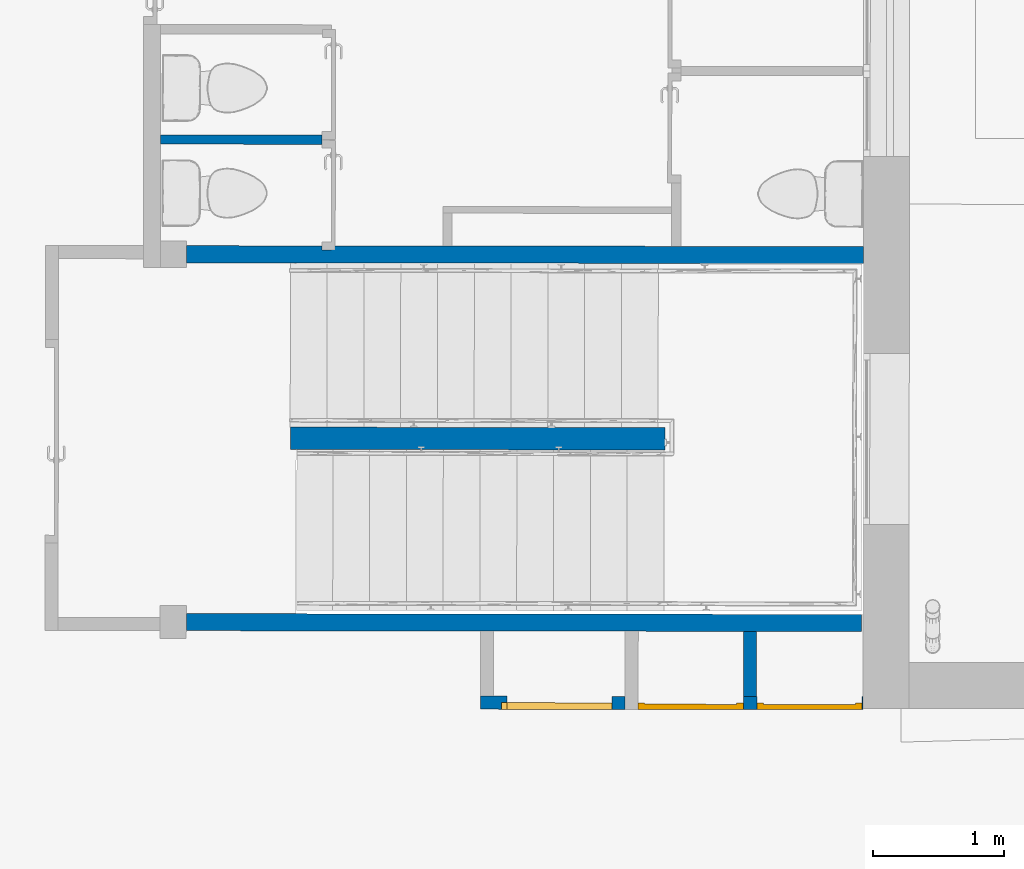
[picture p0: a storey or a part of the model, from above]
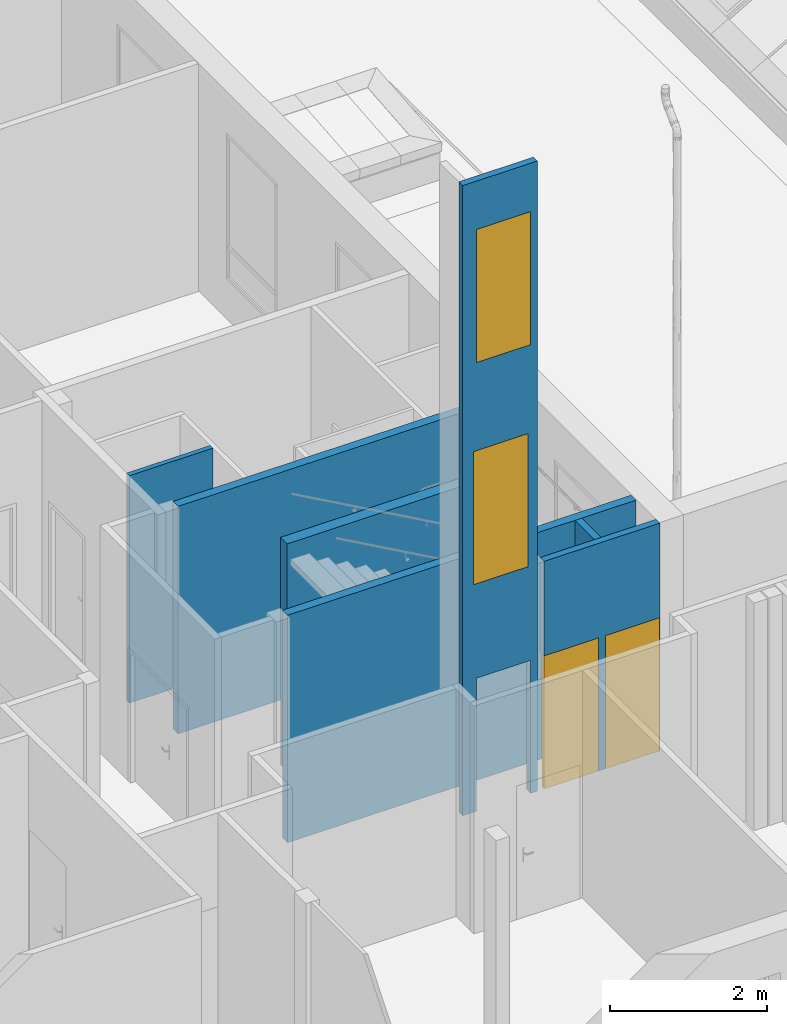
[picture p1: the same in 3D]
Properties of the parts of a building model (IFC2X3), part 1 of 4

# File
Description: ViewDefinition [CoordinationView_V2.0], RevitIdentifiers [ContentGUID: f4caa33b-e047-426b-b9fa-e7164e717685, VersionGUID: ece20d67-56b8-495e-9a75-15ed486fb8ca, NumberOfSaves: 694], CoordinateReference [CoordinateBase: Coordonnées partagées, ProjectSite: Interne]
File name: 260204_RECTORAT.ifc
Time: 2026-02-04T08:34:32+01:00
Written by: ODA SDAI 24.12
Made in: Autodesk Revit 25.4.0.32 (FRA) - IFC 25.4.0.32

# IfcProject, 792
LongName: RECTORAT DE REIMS; Phase: Etat du projet

# IfcSite, Surface:3634237
RefLatitude: 49, 14, 39, 881286; RefLongitude: 4, 2, 24, 676208; RefElevation: 0 m

# IfcBuilding
Pset_BuildingCommon - NumberOfStoreys: 7

# IfcBuildingStorey: Niveau:Ligne du Niveau (7)
Name | LongName | Elevation (m)
R-1 | R-1 | -7.05
rez de rue -1.10m | rez de rue -1.10m | -4.63
Rez de Rue Simon | Rez de Rue Simon | -3.55
0- Rdc | 0- Rdc | -5.76469e-13
1-R+1 | 1-R+1 | 3.55
2-R+2 | 2-R+2 | 7
3-Combles | 3-Combles | 10.03

# IfcBeam: ART-Béton - Poutre rectangulaire:Po 20x105 ht, ART-Béton - Poutre rectangulaire:Po 20x105 ht:3793338
In: Rez de Rue Simon
Type - PredefinedType: BEAM
Type - Pset_BeamCommon - LoadBearing: yes
Material: OMD_BLEU T1 23 25-SIKKKENS
Pset_BeamCommon - IsExternal: no; Slope: 0 deg; Reference: Po 20x105 ht; Span: 4 m
Pset_QuantityTakeOff - Reference: Po 20x105 ht; sets with these values: 2

# IfcBeam: ART-Béton - Poutre rectangulaire:Po 20x105 ht, ART-Béton - Poutre rectangulaire:Po 20x105 ht:3793427
In: Rez de Rue Simon
Type - Pset_BeamCommon - LoadBearing: yes
Material: OMD_BLEU T1 23 25-SIKKKENS
Pset_BeamCommon - IsExternal: no; Slope: 0 deg; Reference: Po 20x105 ht; Span: 7.52 m
Pset_QuantityTakeOff - Reference: Po 20x105 ht; sets with these values: 2

# IfcBeam: ART-Béton - Poutre rectangulaire:Po 20x40 ht (2)
Type - PredefinedType: BEAM
Type - Pset_BeamCommon - LoadBearing: yes
Material: Béton - Béton coulé sur place
Pset_BeamCommon - IsExternal: no; Slope: 0 deg; Reference: Po 20x40 ht; Span: 1.65911 m
Pset_QuantityTakeOff - Reference: Po 20x40 ht; sets with these values: 2
Name (ART-Béton - Poutre rectangulaire:Po 20x40 ht:...) | In
3980615 | Rez de Rue Simon
3980827 | rez de rue -1.10m

# IfcBeam: ART-Béton - Poutre rectangulaire:Po 20x60 ht, ART-Béton - Poutre rectangulaire:Po 20x60 ht:3804751
In: Rez de Rue Simon
Type - Pset_BeamCommon - LoadBearing: yes
Material: Béton - Béton coulé sur place
Pset_BeamCommon - IsExternal: no; Slope: 0 deg; Reference: Po 20x60 ht; Span: 4.89997 m
Pset_QuantityTakeOff - Reference: Po 20x60 ht; sets with these values: 2

# IfcBeam: ART-Béton - Poutre rectangulaire:Po 50x105 (4)
In: 0- Rdc
Type - PredefinedType: BEAM
Type - Pset_BeamCommon - LoadBearing: yes
Material: OMD_beton brut
Pset_BeamCommon - IsExternal: no; Reference: Po 50x105
Pset_QuantityTakeOff - Reference: Po 50x105; sets with these values: 2
Name (ART-Béton - Poutre rectangulaire:Po 50x105:...) | Span (m) | Slope (deg)
3305003 | 23.0697 | 0.510385
3305045 | 23.0697 | 0.510385
3305083 | 23.0915 | 0.509904
3305131 | 23.0959 | 0.510385

# IfcBeam: ART-Béton - Poutre rectangulaire:Po 5x5 ht acier (12)
Type - PredefinedType: BEAM
Type - Pset_BeamCommon - LoadBearing: yes
Material: RAL 7016 - Anthracite Grey
Pset_BeamCommon - IsExternal: no; Reference: Po 5x5 ht acier
Pset_QuantityTakeOff - Reference: Po 5x5 ht acier; sets with these values: 2
Name (ART-Béton - Poutre rectangulaire:Po 5x5 ht acier:...) | In | Span (m) | Slope (deg)
3578441 | Rez de Rue Simon | 8.45535 | 0.576966
3578546 | Rez de Rue Simon | 8.45174 | 0.639205
5396951 | 0- Rdc | 2.92444 | 1.0679
5397064 | 0- Rdc | 2.27062 | 0.000471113
5397077 | 0- Rdc | 4.4843 | 0.000399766
5397089 | 0- Rdc | 2.3227 | 0.00046729
5397097 | 0- Rdc | 2.93 | 0
5397385 | 0- Rdc | 4.5 | 0
5459528 | Rez de Rue Simon | 10.413 | 0.541948
5485070 | Rez de Rue Simon | 10.4623 | 0.544122
5485907 | Rez de Rue Simon | 4.62568 | 0.576966
5485982 | Rez de Rue Simon | 4.62568 | 0.576966

# IfcBeam: Basting:50*200 (10)
In: Rez de Rue Simon
Type - PredefinedType: BEAM
Type - Pset_BeamCommon - LoadBearing: yes
Material: Bois - Bois de construction de dimensions courantes
Pset_BeamCommon - IsExternal: no; Slope: 0 deg; Reference: 50*200
Pset_QuantityTakeOff - Reference: 50*200; sets with these values: 2
Name (Basting:50*200:...) | Span (m)
3705377 | 5.344
3705426 | 5.48
3705459 | 5.379
3705491 | 5.379
3705527 | 5.379
3705563 | 5.379
3754956 | 5.379
3755321 | 5.343
4002185 | 5.379
4002186 | 5.379

# IfcBeam: Basting:poutre BLC GL24h 100x240 (19)
Type - PredefinedType: BEAM
Type - Pset_BeamCommon - LoadBearing: yes
Material: Bois - Bois de construction de dimensions courantes
Pset_BeamCommon - IsExternal: no; Reference: poutre BLC GL24h 100x240
Pset_QuantityTakeOff - Reference: poutre BLC GL24h 100x240; sets with these values: 2
Name (Basting:poutre BLC GL24h 100x240:...) | In | Slope (deg) | Span (m)
4304110 | R-1 | 0 | 2.96
5301227 | Rez de Rue Simon | 0.00000120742 | 2.66
5301454 | Rez de Rue Simon | 0 | 1.851
5301537 | Rez de Rue Simon | 0 | 1.85
5301573 | Rez de Rue Simon | 0 | 1.85
5301637 | Rez de Rue Simon | 0 | 1.85
5301671 | Rez de Rue Simon | 0 | 2.47
5301752 | Rez de Rue Simon | 0 | 2.469
5301788 | Rez de Rue Simon | 0 | 1.851
5301858 | Rez de Rue Simon | 0 | 1.851
5301893 | Rez de Rue Simon | 0 | 1.85
5302000 | Rez de Rue Simon | 0 | 1.85
5302042 | Rez de Rue Simon | 0 | 2.651
5302099 | Rez de Rue Simon | 0.00000120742 | 2.64
5302156 | Rez de Rue Simon | 0 | 1.85
5302232 | Rez de Rue Simon | 0 | 1.851
5302264 | Rez de Rue Simon | 0 | 1.85
5302329 | Rez de Rue Simon | 0 | 1.85
5302355 | Rez de Rue Simon | 0 | 2.46

# IfcBeam: Basting:poutre BLC GL24h 100x280 (6)
In: Rez de Rue Simon
Type - PredefinedType: BEAM
Type - Pset_BeamCommon - LoadBearing: yes
Material: Bois - Bois de construction de dimensions courantes
Pset_BeamCommon - IsExternal: no; Slope: 0 deg; Reference: poutre BLC GL24h 100x280
Pset_QuantityTakeOff - Reference: poutre BLC GL24h 100x280; sets with these values: 2
Name (Basting:poutre BLC GL24h 100x280:...) | Span (m)
5301495 | 2.351
5301600 | 2.35
5301829 | 2.35
5301972 | 2.349
5302182 | 2.349
5302294 | 2.35

# IfcBeam: Basting:poutre BLC GL24h 100x320 (4)
In: Rez de Rue Simon
Type - PredefinedType: BEAM
Type - Pset_BeamCommon - LoadBearing: yes
Material: Bois - Bois de construction de dimensions courantes
Pset_BeamCommon - IsExternal: no; Slope: 0 deg; Reference: poutre BLC GL24h 100x320
Pset_QuantityTakeOff - Reference: poutre BLC GL24h 100x320; sets with these values: 2
Name (Basting:poutre BLC GL24h 100x320:...) | Span (m)
5300478 | 0.464
5300546 | 0.499
5301009 | 1.851
5301033 | 1.86

# IfcBeam: Basting:poutre BLC GL24h 100x360 (5)
In: Rez de Rue Simon
Type - PredefinedType: BEAM
Type - Pset_BeamCommon - LoadBearing: yes
Material: Bois - Bois de construction de dimensions courantes
Pset_BeamCommon - IsExternal: no; Slope: 0 deg; Reference: poutre BLC GL24h 100x360
Pset_QuantityTakeOff - Reference: poutre BLC GL24h 100x360; sets with these values: 2
Name (Basting:poutre BLC GL24h 100x360:...) | Span (m)
5300805 | 2.351
5301063 | 2.35
5301519 | 2.851
5301933 | 2.85
5302206 | 2.85

# IfcBeam: Basting:poutre BLC GL24h 120x400, Basting:poutre BLC GL24h 120x400:5300973
In: Rez de Rue Simon
Type - PredefinedType: BEAM
Type - Pset_BeamCommon - LoadBearing: yes
Material: Bois - Bois de construction de dimensions courantes
Pset_BeamCommon - IsExternal: no; Slope: 0 deg; Reference: poutre BLC GL24h 120x400; Span: 2.851 m
Pset_QuantityTakeOff - Reference: poutre BLC GL24h 120x400; sets with these values: 2

# IfcBeam: Basting:solive BM C24 100X160 EA 600 (40)
In: Rez de Rue Simon
Type - PredefinedType: BEAM
Type - Pset_BeamCommon - LoadBearing: yes
Material: Bois - Bois de construction de dimensions courantes
Pset_BeamCommon - IsExternal: no; Slope: 0 deg; Reference: solive BM C24 100X160 EA 600
Pset_QuantityTakeOff - Reference: solive BM C24 100X160 EA 600; sets with these values: 2
Name (Basting:solive BM C24 100X160 EA 600:...) | Span (m)
5303792 | 2.287
5303817 | 2.287
5303842 | 2.3
5303867 | 2.28
5303905 | 2.306
5303939 | 2.306
5303977 | 2.32
5304009 | 2.292
5304036 | 2.28
5304059 | 2.28
5304084 | 2.28
5304104 | 2.28
5304132 | 2.3
5304161 | 2.3
5304193 | 2.3
5304222 | 2.311
5304252 | 2.311
5304281 | 2.311
5304308 | 2.311
5304345 | 2.308
5304378 | 2.306
5304405 | 2.31
5304436 | 2.308
5304458 | 2.308
5304492 | 2.307
5304518 | 2.306
5304544 | 2.305
5304571 | 2.305
5304590 | 2.303
5304616 | 2.302
5304643 | 2.301
5304665 | 2.301
5304700 | 2.299
5304722 | 2.321
5304749 | 2.298
5304777 | 2.297
5304809 | 2.331
5304832 | 2.322
5304862 | 2.331
5304896 | 2.32

# IfcBeam: Basting:solive BM C24 10X220 EA 600 (120)
In: Rez de Rue Simon
Type - PredefinedType: BEAM
Type - Pset_BeamCommon - LoadBearing: yes
Material: Bois - Bois de construction de dimensions courantes
Pset_BeamCommon - IsExternal: no; Slope: 0 deg; Reference: solive BM C24 10X220 EA 600
Pset_QuantityTakeOff - Reference: solive BM C24 10X220 EA 600; sets with these values: 2
Name (Basting:solive BM C24 10X220 EA 600:...) | Span (m)
5304961 | 3.229
5304980 | 3.23
5305010 | 3.23
5305025 | 3.23
5305057 | 3.18
5305077 | 3.23
5305090 | 3.23
5305116 | 3.22
5305132 | 3.18
5305149 | 3.23
5305166 | 3.24
5305189 | 3.229
5305211 | 3.229
5305237 | 3.18
5305274 | 3.23
5305297 | 3.22
5305325 | 3.24
5305348 | 3.23
5305365 | 3.18
5305388 | 3.23
5305422 | 3.24
5305442 | 3.23
5305455 | 3.2
5305479 | 3.229
5305494 | 3.229
5305529 | 3.229
5305544 | 3.18
5305563 | 3.23
5305585 | 3.22
5305612 | 3.229
5305635 | 3.23
5305657 | 3.18
5305676 | 3.229
5305700 | 3.24
5305715 | 3.229
5305743 | 3.2
5305776 | 3.23
5305797 | 3.23
5305820 | 3.24
5305843 | 3.23
5306093 | 3.23
5306094 | 3.23
5306095 | 3.23
5306096 | 3.23
5306097 | 3.18
5306098 | 3.23
5306099 | 3.23
5306100 | 3.269
5306101 | 3.18
5306102 | 3.23
5306103 | 3.24
5306104 | 3.23
5306105 | 3.23
5306106 | 3.18
5306107 | 3.23
5306108 | 3.22
5306109 | 3.24
5306110 | 3.23
5306111 | 3.18
5306112 | 3.23
5306113 | 3.24
5306114 | 3.23
5306115 | 3.2
5306116 | 3.229
5306117 | 3.23
5306118 | 3.229
5306119 | 3.18
5306120 | 3.23
5306121 | 3.22
5306122 | 3.229
5306123 | 3.23
5306124 | 3.18
5306125 | 3.229
5306126 | 3.24
5306127 | 3.229
5306128 | 3.2
5306129 | 3.23
5306130 | 3.23
5306131 | 3.24
5306132 | 3.23
5306140 | 3.169
5306141 | 3.169
5306142 | 3.168
5306143 | 3.167
5306144 | 3.142
5306145 | 3.166
5306146 | 3.166
5306147 | 3.165
5306148 | 3.14
5306149 | 3.164
5306150 | 3.174
5306151 | 1.582
5306152 | 1.581
5306153 | 1.556
5306154 | 1.58
5306155 | 1.579
5306156 | 1.59
5306157 | 1.578
5306158 | 1.553
5306159 | 1.577
5306160 | 1.587
5306161 | 1.576
5306162 | 1.571
5306163 | 1.575
5306164 | 1.574
5306165 | 1.573
5306166 | 1.549
5306167 | 1.572
5306168 | 1.563
5306169 | 1.571
5306170 | 3.149
5306171 | 3.123
5306172 | 3.147
5306173 | 3.147
5306174 | 3.146
5306175 | 3.12
5306176 | 3.144
5306177 | 3.144
5306178 | 3.154
5306179 | 3.142

# IfcBeam: Basting:solive BM C24 120X320 EA 600 (42)
In: Rez de Rue Simon
Type - PredefinedType: BEAM
Type - Pset_BeamCommon - LoadBearing: yes
Material: Bois - Bois de construction de dimensions courantes
Pset_BeamCommon - IsExternal: no; Slope: 0 deg; Reference: solive BM C24 120X320 EA 600
Pset_QuantityTakeOff - Reference: solive BM C24 120X320 EA 600; sets with these values: 2
Name (Basting:solive BM C24 120X320 EA 600:...) | Span (m)
5306624 | 4.454
5306698 | 4.455
5306706 | 4.456
5306716 | 4.457
5306728 | 4.448
5306738 | 4.342
5306746 | 4.45
5306754 | 4.451
5306762 | 4.423
5306772 | 4.462
5306780 | 4.463
5306788 | 4.463
5306796 | 4.425
5306804 | 4.465
5306812 | 4.465
5306822 | 4.466
5306832 | 4.428
5306840 | 4.467
5306850 | 4.468
5306860 | 4.469
5306874 | 4.47
5306884 | 4.451
5306892 | 3.327
5306902 | 4.445
5306912 | 4.445
5306922 | 4.444
5306930 | 4.435
5306944 | 4.435
5306954 | 4.435
5306966 | 4.435
5306980 | 3.324
5306988 | 4.435
5306996 | 4.435
5307004 | 4.435
5307014 | 4.435
5307022 | 4.435
5307032 | 4.435
5307042 | 4.435
5307161 | 4.415
5307171 | 4.418
5307296 | 0.802
5307322 | 1.199

# IfcBeam: Poutre - Barre ronde:450MM (2)
In: Rez de Rue Simon
Type - PredefinedType: BEAM
Type - Pset_BeamCommon - LoadBearing: yes
Material: OMD-Gaine
Pset_BeamCommon - IsExternal: no; Reference: 450MM; Slope: 0.605548 deg
Pset_QuantityTakeOff - Reference: 450MM; sets with these values: 2
Name (Poutre - Barre ronde:450MM:...) | Span (m)
4188247 | 14.613
4188297 | 14.486

# IfcBuildingElementProxy: A6305 - Drapes, Pair 36 x 3:A6305 - Drapes, Pair 36"x 3", A6305 - Drapes, Pair 36 x 3:A6305 - Drapes, Pair 36"x 3":4141119
In: rez de rue -1.10m
Type - Material: OMD-rideaux
Pset_BuildingElementProxyCommon - Reference: A6305 - Drapes, Pair 36"x 3"; sets with these values: 2

# IfcBuildingElementProxy: A6305 - Drapes:A6305 - Drapes, Pair 36"x 3" (5)
In: rez de rue -1.10m
Type - Material: OMD-rideaux
Pset_BuildingElementProxyCommon - Reference: A6305 - Drapes, Pair 36"x 3"; sets with these values: 2
Name (A6305 - Drapes:A6305 - Drapes, Pair 36"x 3":...)
3613168
3613169
4280353
4280397
4723777

# IfcBuildingElementProxy: Canva 1200x2400x60 mm:Canva 1200x2400x60 mm Plaster (3)
In: Rez de Rue Simon
Type - Material: Plaster, White RAL 9003, Absorber
Pset_BuildingElementProxyCommon - Reference: Canva 1200x2400x60 mm Plaster; sets with these values: 2
Name (Canva 1200x2400x60 mm:Canva 1200x2400x60 mm Plaster:...)
4249678
5474097
5485304

# IfcBuildingElementProxy: Canva 1200x900x60 mm:Canva 1200x900x60 mm Plaster (4)
In: Rez de Rue Simon
Type - Material: Plaster, White RAL 9003, Absorber
Pset_BuildingElementProxyCommon - Reference: Canva 1200x900x60 mm Plaster; sets with these values: 2
Name (Canva 1200x900x60 mm:Canva 1200x900x60 mm Plaster:...)
4249681
5485296
5485298
5485299

# IfcBuildingElementProxy: Constructions-Lifts_Liftup_easylift-900-800:Liftup - Material - Non-skid Linoleum, Constructions-Lifts_Liftup_easylift-900-800:Liftup - Material - Non-skid Linoleum:5440786
In: rez de rue -1.10m
Type - Material: Liftup - Metal - Stainless Steel, Liftup - Plastic - Dark Grey, Liftup - Plastic - Non-skid Linoleum, Painted White, Warning Red
Type - Pset_ManufacturerTypeInformation - Manufacturer: Liftup
Material: Liftup - Metal - Stainless Steel, Liftup - Polycarbonate - Clear, Liftup - Plastic - Non-skid Linoleum
Pset_BuildingElementProxyCommon - Reference: Liftup - Material - Non-skid Linoleum; sets with these values: 2

# IfcBuildingElementProxy: Cordivari_ROSY_VT:H._2200 mm__Altezza Standard (7)
In: Rez de Rue Simon
Type - Material: <Unnamed>, BIANCO RAL 9010
Type - Pset_ManufacturerTypeInformation - Manufacturer: CORDIVARI
Pset_BuildingElementProxyCommon - Reference: H._2200 mm__Altezza Standard; sets with these values: 2
Name (Cordivari_ROSY_VT:H._2200 mm__Altezza Standard:...)
4178981
4179306
4179318
5448377
5448378
5448379
5448380

# IfcBuildingElementProxy: Electronics_Communication_Cisco_LG-86-Display-Single:LG 86" Display Single (3)
In: Rez de Rue Simon
Type - Material: LCD - Cisco - Black, Plastic - Cisco - Dark Gray
Type - Pset_ManufacturerTypeInformation - Manufacturer: Cisco
Material: Plastic - Cisco - Dark Gray, LCD - Cisco - Black
Pset_BuildingElementProxyCommon - Reference: LG 86" Display Single; sets with these values: 2
Name (Electronics_Communication_Cisco_LG-86-Display-Single:LG 86" Display Single:...)
3973912
4651875
4651930

# IfcBuildingElementProxy: FONDATIONS1:FONDATIONS, FONDATIONS1:FONDATIONS:5438699
In: R-1
Type - Material: <Unnamed>
Pset_BuildingElementProxyCommon - Reference: FONDATIONS; sets with these values: 2

# IfcBuildingElementProxy: FONDATIONS2:FONDATIONS, FONDATIONS2:FONDATIONS:5446419
In: R-1
Type - Material: <Unnamed>
Pset_BuildingElementProxyCommon - Reference: FONDATIONS; sets with these values: 2

# IfcBuildingElementProxy: FONDATIONS3:FONDATIONS, FONDATIONS3:FONDATIONS:5446494
In: R-1
Type - Material: <Unnamed>
Pset_BuildingElementProxyCommon - Reference: FONDATIONS; sets with these values: 2

# IfcBuildingElementProxy: FONDATIONS:FONDATIONS, FONDATIONS:FONDATIONS:5437896
In: R-1
Type - Material: <Unnamed>
Pset_BuildingElementProxyCommon - Reference: FONDATIONS; sets with these values: 2

# IfcBuildingElementProxy: ISOLANT COMBLEMENT ESC:ISOLANT COMBLEMENT ESC, ISOLANT COMBLEMENT ESC:ISOLANT COMBLEMENT ESC:3799403
In: Rez de Rue Simon
Type - Material: Maçonnerie - Isolant
Pset_BuildingElementProxyCommon - Reference: ISOLANT COMBLEMENT ESC; sets with these values: 2

# IfcBuildingElementProxy: Profil en relief:tube facade profil 1% (4)
Material: OMD_couleur facade-blanc perlé
Pset_BuildingElementProxyCommon - Reference: tube facade profil 1%; sets with these values: 2
Name (Profil en relief:tube facade profil 1%:...) | In
5286197 | 0- Rdc
5286381 | Rez de Rue Simon
5286421 | rez de rue -1.10m
5287493 | 0- Rdc

# IfcBuildingElementProxy: Rockfon Canva Floor Screen 1200 x 1800 x 61 mm_flat_base:Rockfon Canva Floor Screen 1200 x 1800 x 61 mm_flat_base_Frame_White_Canvas_Plaster (9)
In: rez de rue -1.10m
Type - Material: Plaster, White
Pset_BuildingElementProxyCommon - Reference: Rockfon Canva Floor Screen 1200 x 1800 x 61 mm_flat_base_Frame_White_Canvas_Plaster; sets with these values: 2
Name (Rockfon Canva Floor Screen 1200 x 1800 x 61 mm_flat_base:Rockfon Canva Floor Screen 1200 x 1800 x 61 mm_flat_base_Frame_White_Canvas_Plaster:...)
5418240
5418241
5418242
5418243
5418244
5418245
5418246
5418247
5418248

# IfcBuildingElementProxy: Sanitary_Toilet-Accessories_DELABIE_35082W-Basic-angled-grab-bar-135deg:Sanitary_Toilet-Accessories_DELABIE_35082W-Basic-angled-grab-bar-135deg, Sanitary_Toilet-Accessories_DELABIE_35082W-Basic-angled-grab-bar-135deg:Sanitary_Toilet-Accessories_DELABIE_35082W-Basic-angled-grab-bar-135deg:4074320
In: Rez de Rue Simon
Type - Material: 35082W Basic angled grab bar 135deg - 35082W - blanc
Pset_BuildingElementProxyCommon - Reference: Sanitary_Toilet-Accessories_DELABIE_35082W-Basic-angled-grab-bar-135deg; sets with these values: 2

# IfcBuildingElementProxy: Sanitary_Urinals_DELABIE_134718-DELTACERAM-wall-hung-urinal:Sanitary_Urinals_DELABIE_134718-DELTACERAM-wall-hung-urinal, Sanitary_Urinals_DELABIE_134718-DELTACERAM-wall-hung-urinal:Sanitary_Urinals_DELABIE_134718-DELTACERAM-wall-hung-urinal:4210427
In: Rez de Rue Simon
Type - Material: 134718 DELTACÉRAM wall hung urinal - 134718 - blanc
Material: 134718 DELTACÉRAM wall hung urinal - 134718 - blanc, <Unnamed>
Pset_BuildingElementProxyCommon - Reference: Sanitary_Urinals_DELABIE_134718-DELTACERAM-wall-hung-urinal; sets with these values: 2

# IfcBuildingElementProxy: Texte 3D:Texte 3D 1, Texte 3D:Texte 3D 1:3503385
In: Rez de Rue Simon
Pset_BuildingElementProxyCommon - Reference: Texte 3D 1; sets with these values: 2

# IfcBuildingElementProxy: appui fenetre:appui fenetre, appui fenetre:appui fenetre:3309578
In: Rez de Rue Simon
Type - Material: OMD_Béton blanc
Pset_BuildingElementProxyCommon - Reference: appui fenetre; sets with these values: 2

# IfcBuildingElementProxy: gradins:gradins, gradins:gradins:3290303
In: R-1
Type - Material: OMD_Béton blanc
Pset_BuildingElementProxyCommon - Reference: gradins; sets with these values: 2

# IfcBuildingElementProxy: grille 2:grille 2, grille 2:grille 2:4673213
In: 0- Rdc
Type - Material: White RAL 9003
Pset_BuildingElementProxyCommon - Reference: grille 2; sets with these values: 2

# IfcBuildingElementProxy: grille WC:grille WC, grille WC:grille WC:4669382
In: 0- Rdc
Type - Material: White RAL 9003
Pset_BuildingElementProxyCommon - Reference: grille WC; sets with these values: 2

# IfcColumn: ART-Béton-Poteau rectangulaire:15x15 (35)
In: R-1
Type - PredefinedType: COLUMN; Material: Cerisier
Type - Pset_ColumnCommon - LoadBearing: yes
Pset_ColumnCommon - IsExternal: no; Reference: 15x15
Pset_QuantityTakeOff - Reference: 15x15; sets with these values: 2
Name (ART-Béton-Poteau rectangulaire:15x15:...)
3817159
3817262
3817280
3817290
3817300
3817322
3817733
3817768
3817853
3817854
3817856
3817857
3817858
3817859
3817860
3817861
3817871
3817872
3817874
3817875
3817876
3817877
3817878
3817879
3817977
3817978
3817979
3817980
3817981
4301156
4301157
4301158
4301327
4301328
4301329

# IfcColumn: ART-Béton-Poteau rectangulaire:15x2 ventelles (20)
In: Rez de Rue Simon
Type - PredefinedType: COLUMN; Material: Bois - Bois de construction de dimensions courantes
Type - Pset_ColumnCommon - LoadBearing: yes
Pset_ColumnCommon - IsExternal: no; Reference: 15x2 ventelles
Pset_QuantityTakeOff - Reference: 15x2 ventelles; sets with these values: 2
Name (ART-Béton-Poteau rectangulaire:15x2 ventelles:...)
3704977
3704987
3704997
3705007
3705017
3706369 | Pset_ColumnCommon - Slope: 0 deg
3706370 | Pset_ColumnCommon - Slope: 0 deg
3754954 | Pset_ColumnCommon - Slope: 0 deg
3754955 | Pset_ColumnCommon - Slope: 0 deg
4002103
4002115
4820052
4916291
4916292
4916293
4916294
4916295
4916296
4916297
4916298

# IfcColumn: ART-Béton-Poteau rectangulaire:20X20 (32)
Type - PredefinedType: COLUMN; Material: <Unnamed>
Type - Pset_ColumnCommon - LoadBearing: yes
Pset_ColumnCommon - IsExternal: no; Reference: 20X20
Pset_QuantityTakeOff - Reference: 20X20; sets with these values: 2
Name (ART-Béton-Poteau rectangulaire:20X20:...) | In
3229581 | 0- Rdc
3229723 | 0- Rdc
3230643 | 0- Rdc
3230644 | 0- Rdc
3230715 | 0- Rdc
3230716 | 0- Rdc
3230753 | 0- Rdc
3230754 | 0- Rdc
3233405 | 0- Rdc
3233417 | 0- Rdc
3233427 | 0- Rdc
3234115 | 0- Rdc
3238927 | 0- Rdc
3238939 | 0- Rdc
3251588 | Rez de Rue Simon | Pset_ColumnCommon - Slope: 0 deg
3252008 | 0- Rdc
3252346 | Rez de Rue Simon | Pset_ColumnCommon - Slope: 0 deg
3252352 | Rez de Rue Simon | Pset_ColumnCommon - Slope: 0 deg
3252353 | Rez de Rue Simon | Pset_ColumnCommon - Slope: 0 deg
3252354 | Rez de Rue Simon | Pset_ColumnCommon - Slope: 0 deg
3252355 | Rez de Rue Simon
3252365 | Rez de Rue Simon
3252368 | Rez de Rue Simon
3252375 | Rez de Rue Simon | Pset_ColumnCommon - Slope: 0 deg
3252376 | Rez de Rue Simon | Pset_ColumnCommon - Slope: 0 deg
3252377 | Rez de Rue Simon | Pset_ColumnCommon - Slope: 0 deg
3252402 | Rez de Rue Simon
3272346 | R-1
3273177 | R-1
3273178 | R-1
3277271 | R-1
3277653 | R-1

# IfcColumn: ART-Béton-Poteau rectangulaire:20X25 (8)
Type - PredefinedType: COLUMN; Material: <Unnamed>
Type - Pset_ColumnCommon - LoadBearing: yes
Pset_ColumnCommon - IsExternal: no; Reference: 20X25
Pset_QuantityTakeOff - Reference: 20X25; sets with these values: 2
Name (ART-Béton-Poteau rectangulaire:20X25:...) | In
3230350 | 0- Rdc
3230351 | 0- Rdc
3234003 | 0- Rdc
3234004 | 0- Rdc
3250959 | Rez de Rue Simon | Pset_ColumnCommon - Slope: 0 deg
3252351 | Rez de Rue Simon | Pset_ColumnCommon - Slope: 0 deg
3252366 | Rez de Rue Simon
3252367 | Rez de Rue Simon

# IfcColumn: ART-Béton-Poteau rectangulaire:20X30 (25)
Type - PredefinedType: COLUMN; Material: <Unnamed>
Type - Pset_ColumnCommon - LoadBearing: yes
Pset_ColumnCommon - IsExternal: no; Reference: 20X30
Pset_QuantityTakeOff - Reference: 20X30; sets with these values: 2
Name (ART-Béton-Poteau rectangulaire:20X30:...) | In
3230095 | 0- Rdc
3230096 | 0- Rdc
3230283 | 0- Rdc
3230284 | 0- Rdc
3233508 | 0- Rdc
3233518 | 0- Rdc
3234163 | 0- Rdc
3234164 | 0- Rdc
3238803 | 0- Rdc
3238804 | 0- Rdc
3238840 | 0- Rdc
3238841 | 0- Rdc
3252347 | Rez de Rue Simon | Pset_ColumnCommon - Slope: 0 deg
3252348 | Rez de Rue Simon | Pset_ColumnCommon - Slope: 0 deg
3252349 | Rez de Rue Simon | Pset_ColumnCommon - Slope: 0 deg
3252350 | Rez de Rue Simon | Pset_ColumnCommon - Slope: 0 deg
3252369 | Rez de Rue Simon
3252371 | Rez de Rue Simon
3252372 | Rez de Rue Simon
3252373 | Rez de Rue Simon
3252374 | Rez de Rue Simon
3274005 | R-1
3274006 | R-1
3277561 | R-1
3277562 | R-1

# IfcColumn: ART-Béton-Poteau rectangulaire:30X70 (2)
In: Rez de Rue Simon
Type - PredefinedType: COLUMN; Material: <Unnamed>
Type - Pset_ColumnCommon - LoadBearing: yes
Pset_ColumnCommon - IsExternal: no; Reference: 30X70
Pset_QuantityTakeOff - Reference: 30X70; sets with these values: 2
Name (ART-Béton-Poteau rectangulaire:30X70:...)
3252459
3252475

# IfcColumn: ART-Béton-Poteau rectangulaire:30x30, ART-Béton-Poteau rectangulaire:30x30:3230843
In: 0- Rdc
Type - PredefinedType: COLUMN; Material: <Unnamed>
Type - Pset_ColumnCommon - LoadBearing: yes
Pset_ColumnCommon - IsExternal: no; Reference: 30x30
Pset_QuantityTakeOff - Reference: 30x30; sets with these values: 2

# IfcColumn: ART-Béton-Poteau rectangulaire:30x55, ART-Béton-Poteau rectangulaire:30x55:3259848
In: Rez de Rue Simon
Type - PredefinedType: COLUMN; Material: <Unnamed>
Type - Pset_ColumnCommon - LoadBearing: yes
Pset_ColumnCommon - IsExternal: no; Slope: 0 deg; Reference: 30x55
Pset_QuantityTakeOff - Reference: 30x55; sets with these values: 2

# IfcColumn: ART-Béton-Poteau rectangulaire:30x55, ART-Béton-Poteau rectangulaire:30x55:3265502
In: Rez de Rue Simon
Type - PredefinedType: COLUMN; Material: OMD_BLEU T1 23 25-SIKKKENS
Type - Pset_ColumnCommon - LoadBearing: yes
Pset_ColumnCommon - IsExternal: no; Slope: 0 deg; Reference: 30x55
Pset_QuantityTakeOff - Reference: 30x55; sets with these values: 2

# IfcColumn: ART-Béton-Poteau rectangulaire:40x40 (2)
Type - PredefinedType: COLUMN; Material: <Unnamed>
Type - Pset_ColumnCommon - LoadBearing: yes
Pset_ColumnCommon - IsExternal: no; Reference: 40x40
Pset_QuantityTakeOff - Reference: 40x40; sets with these values: 2
Name (ART-Béton-Poteau rectangulaire:40x40:...) | In
3276257 | Rez de Rue Simon | Pset_ColumnCommon - Slope: 0 deg
3276296 | R-1

# IfcColumn: ART-Béton-Poteau rectangulaire:40x50, ART-Béton-Poteau rectangulaire:40x50:3276399
In: Rez de Rue Simon
Type - PredefinedType: COLUMN; Material: <Unnamed>
Type - Pset_ColumnCommon - LoadBearing: yes
Pset_ColumnCommon - IsExternal: no; Slope: 0 deg; Reference: 40x50
Pset_QuantityTakeOff - Reference: 40x50; sets with these values: 2

# IfcColumn: ART-Béton-Poteau rectangulaire:50X27 (2)
In: 0- Rdc
Type - PredefinedType: COLUMN; Material: <Unnamed>
Type - Pset_ColumnCommon - LoadBearing: yes
Pset_ColumnCommon - IsExternal: no; Reference: 50X27
Pset_QuantityTakeOff - Reference: 50X27; sets with these values: 2
Name (ART-Béton-Poteau rectangulaire:50X27:...)
3232734
3232983

# IfcColumn: ART-Béton-Poteau rectangulaire:50X40 (2)
In: 3-Combles
Type - PredefinedType: COLUMN; Material: Béton
Type - Pset_ColumnCommon - LoadBearing: yes
Pset_ColumnCommon - IsExternal: no; Reference: 50X40
Pset_QuantityTakeOff - Reference: 50X40; sets with these values: 2
Name (ART-Béton-Poteau rectangulaire:50X40:...)
4783936
4783994

# IfcColumn: ART-Béton-Poteau rectangulaire:60X40 béton, ART-Béton-Poteau rectangulaire:60X40 béton:4783846
In: 3-Combles
Type - PredefinedType: COLUMN; Material: Béton
Type - Pset_ColumnCommon - LoadBearing: yes
Pset_ColumnCommon - IsExternal: no; Reference: 60X40 béton
Pset_QuantityTakeOff - Reference: 60X40 béton; sets with these values: 2

# IfcColumn: ART-Béton-Poteau rectangulaire:70X40 béton, ART-Béton-Poteau rectangulaire:70X40 béton:4783792
In: 3-Combles
Type - PredefinedType: COLUMN; Material: Béton
Type - Pset_ColumnCommon - LoadBearing: yes
Pset_ColumnCommon - IsExternal: no; Reference: 70X40 béton
Pset_QuantityTakeOff - Reference: 70X40 béton; sets with these values: 2

# IfcColumn: Poteau rectangulaire:200x200mm (2)
In: Rez de Rue Simon
Type - PredefinedType: COLUMN; Material: Métal - Acier
Pset_ColumnCommon - IsExternal: no; Slope: 0 deg; Reference: 200x200mm
Pset_QuantityTakeOff - Reference: 200x200mm; sets with these values: 2
Name (Poteau rectangulaire:200x200mm:...)
3805787
4001351

# IfcColumn: Profil creux rectangulaire RHS:270x50RHS (78)
In: 0- Rdc
Type - PredefinedType: COLUMN; Material: OMD_couleur facade-blanc perlé
Type - Pset_ColumnCommon - LoadBearing: yes
Pset_ColumnCommon - IsExternal: no; Reference: 270x50RHS
Pset_QuantityTakeOff - Reference: 270x50RHS; sets with these values: 2
Name (Profil creux rectangulaire RHS:270x50RHS:...) | Group
3640885
3640905
3640913
3640979
3641446
3641458
3641468
3641480
3641494
3641522
3641534
3641544
3641556
3641576
3641586
3641596
3641610
3641646
3641658
3641670
3641686
3641698
3641708
3641718
3641728
3641762
3641770
3641780
3641794
3641808
3644279
3644388 | Groupe de modèles:Groupe 1 (membre exclu):4317548
3644389 | Groupe de modèles:Groupe 1 (membre exclu):4317548
3644390 | Groupe de modèles:Groupe 1 (membre exclu):4317548
3644391 | Groupe de modèles:Groupe 1 (membre exclu):4317548
3644392 | Groupe de modèles:Groupe 1 (membre exclu):4317548
3644393 | Groupe de modèles:Groupe 1 (membre exclu):4317548
3644395 | Groupe de modèles:Groupe 1 (membre exclu):4317548
3644396 | Groupe de modèles:Groupe 1 (membre exclu):4317548
3644397 | Groupe de modèles:Groupe 1 (membre exclu):4317548
3644398 | Groupe de modèles:Groupe 1 (membre exclu):4317548
3644399 | Groupe de modèles:Groupe 1 (membre exclu):4317548
3644400 | Groupe de modèles:Groupe 1 (membre exclu):4317548
3644401 | Groupe de modèles:Groupe 1 (membre exclu):4317548
3644402 | Groupe de modèles:Groupe 1 (membre exclu):4317548
3644403 | Groupe de modèles:Groupe 1 (membre exclu):4317548
3644404 | Groupe de modèles:Groupe 1 (membre exclu):4317548
3644405 | Groupe de modèles:Groupe 1 (membre exclu):4317548
3644406 | Groupe de modèles:Groupe 1 (membre exclu):4317548
3644407 | Groupe de modèles:Groupe 1 (membre exclu):4317548
3644408 | Groupe de modèles:Groupe 1 (membre exclu):4317548
3644409 | Groupe de modèles:Groupe 1 (membre exclu):4317548
3644410 | Groupe de modèles:Groupe 1 (membre exclu):4317548
3644411 | Groupe de modèles:Groupe 1 (membre exclu):4317548
3644412 | Groupe de modèles:Groupe 1 (membre exclu):4317548
3644413 | Groupe de modèles:Groupe 1 (membre exclu):4317548
3644414 | Groupe de modèles:Groupe 1 (membre exclu):4317548
3644415 | Groupe de modèles:Groupe 1 (membre exclu):4317548
3644416 | Groupe de modèles:Groupe 1 (membre exclu):4317548
3644417 | Groupe de modèles:Groupe 1 (membre exclu):4317548
3644418 | Groupe de modèles:Groupe 1 (membre exclu):4317548
3644419 | Groupe de modèles:Groupe 1 (membre exclu):4317548
3644420 | Groupe de modèles:Groupe 1 (membre exclu):4317548
3644421 | Groupe de modèles:Groupe 1 (membre exclu):4317548
3644422 | Groupe de modèles:Groupe 1 (membre exclu):4317548
3644423 | Groupe de modèles:Groupe 1 (membre exclu):4317548
3661567 | Groupe de modèles:Groupe 1 (membre exclu):4317548
4150109 | Groupe de modèles:Groupe 1 (membre exclu):4317548
4150111 | Groupe de modèles:Groupe 1 (membre exclu):4317548
4150113 | Groupe de modèles:Groupe 1 (membre exclu):4317548
4150115 | Groupe de modèles:Groupe 1 (membre exclu):4317548
4150117 | Groupe de modèles:Groupe 1 (membre exclu):4317548
4150119 | Groupe de modèles:Groupe 1 (membre exclu):4317548
4150121 | Groupe de modèles:Groupe 1 (membre exclu):4317548
4150123 | Groupe de modèles:Groupe 1 (membre exclu):4317548
4150125 | Groupe de modèles:Groupe 1 (membre exclu):4317548
4317487
5184692 | Groupe de modèles:Groupe 1 (membre exclu):4317548

# IfcColumn: Profil creux rectangulaire RHS:270x75RHS (25)
In: Rez de Rue Simon
Type - PredefinedType: COLUMN; Material: OMD_couleur facade-blanc perlé
Type - Pset_ColumnCommon - LoadBearing: yes
Pset_ColumnCommon - IsExternal: no; Reference: 270x75RHS
Pset_QuantityTakeOff - Reference: 270x75RHS; sets with these values: 2
Name (Profil creux rectangulaire RHS:270x75RHS:...)
3644188
3660602
3660603
3660605
3660606
3660608
3660610
3660611
3660613
3660615
3660616
3660618
3660620
3660622
3660623
3660625
3660627
3660628
3660630
3660633
3660635
3660637
3660642
4202234
4728317

# IfcCovering: Plafond composé:BA 13 (3)
Type - PredefinedType: CEILING
Type - Pset_CoveringCommon - TotalThickness: 0.06 m
Material: Faux-plafond - Trame 600 x 600 0.04 m, OMD_Peinture Blanche 0.02 m
Pset_CoveringCommon - Reference: BA 13; sets with these values: 2
Name (Plafond composé:BA 13:...) | In
3496792 | Rez de Rue Simon
4250821 | Rez de Rue Simon
4905058 | rez de rue -1.10m

# IfcCovering: Plafond composé:Dalles 60x120 (8)
In: rez de rue -1.10m
Type - PredefinedType: CEILING
Type - Pset_CoveringCommon - TotalThickness: 0.09 m
Material: Faux-plafond - Trame 600 x 600 0.04 m, Faux-plafond - Trame 600 x 1200 0.05 m
Pset_CoveringCommon - Reference: Dalles 60x120; sets with these values: 2
Name (Plafond composé:Dalles 60x120:...)
4283262
5461563
5464442
5465021
5465598
5465722
5467039
5468135

# IfcCovering: Plafond composé:Dalles 60x60 (14)
Type - PredefinedType: CEILING
Type - Pset_CoveringCommon - TotalThickness: 0.06 m
Material: Faux-plafond - Trame 600 x 600 0.04 m, Faux-plafond - Trame 600 x 600 0.02 m
Pset_CoveringCommon - Reference: Dalles 60x60; sets with these values: 2
Name (Plafond composé:Dalles 60x60:...) | In
3458178 | rez de rue -1.10m
3458186 | rez de rue -1.10m
3458194 | rez de rue -1.10m
3458202 | rez de rue -1.10m
4057207 | Rez de Rue Simon
4801863 | rez de rue -1.10m
4801895 | rez de rue -1.10m
4801965 | Rez de Rue Simon
4801999 | Rez de Rue Simon
5185527 | rez de rue -1.10m
5185545 | rez de rue -1.10m
5185554 | rez de rue -1.10m
5185564 | rez de rue -1.10m
5366421 | Rez de Rue Simon

# IfcCovering: Plafond composé:Dalles 60x60 NOIR (6)
Type - PredefinedType: CEILING
Type - Pset_CoveringCommon - TotalThickness: 0.06 m
Material: Faux-plafond - Trame 600 x 600 0.04 m, OMD_Faux-plafond - Trame 600 x 600NOIR 0.02 m
Pset_CoveringCommon - Reference: Dalles 60x60 NOIR; sets with these values: 2
Name (Plafond composé:Dalles 60x60 NOIR:...) | In
3458210 | rez de rue -1.10m
3458220 | rez de rue -1.10m
4180325 | Rez de Rue Simon
5443062 | Rez de Rue Simon
5447649 | Rez de Rue Simon
5470302 | Rez de Rue Simon

# IfcCovering: Plafond composé:FP- BA 13 (4)
In: rez de rue -1.10m
Type - PredefinedType: CEILING
Type - Pset_CoveringCommon - TotalThickness: 0.06 m
Material: Faux-plafond - Trame 600 x 600 0.04 m, OMD_Cloison 70mm 0.02 m
Pset_CoveringCommon - Reference: FP- BA 13; sets with these values: 2
Name (Plafond composé:FP- BA 13:...)
3543659
4802523
4802573
4802658

# IfcCovering: Plafond composé:FP- BA 13 coloré (4)
Type - PredefinedType: CEILING
Type - Pset_CoveringCommon - TotalThickness: 0.06 m
Material: Faux-plafond - Trame 600 x 600 0.04 m, OMD-plafond coloré 0.02 m
Pset_CoveringCommon - Reference: FP- BA 13 coloré; sets with these values: 2
Name (Plafond composé:FP- BA 13 coloré:...) | In
3575903 | rez de rue -1.10m
4905214 | rez de rue -1.10m
5443026 | Rez de Rue Simon
5447626 | Rez de Rue Simon

# IfcCovering: Plafond composé:isolation, Plafond composé:isolation:5310172
In: R-1
Type - PredefinedType: CEILING
Type - Pset_CoveringCommon - TotalThickness: 0.2 m
Material: Maçonnerie - Isolant 0.2 m
Pset_CoveringCommon - Reference: isolation; sets with these values: 2

# IfcCovering: Plafond composé:plafond cf 1h (8)
Type - PredefinedType: CEILING
Type - Pset_CoveringCommon - TotalThickness: 0.058 m
Material: Faux-plafond - Trame 600 x 600 0.04 m, OMD_Cloison 100mm CF1h 0.018 m
Pset_CoveringCommon - Reference: plafond cf 1h; sets with these values: 2
Name (Plafond composé:plafond cf 1h:...) | In
3458228 | rez de rue -1.10m
3822101 | R-1
4130755 | Rez de Rue Simon
4131322 | Rez de Rue Simon
4296097 | Rez de Rue Simon
4802701 | rez de rue -1.10m
5308122 | R-1
5382469 | R-1

# IfcCurtainWall: Mur-rideau:Menuiserie Ext (7)
Pset_CurtainWallCommon - IsExternal: yes; Reference: Menuiserie Ext
Pset_QuantityTakeOff - Reference: Menuiserie Ext
Name (Mur-rideau:Menuiserie Ext:...) | In
4317773 | Rez de Rue Simon
4317904 | Rez de Rue Simon
4318021 | Rez de Rue Simon
4323526 | Rez de Rue Simon
4323620 | Rez de Rue Simon
5327253 | 0- Rdc
5378885 | 0- Rdc

# IfcCurtainWall: Mur-rideau:Menuiserie Ext 1F+1OB VERTIC (265)
Pset_CurtainWallCommon - IsExternal: yes; Reference: Menuiserie Ext 1F+1OB VERTIC
Pset_QuantityTakeOff - Reference: Menuiserie Ext 1F+1OB VERTIC
Name (Mur-rideau:Menuiserie Ext 1F+1OB VERTIC:...) | In
3241975 | 0- Rdc
3242175 | 0- Rdc
3242195 | 0- Rdc
3242213 | 0- Rdc
3242231 | 0- Rdc
3242251 | 0- Rdc
3242273 | 0- Rdc
3242291 | 0- Rdc
3242362 | 0- Rdc
3242407 | 0- Rdc
3242425 | 0- Rdc
3242443 | 0- Rdc
3242463 | 0- Rdc
3242481 | 0- Rdc
3242501 | 0- Rdc
3242519 | 0- Rdc
3242624 | 0- Rdc
3242689 | 0- Rdc
3242709 | 0- Rdc
3242733 | 0- Rdc
3242753 | 0- Rdc
3242787 | 0- Rdc
3242807 | 0- Rdc
3242829 | 0- Rdc
3242851 | 0- Rdc
3242873 | 0- Rdc
3243067 | 0- Rdc
3243119 | 0- Rdc
3243141 | 0- Rdc
3243161 | 0- Rdc
3243179 | 0- Rdc
3243197 | 0- Rdc
3243217 | 0- Rdc
3243299 | 0- Rdc
3243334 | 0- Rdc
3243486 | 0- Rdc
3243620 | 0- Rdc
3243661 | 0- Rdc
3243679 | 0- Rdc
3243697 | 0- Rdc
3243715 | 0- Rdc
3243735 | 0- Rdc
3243753 | 0- Rdc
3243771 | 0- Rdc
3249596 | 0- Rdc
3258381 | Rez de Rue Simon
3258392 | Rez de Rue Simon
3258403 | Rez de Rue Simon
3258414 | Rez de Rue Simon
3258425 | Rez de Rue Simon
3258436 | Rez de Rue Simon
3258447 | Rez de Rue Simon
3258458 | Rez de Rue Simon
3258469 | Rez de Rue Simon
3258480 | Rez de Rue Simon
3258491 | Rez de Rue Simon
3258502 | Rez de Rue Simon
3258513 | Rez de Rue Simon
3258524 | Rez de Rue Simon
3258535 | Rez de Rue Simon
3258546 | Rez de Rue Simon
3258557 | Rez de Rue Simon
3258568 | Rez de Rue Simon
3258579 | Rez de Rue Simon
3258590 | Rez de Rue Simon
3259396 | Rez de Rue Simon
3259407 | Rez de Rue Simon
3259418 | Rez de Rue Simon
3259429 | Rez de Rue Simon
3259440 | Rez de Rue Simon
3259451 | Rez de Rue Simon
3259462 | Rez de Rue Simon
3259473 | Rez de Rue Simon
3260688 | 0- Rdc
3260741 | 0- Rdc
3261217 | Rez de Rue Simon
3261261 | Rez de Rue Simon
3261305 | Rez de Rue Simon
3263581 | Rez de Rue Simon
3264175 | 0- Rdc
3269864 | Rez de Rue Simon
3293092 | 0- Rdc
3294427 | 1-R+1
3294438 | 1-R+1
3294449 | 1-R+1
3294460 | 1-R+1
3294471 | 1-R+1
3294482 | 1-R+1
3294493 | 1-R+1
3294504 | 1-R+1
3294515 | 1-R+1
3294526 | 1-R+1
3294537 | 1-R+1
3294548 | 1-R+1
3294559 | 1-R+1
3294570 | 1-R+1
3294581 | 1-R+1
3294592 | 1-R+1
3294603 | 1-R+1
3294614 | 1-R+1
3294625 | 1-R+1
3294636 | 1-R+1
3294647 | 1-R+1
3294658 | 1-R+1
3294669 | 1-R+1
3294680 | 1-R+1
3294691 | 1-R+1
3294702 | 1-R+1
3294713 | 1-R+1
3294724 | 1-R+1
3294735 | 1-R+1
3294746 | 1-R+1
3294757 | 1-R+1
3294768 | 1-R+1
3294779 | 1-R+1
3294790 | 1-R+1
3294801 | 1-R+1
3294812 | 1-R+1
3294823 | 1-R+1
3294834 | 1-R+1
3294845 | 1-R+1
3294856 | 1-R+1
3294867 | 1-R+1
3294878 | 1-R+1
3294900 | 1-R+1
3295098 | 1-R+1
3295343 | 1-R+1
3295367 | 1-R+1
3295393 | 1-R+1
3295413 | 1-R+1
3295439 | 1-R+1
3295461 | 1-R+1
3295485 | 1-R+1
3296152 | 1-R+1
3296195 | 1-R+1
3296215 | 1-R+1
3296235 | 1-R+1
3296255 | 1-R+1
3296291 | 1-R+1
3296311 | 1-R+1
3296560 | 1-R+1
3296580 | 1-R+1
3297500 | 2-R+2
3297600 | 2-R+2
3297915 | 2-R+2
3298369 | 2-R+2
3298384 | 2-R+2
3298397 | 2-R+2
3298412 | 2-R+2
3298427 | 2-R+2
3298442 | 2-R+2
3298455 | 2-R+2
3298472 | 2-R+2
3298485 | 2-R+2
3298498 | 2-R+2
3298511 | 2-R+2
3298524 | 2-R+2
3298537 | 2-R+2
3298550 | 2-R+2
3298563 | 2-R+2
3298576 | 2-R+2
3298593 | 2-R+2
3298606 | 2-R+2
3298621 | 2-R+2
3298634 | 2-R+2
3298647 | 2-R+2
3299353 | 2-R+2
3299370 | 2-R+2
3299462 | 2-R+2
3299822 | 2-R+2
3299837 | 2-R+2
3299850 | 2-R+2
3299863 | 2-R+2
3299876 | 2-R+2
3299891 | 2-R+2
3299906 | 2-R+2
3299921 | 2-R+2
3299934 | 2-R+2
3299949 | 2-R+2
3299962 | 2-R+2
3299975 | 2-R+2
3299988 | 2-R+2
3300030 | 2-R+2
3300043 | 2-R+2
3300302 | 2-R+2
3300681 | 2-R+2
3300696 | 2-R+2
3300709 | 2-R+2
3300726 | 2-R+2
3300741 | 2-R+2
3300754 | 2-R+2
3300840 | 2-R+2
3300855 | 2-R+2
3300868 | 2-R+2
3300881 | 2-R+2
3300894 | 2-R+2
3300909 | 2-R+2
3300924 | 2-R+2
3300937 | 2-R+2
3300952 | 2-R+2
3301091 | 2-R+2
3301305 | 2-R+2
3301320 | 2-R+2
3301339 | 2-R+2
3301356 | 2-R+2
3301375 | 2-R+2
3301388 | 2-R+2
3301403 | 2-R+2
3301418 | 2-R+2
3301433 | 2-R+2
3301448 | 2-R+2
3301461 | 2-R+2
3301478 | 2-R+2
3301495 | 2-R+2
3301658 | 2-R+2
3301737 | 2-R+2
3301750 | 2-R+2
3301763 | 2-R+2
3301776 | 2-R+2
3301789 | 2-R+2
3301802 | 2-R+2
3301815 | 2-R+2
3301830 | 2-R+2
3301845 | 2-R+2
3301858 | 2-R+2
3301871 | 2-R+2
3302228 | 2-R+2
3302241 | 2-R+2
3302254 | 2-R+2
3302267 | 2-R+2
3302535 | 2-R+2
3302804 | 2-R+2
3302819 | 2-R+2
3302832 | 2-R+2
3302853 | 2-R+2
3302868 | 2-R+2
3302881 | 2-R+2
3302898 | 2-R+2
3302911 | 2-R+2
3302928 | 2-R+2
3302941 | 2-R+2
3303133 | 2-R+2
3303148 | 2-R+2
3303163 | 2-R+2
3303178 | 2-R+2
3303199 | 2-R+2
3303212 | 2-R+2
3303225 | 2-R+2
3303240 | 2-R+2
3303253 | 2-R+2
3303490 | 2-R+2
3303505 | 2-R+2
3303518 | 2-R+2
3303539 | 2-R+2
3303558 | 2-R+2
3303571 | 2-R+2
3303584 | 2-R+2
3303599 | 2-R+2
3303616 | 2-R+2
3303629 | 2-R+2
3303859 | 2-R+2
3303878 | 2-R+2
4667425 | 0- Rdc
4667592 | 1-R+1
4667603 | 1-R+1

# IfcCurtainWall: Mur-rideau:Menuiserie Ext 2OF+1F VERTIC (7)
In: 0- Rdc
Pset_CurtainWallCommon - IsExternal: yes; Reference: Menuiserie Ext 2OF+1F VERTIC
Pset_QuantityTakeOff - Reference: Menuiserie Ext 2OF+1F VERTIC
Name (Mur-rideau:Menuiserie Ext 2OF+1F VERTIC:...)
3243949
3249100
3249368
3249401
3249438
3249469
3249506

# IfcCurtainWall: Mur-rideau:Menuiserie Int (8)
Pset_CurtainWallCommon - IsExternal: yes; Reference: Menuiserie Int
Pset_QuantityTakeOff - Reference: Menuiserie Int
Name (Mur-rideau:Menuiserie Int:...) | In
3665528 | rez de rue -1.10m
4051815 | Rez de Rue Simon
4056886 | Rez de Rue Simon
4056984 | Rez de Rue Simon
4140116 | rez de rue -1.10m
4279754 | rez de rue -1.10m
4723576 | rez de rue -1.10m
4723995 | rez de rue -1.10m

# IfcCurtainWall: Mur-rideau:Trappe (2)
In: R-1
Pset_CurtainWallCommon - IsExternal: no; Reference: Trappe
Pset_QuantityTakeOff - Reference: Trappe
Name (Mur-rideau:Trappe:...)
5333557
5334329

# IfcDistributionPort (40)
Description: Flow
Name | FlowDirection
OutPort_4061635_1 | SOURCE
InPort_4061635_2 | SINK
InPort_4061635_3 | SINK
OutPort_4061897_1 | SOURCE
InPort_4061897_2 | SINK
InPort_4061897_3 | SINK
InPort_4070678_2 | SINK
OutPort_4070678_3 | SOURCE
InPort_4070740_2 | SINK
OutPort_4070740_3 | SOURCE
InPort_4070748_2 | SINK
OutPort_4070748_3 | SOURCE
InPort_4070756_2 | SINK
OutPort_4070756_3 | SOURCE
Port_4178981_1 | SOURCEANDSINK
Port_4178981_2 | SOURCEANDSINK
Port_4179306_1 | SOURCEANDSINK
Port_4179306_2 | SOURCEANDSINK
Port_4179318_1 | SOURCEANDSINK
Port_4179318_2 | SOURCEANDSINK
OutPort_4230428_1 | SOURCE
InPort_4230428_2 | SINK
InPort_4230428_3 | SINK
OutPort_4230434_1 | SOURCE
InPort_4230434_2 | SINK
InPort_4230434_3 | SINK
OutPort_4234542_1 | SOURCE
InPort_4234542_2 | SINK
InPort_4234542_3 | SINK
OutPort_4234543_1 | SOURCE
InPort_4234543_2 | SINK
InPort_4234543_3 | SINK
Port_5448377_1 | SOURCEANDSINK
Port_5448377_2 | SOURCEANDSINK
Port_5448378_1 | SOURCEANDSINK
Port_5448378_2 | SOURCEANDSINK
Port_5448379_1 | SOURCEANDSINK
Port_5448379_2 | SOURCEANDSINK
Port_5448380_1 | SOURCEANDSINK
Port_5448380_2 | SOURCEANDSINK

# IfcDoor: Double (T):1.63m x 2.04m (2)
In: rez de rue -1.10m
Type - OperationType: DOUBLE_DOOR_SINGLE_SWING; ParameterTakesPrecedence: no; Sizeable: no; Material: Porte - Poignée, OMD_BLEU T1 23 25-SIKKKENS
Type - Double (T):1.63m x 2.04m:3547414:1 - PanelOperation: SWINGING
Type - Pset_DoorCommon - ThermalTransmittance: 3.6886 kg/K/s3
OverallHeight: 2.075 m; OverallWidth: 1.7 m
Pset_DoorCommon - IsExternal: no; Reference: 1.63m x 2.04m
Pset_QuantityTakeOff - Reference: 1.63m x 2.04m
Name (Double (T):1.63m x 2.04m:...)
3547414
4138939

# IfcDoor: Double (T):1.83m x 2.04m (2)
In: rez de rue -1.10m
Type - OperationType: DOUBLE_DOOR_SINGLE_SWING; ParameterTakesPrecedence: no; Sizeable: no; Material: Porte - Poignée, Porte - Cadre, Porte - Panneau
Type - Double (T):1.83m x 2.04m:3694244:1 - PanelOperation: SWINGING
Type - Pset_DoorCommon - ThermalTransmittance: 3.6886 kg/K/s3
OverallHeight: 2.075 m; OverallWidth: 1.9 m
Pset_DoorCommon - IsExternal: no; Reference: 1.83m x 2.04m
Pset_QuantityTakeOff - Reference: 1.83m x 2.04m
Name (Double (T):1.83m x 2.04m:...)
3694244
3694307

# IfcDoor: Grz_Garage sectionnelle:porte sectionnelle 3.6X3, Grz_Garage sectionnelle:porte sectionnelle 3.6X3:4898337
In: Rez de Rue Simon
Type - OperationType: ROLLINGUP; ParameterTakesPrecedence: no; Sizeable: no; Material: Peinture - Grise
Type - Grz_Garage sectionnelle:porte sectionnelle 3.6X3:4898337:1 - PanelOperation: ROLLINGUP
Type - Pset_DoorCommon - ThermalTransmittance: 3.7021 kg/K/s3
OverallHeight: 2.29 m; OverallWidth: 3.62 m
Pset_DoorCommon - IsExternal: yes; Reference: porte sectionnelle 3.6X3
Pset_QuantityTakeOff - Reference: porte sectionnelle 3.6X3

# IfcDoor: Grz_Placard 1V:53x204, Grz_Placard 1V:53x204:3265552
In: Rez de Rue Simon
Type - OperationType: DOUBLE_DOOR_SINGLE_SWING; ParameterTakesPrecedence: no; Sizeable: no; Material: OMD_BLEU T1 23 25-SIKKKENS
Type - Grz_Placard 1V:53x204:3265552:1 - PanelOperation: SWINGING
Type - Pset_DoorCommon - ThermalTransmittance: 3.6886 kg/K/s3
OverallHeight: 2.075 m; OverallWidth: 0.53 m
Pset_DoorCommon - IsExternal: no; Reference: 53x204
Pset_QuantityTakeOff - Reference: 53x204

# IfcDoor: Grz_Placard 1V:80X204 (4)
Type - OperationType: DOUBLE_DOOR_SINGLE_SWING; ParameterTakesPrecedence: no; Sizeable: no; Material: Porte - Panneau, Porte - Cadre
Type - Grz_Placard 1V:80X204:3237916:1 - PanelOperation: SWINGING
Type - Pset_DoorCommon - ThermalTransmittance: 3.6886 kg/K/s3
OverallHeight: 2.075 m; OverallWidth: 0.8 m
Pset_DoorCommon - IsExternal: no; Reference: 80X204
Pset_QuantityTakeOff - Reference: 80X204
Name (Grz_Placard 1V:80X204:...) | In
3237916 | 0- Rdc
3237959 | 0- Rdc
3257746 | Rez de Rue Simon
3257783 | Rez de Rue Simon

# IfcDoor: Grz_Placard 1V:80X204 (2)
In: 0- Rdc
Type - OperationType: DOUBLE_DOOR_SINGLE_SWING; ParameterTakesPrecedence: no; Sizeable: no; Material: Porte - Panneau, Porte - Cadre
Type - Grz_Placard 1V:80X204:3238035:1 - PanelOperation: SWINGING
Type - Pset_DoorCommon - ThermalTransmittance: 3.6886 kg/K/s3
OverallHeight: 2.075 m; OverallWidth: 0.8 m
Pset_DoorCommon - IsExternal: no; Reference: 80X204
Pset_QuantityTakeOff - Reference: 80X204
Name (Grz_Placard 1V:80X204:...)
3238035
3238078

# IfcDoor: Grz_Placard 1V:80X204, Grz_Placard 1V:80X204:5340598
In: 0- Rdc
Type - OperationType: DOUBLE_DOOR_SINGLE_SWING; ParameterTakesPrecedence: no; Sizeable: no; Material: Porte - Panneau, Porte - Cadre
Type - Grz_Placard 1V:80X204:5340598:1 - PanelOperation: SWINGING
Type - Pset_DoorCommon - ThermalTransmittance: 3.6886 kg/K/s3
OverallHeight: 2.075 m; OverallWidth: 0.8 m
Pset_DoorCommon - IsExternal: no; Reference: 80X204
Pset_QuantityTakeOff - Reference: 80X204

# IfcDoor: Grz_Placard 1V:80X204 (2)
Type - OperationType: DOUBLE_DOOR_SINGLE_SWING; ParameterTakesPrecedence: no; Sizeable: no; Material: Porte - Panneau, Porte - Cadre
Type - Grz_Placard 1V:80X204:5373717:1 - PanelOperation: SWINGING
Type - Pset_DoorCommon - ThermalTransmittance: 3.6886 kg/K/s3
OverallHeight: 2.075 m; OverallWidth: 0.8 m
Pset_DoorCommon - IsExternal: no; Reference: 80X204
Pset_QuantityTakeOff - Reference: 80X204
Name (Grz_Placard 1V:80X204:...) | In
5373717 | 1-R+1
5373759 | 2-R+2

# IfcDoor: Grz_Placard 2V:140x204, Grz_Placard 2V:140x204:3265580
In: Rez de Rue Simon
Type - OperationType: DOUBLE_DOOR_SINGLE_SWING; ParameterTakesPrecedence: no; Sizeable: no; Material: OMD_Peinture mur
Type - Grz_Placard 2V:140x204:3265580:1 - PanelOperation: SWINGING
Type - Pset_DoorCommon - ThermalTransmittance: 3.6886 kg/K/s3
OverallHeight: 2.075 m; OverallWidth: 1.4 m
Pset_DoorCommon - IsExternal: no; Reference: 140x204
Pset_QuantityTakeOff - Reference: 140x204

# IfcDoor: Grz_Placard 2V:140x204, Grz_Placard 2V:140x204:5366304
In: Rez de Rue Simon
Type - OperationType: DOUBLE_DOOR_SINGLE_SWING; ParameterTakesPrecedence: no; Sizeable: no; Material: OMD_Peinture mur
Type - Grz_Placard 2V:140x204:5366304:1 - PanelOperation: SWINGING
Type - Pset_DoorCommon - ThermalTransmittance: 3.6886 kg/K/s3
OverallHeight: 2.075 m; OverallWidth: 1.4 m
Pset_DoorCommon - IsExternal: no; Reference: 140x204
Pset_QuantityTakeOff - Reference: 140x204

# IfcDoor: Grz_porte 1V recouvrement 30°:80x204 (2)
In: Rez de Rue Simon
Type - OperationType: SINGLE_SWING_LEFT; ParameterTakesPrecedence: no; Sizeable: no; Material: Porte - Poignée, Porte - Cadre, Porte - Panneau
Type - Grz_porte 1V recouvrement 30°:80x204:3375352:1 - PanelOperation: SWINGING
Type - Pset_DoorCommon - ThermalTransmittance: 3.7021 kg/K/s3
OverallHeight: 2.075 m; OverallWidth: 0.87 m
Pset_DoorCommon - IsExternal: no; Reference: 80x204
Pset_QuantityTakeOff - Reference: 80x204
Name (Grz_porte 1V recouvrement 30°:80x204:...)
3375352
3375361

# IfcDoor: Grz_porte 1V recouvrement 30°:80x204, Grz_porte 1V recouvrement 30°:80x204:4236965
In: rez de rue -1.10m
Type - OperationType: SINGLE_SWING_LEFT; ParameterTakesPrecedence: no; Sizeable: no; Material: Porte - Poignée, Porte - Cadre, Porte - Panneau
Type - Grz_porte 1V recouvrement 30°:80x204:4236965:1 - PanelOperation: SWINGING
Type - Pset_DoorCommon - ThermalTransmittance: 3.7021 kg/K/s3
OverallHeight: 2.075 m; OverallWidth: 0.87 m
Pset_DoorCommon - IsExternal: no; Reference: 80x204
Pset_QuantityTakeOff - Reference: 80x204

# IfcDoor: Grz_porte 1V recouvrement 30°:80x204 (2)
In: Rez de Rue Simon
Type - OperationType: SINGLE_SWING_RIGHT; ParameterTakesPrecedence: no; Sizeable: no; Material: Porte - Poignée, OMD_RAL1032
Type - Grz_porte 1V recouvrement 30°:80x204:3326648:1 - PanelOperation: SWINGING
Type - Pset_DoorCommon - ThermalTransmittance: 3.7021 kg/K/s3
OverallHeight: 2.075 m; OverallWidth: 0.87 m
Pset_DoorCommon - IsExternal: no; Reference: 80x204
Pset_QuantityTakeOff - Reference: 80x204
Name (Grz_porte 1V recouvrement 30°:80x204:...)
3326648
3375339

# IfcDoor: Grz_porte 1V recouvrement 30°:80x204, Grz_porte 1V recouvrement 30°:80x204:4099117
In: rez de rue -1.10m
Type - OperationType: SINGLE_SWING_RIGHT; ParameterTakesPrecedence: no; Sizeable: no; Material: Porte - Poignée, OMD_RAL1032
Type - Grz_porte 1V recouvrement 30°:80x204:4099117:1 - PanelOperation: SWINGING
Type - Pset_DoorCommon - ThermalTransmittance: 3.7021 kg/K/s3
OverallHeight: 2.075 m; OverallWidth: 0.87 m
Pset_DoorCommon - IsExternal: no; Reference: 80x204
Pset_QuantityTakeOff - Reference: 80x204

# IfcDoor: Grz_porte 1V recouvrement 30°:80x204, Grz_porte 1V recouvrement 30°:80x204:3375360
In: Rez de Rue Simon
Type - OperationType: SINGLE_SWING_RIGHT; ParameterTakesPrecedence: no; Sizeable: no; Material: Porte - Poignée, Porte - Cadre, Porte - Panneau
Type - Grz_porte 1V recouvrement 30°:80x204:3375360:1 - PanelOperation: SWINGING
Type - Pset_DoorCommon - ThermalTransmittance: 3.7021 kg/K/s3
OverallHeight: 2.075 m; OverallWidth: 0.87 m
Pset_DoorCommon - IsExternal: no; Reference: 80x204
Pset_QuantityTakeOff - Reference: 80x204

# IfcDoor: Grz_porte 1V recouvrement 30°:93x204 (2)
In: rez de rue -1.10m
Type - OperationType: SINGLE_SWING_LEFT; ParameterTakesPrecedence: no; Sizeable: no; Material: Porte - Poignée, OMD_RAL1032
Type - Grz_porte 1V recouvrement 30°:93x204:3336251:1 - PanelOperation: SWINGING
Type - Pset_DoorCommon - ThermalTransmittance: 3.7021 kg/K/s3
OverallHeight: 2.075 m; OverallWidth: 1 m
Pset_DoorCommon - IsExternal: no; Reference: 93x204
Pset_QuantityTakeOff - Reference: 93x204
Name (Grz_porte 1V recouvrement 30°:93x204:...)
3336251
3428447

# IfcDoor: Grz_porte 1V recouvrement 30°:93x204, Grz_porte 1V recouvrement 30°:93x204:4233025
In: rez de rue -1.10m
Type - OperationType: SINGLE_SWING_LEFT; ParameterTakesPrecedence: no; Sizeable: no; Material: Porte - Poignée, Porte - Cadre, Porte - Panneau
Type - Grz_porte 1V recouvrement 30°:93x204:4233025:1 - PanelOperation: SWINGING
Type - Pset_DoorCommon - ThermalTransmittance: 3.7021 kg/K/s3
OverallHeight: 2.075 m; OverallWidth: 1 m
Pset_DoorCommon - IsExternal: no; Reference: 93x204
Pset_QuantityTakeOff - Reference: 93x204

# IfcDoor: Grz_porte 1V recouvrement 30°:93x204 (2)
In: rez de rue -1.10m
Type - OperationType: SINGLE_SWING_RIGHT; ParameterTakesPrecedence: no; Sizeable: no; Material: Porte - Poignée, OMD_RAL1032
Type - Grz_porte 1V recouvrement 30°:93x204:3336307:1 - PanelOperation: SWINGING
Type - Pset_DoorCommon - ThermalTransmittance: 3.7021 kg/K/s3
OverallHeight: 2.075 m; OverallWidth: 1 m
Pset_DoorCommon - IsExternal: no; Reference: 93x204
Pset_QuantityTakeOff - Reference: 93x204
Name (Grz_porte 1V recouvrement 30°:93x204:...)
3336307
3375894

# IfcDoor: Grz_porte 1V recouvrement 30°:93x204, Grz_porte 1V recouvrement 30°:93x204:3375354
In: Rez de Rue Simon
Type - OperationType: SINGLE_SWING_RIGHT; ParameterTakesPrecedence: no; Sizeable: no; Material: Porte - Poignée, OMD_RAL1032
Type - Grz_porte 1V recouvrement 30°:93x204:3375354:1 - PanelOperation: SWINGING
Type - Pset_DoorCommon - ThermalTransmittance: 3.7021 kg/K/s3
OverallHeight: 2.075 m; OverallWidth: 1 m
Pset_DoorCommon - IsExternal: no; Reference: 93x204
Pset_QuantityTakeOff - Reference: 93x204

# IfcDoor: Grz_porte 1V recouvrement 30°:93x204, Grz_porte 1V recouvrement 30°:93x204:4156472
In: rez de rue -1.10m
Type - OperationType: SINGLE_SWING_RIGHT; ParameterTakesPrecedence: no; Sizeable: no; Material: Porte - Poignée, Porte - Cadre, Porte - Panneau
Type - Grz_porte 1V recouvrement 30°:93x204:4156472:1 - PanelOperation: SWINGING
Type - Pset_DoorCommon - ThermalTransmittance: 3.7021 kg/K/s3
OverallHeight: 2.075 m; OverallWidth: 1 m
Pset_DoorCommon - IsExternal: no; Reference: 93x204
Pset_QuantityTakeOff - Reference: 93x204

# IfcDoor: OMD_1PP:GRZ_simple 2, OMD_1PP:GRZ_simple 2:4140117
In: rez de rue -1.10m
Type - OperationType: SINGLE_SWING_RIGHT; ParameterTakesPrecedence: no; Sizeable: no; Material: Porte MR - Poignée, Porte MR - Panneau
Type - OMD_1PP:GRZ_simple 2:4140117:1 - PanelOperation: SWINGING
OverallHeight: 2.035 m; OverallWidth: 1.08135 m
Pset_DoorCommon - IsExternal: yes; Reference: GRZ_simple 2
Pset_QuantityTakeOff - Reference: GRZ_simple 2

# IfcDoor: OMD_1PP:GRZ_simple 2, OMD_1PP:GRZ_simple 2:4722900
In: rez de rue -1.10m
Type - OperationType: SINGLE_SWING_RIGHT; ParameterTakesPrecedence: no; Sizeable: no; Material: Porte MR - Poignée, Porte MR - Panneau
Type - OMD_1PP:GRZ_simple 2:4722900:1 - PanelOperation: SWINGING
OverallHeight: 2.035 m; OverallWidth: 1.08135 m
Pset_DoorCommon - IsExternal: yes; Reference: GRZ_simple 2
Pset_QuantityTakeOff - Reference: GRZ_simple 2

# IfcDoor: OMD_1PP:GRZ_simple 2, OMD_1PP:GRZ_simple 2:4723619
In: rez de rue -1.10m
Type - OperationType: SINGLE_SWING_RIGHT; ParameterTakesPrecedence: no; Sizeable: no; Material: Porte MR - Poignée, Porte MR - Panneau
Type - OMD_1PP:GRZ_simple 2:4723619:1 - PanelOperation: SWINGING
OverallHeight: 2.035 m; OverallWidth: 1.08135 m
Pset_DoorCommon - IsExternal: yes; Reference: GRZ_simple 2
Pset_QuantityTakeOff - Reference: GRZ_simple 2

# IfcDoor: OMD_1PP:GRZ_simple 2, OMD_1PP:GRZ_simple 2:4724040
In: rez de rue -1.10m
Type - OperationType: SINGLE_SWING_RIGHT; ParameterTakesPrecedence: no; Sizeable: no; Material: Porte MR - Poignée, Porte MR - Panneau
Type - OMD_1PP:GRZ_simple 2:4724040:1 - PanelOperation: SWINGING
OverallHeight: 2.035 m; OverallWidth: 1.08135 m
Pset_DoorCommon - IsExternal: yes; Reference: GRZ_simple 2
Pset_QuantityTakeOff - Reference: GRZ_simple 2

# IfcDoor: OMD_1PV 2V:PV 2V 90+90 (3)
In: Rez de Rue Simon
Type - ParameterTakesPrecedence: no; Sizeable: no; Material: Porte - Poignée, Verre, OMD_Aluminium Men Ext
OverallHeight: 2.275 m
Pset_DoorCommon - IsExternal: no; Reference: PV 2V 90+90
Pset_QuantityTakeOff - Reference: PV 2V 90+90
Name (OMD_1PV 2V:PV 2V 90+90:...) | OverallWidth (m)
3261242 | 1.88365
3261286 | 1.88365
3261693 | 1.90615

# IfcDoor: OMD_1PV 2V:PV 2V 90+90 ANTHRACITE, OMD_1PV 2V:PV 2V 90+90 ANTHRACITE:5331601
In: rez de rue -1.10m
Type - ParameterTakesPrecedence: no; Sizeable: no; Material: Porte - Poignée, Verre, OMD_Aluminium Men Ext
OverallHeight: 2.035 m; OverallWidth: 1.85625 m
Pset_DoorCommon - IsExternal: no; Reference: PV 2V 90+90 ANTHRACITE
Pset_QuantityTakeOff - Reference: PV 2V 90+90 ANTHRACITE

# IfcDoor: OMD_Porte 1V tunnel:60X204 (2)
In: Rez de Rue Simon
Type - ParameterTakesPrecedence: no; Sizeable: no; Material: Porte - Poignée, OMD_Peinture mur, OMD_Bois
OverallHeight: 2.085 m; OverallWidth: 0.735 m
Pset_DoorCommon - IsExternal: no; Reference: 60X204
Pset_QuantityTakeOff - Reference: 60X204
Name (OMD_Porte 1V tunnel:60X204:...)
3256344
3256375

# IfcDoor: OMD_Porte 1V tunnel:70X204 (4)
Type - ParameterTakesPrecedence: no; Sizeable: no; Material: Porte - Poignée, OMD_Peinture mur, OMD_BLEU T1 23 25-SIKKKENS
OverallHeight: 2.085 m; OverallWidth: 0.835 m
Pset_DoorCommon - IsExternal: no; Reference: 70X204
Pset_QuantityTakeOff - Reference: 70X204
Name (OMD_Porte 1V tunnel:70X204:...) | In
3236455 | 0- Rdc
3236512 | 0- Rdc
3236555 | 0- Rdc
5335770 | Rez de Rue Simon

# IfcDoor: OMD_Porte 1V tunnel:80x204 (73)
Type - ParameterTakesPrecedence: no; Sizeable: no; Material: Porte - Poignée, OMD_Peinture mur, OMD_Bois
OverallHeight: 2.085 m; OverallWidth: 0.935 m
Pset_DoorCommon - IsExternal: no; Reference: 80x204
Pset_QuantityTakeOff - Reference: 80x204
Name (OMD_Porte 1V tunnel:80x204:...) | In
3231482 | 0- Rdc
3231591 | 0- Rdc
3231644 | 0- Rdc
3231686 | 0- Rdc
3231764 | 0- Rdc
3231793 | 0- Rdc
3231849 | 0- Rdc
3231909 | 0- Rdc
3231947 | 0- Rdc
3231995 | 0- Rdc
3232034 | 0- Rdc
3232161 | 0- Rdc
3232368 | 0- Rdc
3232412 | 0- Rdc
3232451 | 0- Rdc
3232497 | 0- Rdc
3232786 | 0- Rdc
3232856 | 0- Rdc
3233002 | 0- Rdc
3233087 | 0- Rdc
3233126 | 0- Rdc
3233646 | 0- Rdc
3233674 | 0- Rdc
3233712 | 0- Rdc
3233755 | 0- Rdc
3233830 | 0- Rdc
3233864 | 0- Rdc
3234995 | 0- Rdc
3236409 | 0- Rdc
3238131 | 0- Rdc
3238283 | 0- Rdc
3238304 | 0- Rdc
3238455 | 0- Rdc
3238961 | 0- Rdc
3239001 | 0- Rdc
3239041 | 0- Rdc
3239080 | 0- Rdc
3239109 | 0- Rdc
3239213 | 0- Rdc
3239439 | 0- Rdc
3255115 | Rez de Rue Simon
3256236 | Rez de Rue Simon
3256272 | Rez de Rue Simon
3256708 | Rez de Rue Simon
3257045 | Rez de Rue Simon
3257151 | Rez de Rue Simon
3257261 | Rez de Rue Simon
3257412 | Rez de Rue Simon
3257467 | Rez de Rue Simon
3257583 | Rez de Rue Simon
3259892 | Rez de Rue Simon
3267236 | Rez de Rue Simon
3268249 | Rez de Rue Simon
3268376 | Rez de Rue Simon
3268453 | Rez de Rue Simon
3268461 | Rez de Rue Simon
3268469 | Rez de Rue Simon
3268528 | Rez de Rue Simon
3268536 | Rez de Rue Simon
3268544 | Rez de Rue Simon
3268777 | Rez de Rue Simon
3269565 | Rez de Rue Simon
3269628 | Rez de Rue Simon
3269706 | Rez de Rue Simon
3273387 | R-1
3277082 | R-1
3277709 | R-1
3277743 | R-1
3277777 | R-1
3277820 | R-1
3277851 | R-1
3277902 | R-1
3293674 | 0- Rdc

# IfcDoor: OMD_Porte 1V tunnel:90x204, OMD_Porte 1V tunnel:90x204:3319910
In: Rez de Rue Simon
Type - ParameterTakesPrecedence: no; Sizeable: no; Material: Porte - Poignée, OMD_Peinture mur, OMD_Bois
OverallHeight: 2.085 m; OverallWidth: 1.035 m
Pset_DoorCommon - IsExternal: no; Reference: 90x204
Pset_QuantityTakeOff - Reference: 90x204

# IfcDoor: OMD_Porte 2V tunnel:136x204 (2)
Type - ParameterTakesPrecedence: no; Sizeable: no; Material: <Unnamed>, Porte - Poignée, OMD_Bois
OverallHeight: 2.085 m; OverallWidth: 1.505 m
Pset_DoorCommon - IsExternal: yes; Reference: 136x204
Pset_QuantityTakeOff - Reference: 136x204
Name (OMD_Porte 2V tunnel:136x204:...) | In
3230876 | 0- Rdc
3296981 | 1-R+1

# IfcDoor: OMD_Porte 2V tunnel:140x204 (21)
Type - ParameterTakesPrecedence: no; Sizeable: no; Material: <Unnamed>, Porte - Poignée, OMD_Bois
OverallHeight: 2.085 m; OverallWidth: 1.55 m
Pset_DoorCommon - IsExternal: yes; Reference: 140x204
Pset_QuantityTakeOff - Reference: 140x204
Name (OMD_Porte 2V tunnel:140x204:...) | In
3232291 | 0- Rdc
3232753 | 0- Rdc
3234919 | 0- Rdc
3238388 | 0- Rdc
3238504 | 0- Rdc
3238674 | 0- Rdc
3239482 | 0- Rdc
3251587 | Rez de Rue Simon
3254864 | Rez de Rue Simon
3255027 | Rez de Rue Simon
3256571 | Rez de Rue Simon
3256848 | Rez de Rue Simon
3259964 | Rez de Rue Simon
3260093 | Rez de Rue Simon
3268039 | Rez de Rue Simon
3268616 | Rez de Rue Simon
3274242 | R-1
3277154 | R-1
3292890 | Rez de Rue Simon
3295109 | 1-R+1
3296987 | 1-R+1

# IfcDoor: OMD_Porte 2V tunnel:140x204 +occulus (4)
In: rez de rue -1.10m
Type - ParameterTakesPrecedence: no; Sizeable: no; Material: <Unnamed>, Porte - Poignée, Verre, OMD_RAL5023
OverallHeight: 2.085 m; OverallWidth: 1.55 m
Pset_DoorCommon - IsExternal: yes; Reference: 140x204 +occulus
Pset_QuantityTakeOff - Reference: 140x204 +occulus
Name (OMD_Porte 2V tunnel:140x204 +occulus:...)
3329272
3377111
3455930
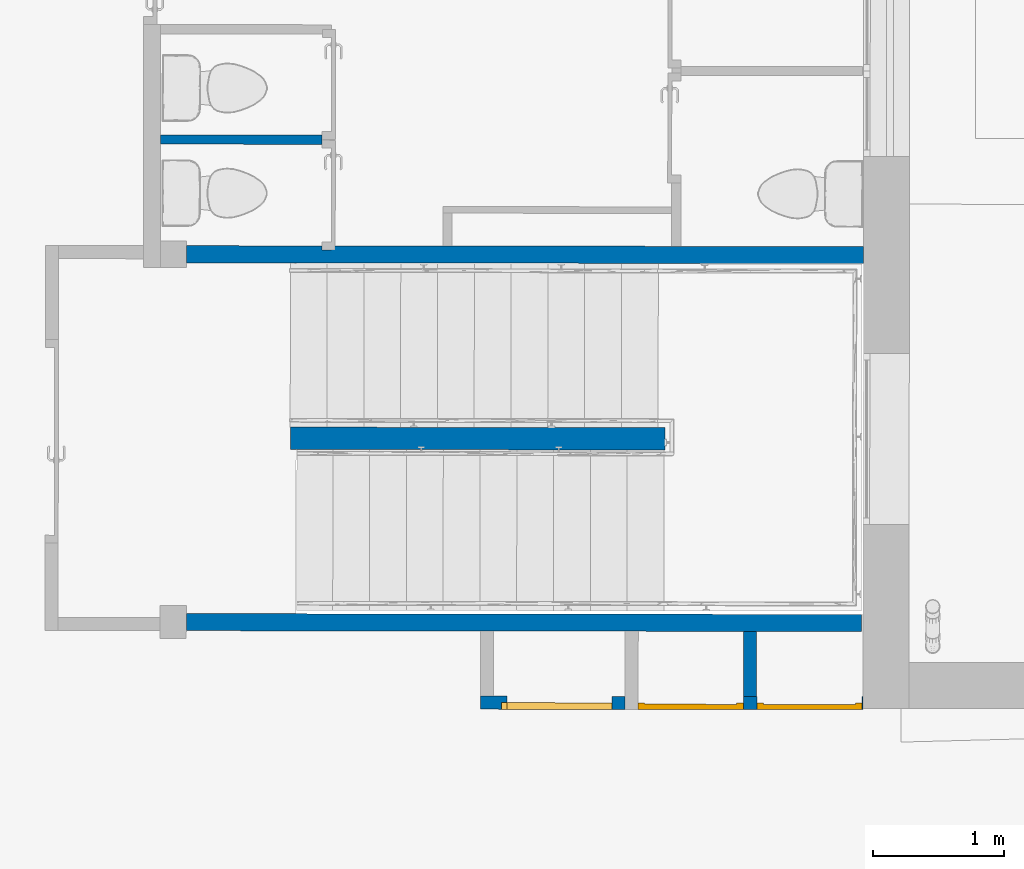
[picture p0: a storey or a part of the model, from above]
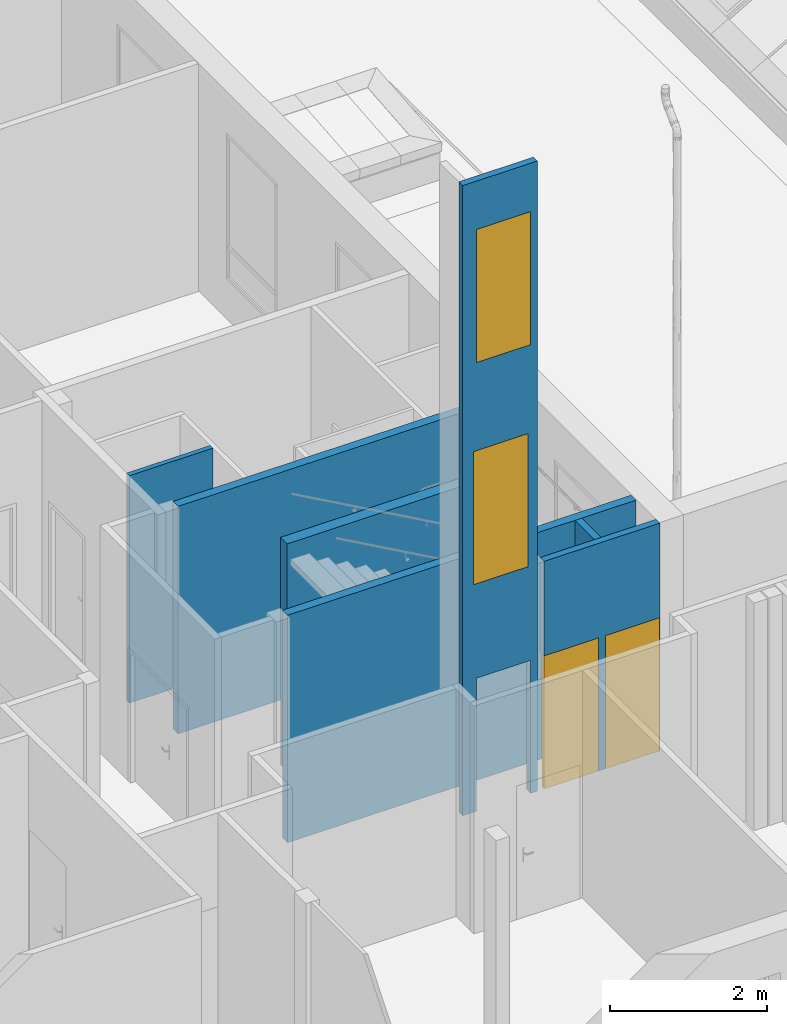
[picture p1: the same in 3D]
Properties of the parts of a building model (IFC2X3), part 2 of 4

# IfcDoor: OMD_Porte 2V tunnel:140x204 +occulus (4)
Name (OMD_Porte 2V tunnel:140x204 +occulus:...)
4138959

# IfcDoor: OMD_Porte 2V tunnel:double 140x204 (2)
Type - ParameterTakesPrecedence: no; Sizeable: no; Material: <Unnamed>, Porte - Poignée, OMD_Bois
OverallHeight: 2.085 m; OverallWidth: 1.55 m
Pset_DoorCommon - IsExternal: yes; Reference: double 140x204
Pset_QuantityTakeOff - Reference: double 140x204
Name (OMD_Porte 2V tunnel:double 140x204:...) | In
3229246 | 0- Rdc
3296977 | 1-R+1

# IfcDoor: OMD_Porte 2V tunnel:double 160x204, OMD_Porte 2V tunnel:double 160x204:3274028
In: R-1
Type - ParameterTakesPrecedence: no; Sizeable: no; Material: <Unnamed>, Porte - Poignée, OMD_Bois
OverallHeight: 2.085 m; OverallWidth: 1.75 m
Pset_DoorCommon - IsExternal: yes; Reference: double 160x204
Pset_QuantityTakeOff - Reference: double 160x204

# IfcDoor: OMD_Porte 2V tunnel:double 180x204 (2)
Type - ParameterTakesPrecedence: no; Sizeable: no; Material: <Unnamed>, Porte - Poignée, OMD_Bois
OverallHeight: 2.085 m; OverallWidth: 1.95 m
Pset_DoorCommon - IsExternal: yes; Reference: double 180x204
Pset_QuantityTakeOff - Reference: double 180x204
Name (OMD_Porte 2V tunnel:double 180x204:...) | In
3268940 | Rez de Rue Simon
3293616 | 0- Rdc

# IfcDoor: Tierce (R):1.20m x 2.04m (2)
In: R-1
Type - ParameterTakesPrecedence: no; Sizeable: no; Material: Porte - Poignée, OMD_RAL1032
Type - Pset_DoorCommon - ThermalTransmittance: 3.7021 kg/K/s3
OverallHeight: 2.075 m; OverallWidth: 1.27 m
Pset_DoorCommon - IsExternal: no; Reference: 1.20m x 2.04m
Pset_QuantityTakeOff - Reference: 1.20m x 2.04m
Name (Tierce (R):1.20m x 2.04m:...)
4204126
4204151

# IfcDoor: Tierce (R):1.43m x 2.04m (2)
In: Rez de Rue Simon
Type - ParameterTakesPrecedence: no; Sizeable: no; Material: Porte - Poignée, OMD_RAL1032
Type - Pset_DoorCommon - ThermalTransmittance: 3.7021 kg/K/s3
OverallHeight: 2.075 m; OverallWidth: 1.5 m
Pset_DoorCommon - IsExternal: no; Reference: 1.43m x 2.04m
Pset_QuantityTakeOff - Reference: 1.43m x 2.04m
Name (Tierce (R):1.43m x 2.04m:...)
3469239
5334413

# IfcFlowTerminal: 400_74_Geberit_duofix_H112_sigma_12cm_adjustable_8cm:400_74_Geberit_Duofix_H112_Sigma_12_cm_adjustable_8_cm (4)
In: Rez de Rue Simon
Type - Material: <Unnamed>, Laminate, Ivory, Matte, Laminate, Navy, Plastic, Opaque Black, Steel, Paint Finish, Blue
Type - Pset_ManufacturerTypeInformation - Manufacturer: Geberit
Pset_DistributionFlowElementCommon - Reference: 400_74_Geberit_Duofix_H112_Sigma_12_cm_adjustable_8_cm; sets with these values: 2
Name (400_74_Geberit_duofix_H112_sigma_12cm_adjustable_8cm:400_74_Geberit_Duofix_H112_Sigma_12_cm_adjustable_8_cm:...)
4070678
4070740
4070748
4070756

# IfcFlowTerminal: BM-00364_LT171G:LT171G (6)
Type - Material: Vitreous China - TOTO - 01 Cotton
Type - Pset_ManufacturerTypeInformation - Manufacturer: TOTO USA, Inc.
Classification: D2010310 (Uniformat)
Pset_DistributionFlowElementCommon - Reference: LT171G; sets with these values: 2
Name (BM-00364_LT171G:LT171G:...) | In
4061635 | Rez de Rue Simon
4061897 | Rez de Rue Simon
4230428 | rez de rue -1.10m
4230434 | rez de rue -1.10m
4234542 | rez de rue -1.10m
4234543 | rez de rue -1.10m

# IfcFlowTerminal: Cuvette réservoir:Cuvette réservoir (6)
Type - Material: Porcelaine - Lin, Stratifié - Lin, Mat
Pset_DistributionFlowElementCommon - Reference: Cuvette réservoir; sets with these values: 2
Name (Cuvette réservoir:Cuvette réservoir:...) | In
3236051 | 0- Rdc
3236114 | 0- Rdc
3236177 | 0- Rdc
3236264 | 0- Rdc
3255431 | Rez de Rue Simon
3255502 | Rez de Rue Simon

# IfcFlowTerminal: Gouttière avec dauphin:Gouttière avec dauphin 10 (2)
In: 0- Rdc
Type - Material: PVC - Beige, Fonte - Dauphin
Pset_DistributionFlowElementCommon - Reference: Gouttière avec dauphin 10; sets with these values: 2
Name (Gouttière avec dauphin:Gouttière avec dauphin 10:...)
4852216
4852301

# IfcFlowTerminal: Gouttière avec dauphin:Gouttière avec dauphin 13.2 (4)
In: Rez de Rue Simon
Type - Material: PVC - Beige, Fonte - Dauphin
Pset_DistributionFlowElementCommon - Reference: Gouttière avec dauphin 13.2; sets with these values: 2
Name (Gouttière avec dauphin:Gouttière avec dauphin 13.2:...)
4851900
4852005
4852602
4852848

# IfcFlowTerminal: Gouttière avec dauphin:Gouttière avec dauphin 13.5 (2)
In: Rez de Rue Simon
Type - Material: PVC - Beige, Fonte - Dauphin
Pset_DistributionFlowElementCommon - Reference: Gouttière avec dauphin 13.5; sets with these values: 2
Name (Gouttière avec dauphin:Gouttière avec dauphin 13.5:...)
4852663
4852726

# IfcFlowTerminal: Gouttière avec dauphin:Gouttière avec dauphin 13.8, Gouttière avec dauphin:Gouttière avec dauphin 13.8:4852534
In: Rez de Rue Simon
Type - Material: PVC - Beige, Fonte - Dauphin
Pset_DistributionFlowElementCommon - Reference: Gouttière avec dauphin 13.8; sets with these values: 2

# IfcFlowTerminal: Sanitary_Toilets_DURAVIT_257609-Wall-mounted-toilet:Default (4)
In: Rez de Rue Simon
Type - Material: <Unnamed>, 257609 Wall-mounted-toilet - white-tulip-wall-mounted-toilet-257609 - White Alpin
Material: 257609 Wall-mounted-toilet - white-tulip-wall-mounted-toilet-257609 - White Alpin
Pset_DistributionFlowElementCommon - Reference: Default; sets with these values: 2
Name (Sanitary_Toilets_DURAVIT_257609-Wall-mounted-toilet:Default:...)
4071909
4072285
4072333
4072590

# IfcFurnishingElement: #MC - 4 Pieds:4 Pieds (3)
In: Rez de Rue Simon
Type - Material: Plastique - Gris clair
Pset_QuantityTakeOff - Reference: 4 Pieds
Name (#MC - 4 Pieds:4 Pieds:...)
4818736
4818742
4819059

# IfcFurnishingElement: #MC - Façade:Panneau (6)
In: Rez de Rue Simon
Type - Material: Bois - Mélaminé blanc
Type - Pset_FurnitureTypeCommon - Description: #
Pset_QuantityTakeOff - Reference: Panneau
Name (#MC - Façade:Panneau:...)
4818737
4818738
4818743
4818744
4819060
4819061

# IfcFurnishingElement: #MC - Poignée:MC - Poignée (6)
In: Rez de Rue Simon
Type - Material: Bois - Mélaminé jaune pastel
Pset_QuantityTakeOff - Reference: MC - Poignée
Name (#MC - Poignée:MC - Poignée:...)
4818739
4818740
4818745
4818746
4819062
4819063

# IfcFurnishingElement: Artificial Monstera 1800mm:Ny märkning (2)
In: rez de rue -1.10m
Type - Material: <Unnamed>
Pset_QuantityTakeOff - Reference: Ny märkning
Name (Artificial Monstera 1800mm:Ny märkning:...)
4697138
4697195

# IfcFurnishingElement: Artificial banana plant 1500mm:Ny märkning (2)
In: rez de rue -1.10m
Type - Material: <Unnamed>
Pset_QuantityTakeOff - Reference: Ny märkning
Name (Artificial banana plant 1500mm:Ny märkning:...)
4696983
4697363

# IfcFurnishingElement: FU_Inspec_Grade_3-1:Grade 3.3 - Black - Blue (8)
In: rez de rue -1.10m
Type - Material: Fabric - Divina Blue, Plastic - Black, Colour - Coated - Black, Metal - Chrome - Polished
Type - Pset_FurnitureTypeCommon - Description: Barstool with fully upholstered recycled polypropylene seat and back on on powder coated or chromium plated steel tubular frame and footrest.
Type - Pset_ManufacturerTypeInformation - Manufacturer: Inspec
Classification: E2020 (Uniformat)
Pset_QuantityTakeOff - Reference: Grade 3.3 - Black - Blue
Name (FU_Inspec_Grade_3-1:Grade 3.3 - Black - Blue:...) | Group
4651105 | Groupe de modèles:table haute 4 p:4651109
4651106 | Groupe de modèles:table haute 4 p:4651109
4651107 | Groupe de modèles:table haute 4 p:4651109
4651108 | Groupe de modèles:table haute 4 p:4651109
4651112 | Groupe de modèles:table haute 4 p:4651116
4651113 | Groupe de modèles:table haute 4 p:4651116
4651114 | Groupe de modèles:table haute 4 p:4651116
4651115 | Groupe de modèles:table haute 4 p:4651116

# IfcFurnishingElement: MC-1P-R:640 x 600 x 2200 mm (3)
In: Rez de Rue Simon
Type - Material: Bois - Mélaminé blanc
Pset_QuantityTakeOff - Reference: 640 x 600 x 2200 mm
Name (MC-1P-R:640 x 600 x 2200 mm:...)
4818735
4818741
4819058

# IfcFurnishingElement: Placard - Elément de remplissage:220, Placard - Elément de remplissage:220:4819494
In: Rez de Rue Simon
Type - Material: Bois - Mélaminé blanc
Pset_QuantityTakeOff - Reference: 220

# IfcFurnishingElement: Placard - Elément de remplissage:75mm (2)
In: Rez de Rue Simon
Type - Material: Bois - Mélaminé blanc
Pset_QuantityTakeOff - Reference: 75mm
Name (Placard - Elément de remplissage:75mm:...)
3501651
4822322

# IfcFurnishingElement: Placard - Une porte:400MM (2)
In: Rez de Rue Simon
Type - Material: Bois - Mélaminé blanc, Plastique - Noir, <Unnamed>
Pset_QuantityTakeOff - Reference: 400MM
Name (Placard - Une porte:400MM:...)
4819104
4819135

# IfcFurnishingElement: Placard - Une porte:600mm (2)
In: Rez de Rue Simon
Type - Material: Bois - Mélaminé blanc, Plastique - Noir, <Unnamed>
Pset_QuantityTakeOff - Reference: 600mm
Name (Placard - Une porte:600mm:...)
4825197
4998476

# IfcFurnishingElement: Placard - Une porte:800mm (2)
In: Rez de Rue Simon
Type - Material: Bois - Mélaminé blanc, Plastique - Noir, <Unnamed>
Pset_QuantityTakeOff - Reference: 800mm
Name (Placard - Une porte:800mm:...)
3501236
4818856

# IfcFurnishingElement: bancpateres:bancpateres (6)
In: rez de rue -1.10m
Type - Material: Peinture - Grise, <Unnamed>, mat2
Pset_QuantityTakeOff - Reference: bancpateres
Name (bancpateres:bancpateres:...)
4153871
4230411
4230412
4234533
4234535
4234536

# IfcFurnishingElement: siege rabattable 3D:Type 1 (2)
In: rez de rue -1.10m
Type - Material: Aluminium + Plastique
Type - Pset_FurnitureTypeCommon - Description: DELABIE, fabricant français, est le leader européen de l'équipement sanitaire pour les établissements recevant du public. Robinetteries, solutions pour personnes à mobilité réduite, appareils sanitaires, destinés aux écoles, lieux de loisirs, bureaux, hôpitaux, aéroports, ...; NominalHeight: 0.48 m
Type - Pset_ManufacturerTypeInformation - Manufacturer: DELABIE
Pset_QuantityTakeOff - Reference: Type 1
Name (siege rabattable 3D:Type 1:...)
4229664
4236633

# IfcMember: Meneau rectangulaire:100x150, Meneau rectangulaire:100x150:5370152
In: 0- Rdc
Type - PredefinedType: MULLION; Material: OMD_Aluminium Men Ext
Pset_MemberCommon - IsExternal: yes; Reference: 100x150; Span: 2.45205 m
Pset_QuantityTakeOff - Reference: 100x150

# IfcMember: Meneau rectangulaire:150x150, Meneau rectangulaire:150x150:5289662
In: 0- Rdc
Type - PredefinedType: MULLION; Material: OMD_Aluminium Men Ext
Pset_MemberCommon - IsExternal: yes; Reference: 150x150; Span: 2.45205 m
Pset_QuantityTakeOff - Reference: 150x150

# IfcMember: Meneau rectangulaire:180 x100 (3)
In: Rez de Rue Simon
Type - PredefinedType: MULLION; Material: OMD_Aluminium Men Ext
Pset_MemberCommon - IsExternal: yes; Reference: 180 x100
Pset_QuantityTakeOff - Reference: 180 x100
Name (Meneau rectangulaire:180 x100:...) | Span (m)
3261347 | 1.53333
3262154 | 0.716667
3262200 | 0.55

# IfcMember: Meneau rectangulaire:20x20 métalique bleu (114)
In: Rez de Rue Simon
Type - PredefinedType: MULLION; Material: OMD_ anthracite
Pset_MemberCommon - IsExternal: yes; Reference: 20x20 métalique bleu
Pset_QuantityTakeOff - Reference: 20x20 métalique bleu
Name (Meneau rectangulaire:20x20 métalique bleu:...) | Span (m)
4053507 | 0.5
4053510 | 0.012
4053511 | 0.012
4053512 | 0.012
4053513 | 0.012
4053514 | 0.0117186
4053515 | 0.01
4053516 | 0.01
4053517 | 0.01
4053518 | 0.01
4053520 | 0.01
4053528 | 0.012
4053529 | 0.012
4053530 | 0.012
4053531 | 0.012
4053532 | 0.0117186
4053533 | 0.01
4053534 | 0.01
4053535 | 0.01
4053544 | 0.5
4054719 | 0.012
4055289 | 0.01
4055759 | 0.012
4055760 | 0.012
4055761 | 0.012
4055762 | 0.012
4055763 | 0.012
4055764 | 0.012
4055765 | 0.012
4055766 | 0.012
4055767 | 0.01
4055773 | 0.012
4055774 | 0.012
4055775 | 0.012
4055776 | 0.012
4055777 | 0.012
4055778 | 0.012
4055779 | 0.012
4056906 | 0.5
4056907 | 0.012
4056908 | 0.012
4056909 | 0.012
4056910 | 0.012
4056911 | 0.0117186
4056912 | 0.01
4056913 | 0.01
4056914 | 0.01
4056915 | 0.01
4056916 | 0.01
4056917 | 0.012
4056918 | 0.012
4056919 | 0.012
4056920 | 0.012
4056921 | 0.0117186
4056922 | 0.01
4056923 | 0.01
4056924 | 0.01
4056925 | 0.5
4056937 | 0.012
4056952 | 0.01
4056961 | 0.012
4056962 | 0.012
4056963 | 0.012
4056964 | 0.012
4056965 | 0.012
4056966 | 0.012
4056967 | 0.012
4056968 | 0.012
4056969 | 0.01
4056970 | 0.012
4056971 | 0.012
4056972 | 0.012
4056973 | 0.012
4056974 | 0.012
4056975 | 0.012
4056976 | 0.012
4057004 | 0.5
4057005 | 0.012
4057006 | 0.012
4057007 | 0.012
4057008 | 0.012
4057009 | 0.0117186
4057010 | 0.01
4057011 | 0.01
4057012 | 0.01
4057013 | 0.01
4057014 | 0.01
4057015 | 0.012
4057016 | 0.012
4057017 | 0.012
4057018 | 0.012
4057019 | 0.0117186
4057020 | 0.01
4057021 | 0.01
4057022 | 0.01
4057023 | 0.5
4057035 | 0.012
4057050 | 0.01
4057059 | 0.012
4057060 | 0.012
4057061 | 0.012
4057062 | 0.012
4057063 | 0.012
4057064 | 0.012
4057065 | 0.012
4057066 | 0.012
4057067 | 0.01
4057068 | 0.012
4057069 | 0.012
4057070 | 0.012
4057071 | 0.012
4057072 | 0.012
4057073 | 0.012
4057074 | 0.012

# IfcMember: Meneau rectangulaire:22x150 (24)
In: 0- Rdc
Type - PredefinedType: MULLION; Material: OMD_Aluminium blanc
Pset_MemberCommon - IsExternal: yes; Reference: 22x150
Pset_QuantityTakeOff - Reference: 22x150
Name (Meneau rectangulaire:22x150:...) | Span (m)
5369722 | 1.00725
5369782 | 1
5369853 | 1
5370082 | 1
5370151 | 1
5370275 | 1
5370351 | 1.34366
5379652 | 1
5379653 | 1
5379654 | 1
5380092 | 1
5380093 | 0.741551
5369055 | 1.34366
5369056 | 1
5369057 | 1
5369058 | 1
5369059 | 1
5369060 | 1
5369061 | 1
5369062 | 1
5369063 | 1
5369064 | 1.00725
5369065 | 1
5369066 | 0.741551

# IfcMember: Meneau rectangulaire:22x300 (52)
In: 0- Rdc
Type - PredefinedType: MULLION; Material: OMD_Aluminium blanc
Pset_MemberCommon - IsExternal: yes; Reference: 22x300
Pset_QuantityTakeOff - Reference: 22x300
Name (Meneau rectangulaire:22x300:...) | Span (m)
5445408 | 0.603327
5445409 | 0.603562
5445410 | 1.6854
5445411 | 1.68497
5445428 | 0.603562
5445429 | 0.603562
5445430 | 0.603562
5445431 | 0.603562
5445432 | 0.603562
5445433 | 0.603562
5445434 | 0.603562
5445435 | 0.603562
5445321 | 0.29728
5445322 | 0.596673
5445323 | 1.73462
5445324 | 1.73356
5445342 | 0.59728
5445343 | 0.59728
5445344 | 0.59728
5445345 | 0.59728
5445346 | 0.59728
5445347 | 0.59728
5445348 | 0.59728
5445349 | 0.59728
5369072 | 2.97205
5369640 | 1.04155
5369721 | 1
5369781 | 1
5369852 | 1
5370081 | 1
5370150 | 1
5370274 | 1
5370350 | 1
5379649 | 1.00725
5379650 | 1
5379651 | 1
5379941 | 2.67205
5380088 | 1.34483
5289645 | 0.741551
5289654 | 1.34249
5289655 | 1
5289656 | 1
5289665 | 1
5289671 | 1
5289676 | 1
5289686 | 1
5289691 | 1
5289696 | 1
5289701 | 1.00725
5333315 | 1
5369067 | 2.97205
5369068 | 2.97205

# IfcMember: Meneau rectangulaire:300x22 (6)
In: 0- Rdc
Type - PredefinedType: MULLION; Material: OMD_Aluminium blanc
Pset_MemberCommon - IsExternal: yes; Reference: 300x22
Pset_QuantityTakeOff - Reference: 300x22
Name (Meneau rectangulaire:300x22:...) | Span (m)
5327258 | 2.42834
5327908 | 2.44061
5327976 | 1.25201
5378887 | 2.4436
5378899 | 2.42535
5378900 | 1.25028

# IfcMember: Meneau rectangulaire:37.5x150 (20)
In: 0- Rdc
Type - PredefinedType: MULLION; Material: OMD_Aluminium blanc
Pset_MemberCommon - IsExternal: yes; Reference: 37.5x150; Span: 2.45205 m
Pset_QuantityTakeOff - Reference: 37.5x150
Name (Meneau rectangulaire:37.5x150:...)
5369642
5369723
5369783
5369854
5370083
5370276
5370352
5379670
5379671
5379672
5289660
5289661
5289667
5289673
5289678
5289688
5289693
5289698
5289703
5333317

# IfcMember: Meneau rectangulaire:50 x100 (2)
Type - PredefinedType: MULLION; Material: OMD_Aluminium Men Ext
Pset_MemberCommon - IsExternal: yes; Reference: 50 x100
Pset_QuantityTakeOff - Reference: 50 x100
Name (Meneau rectangulaire:50 x100:...) | In | Span (m)
3243781 | 0- Rdc | 1.1997
4730138 | Rez de Rue Simon | 0.9

# IfcMember: Meneau rectangulaire:50x180 (70)
In: Rez de Rue Simon
Type - PredefinedType: MULLION; Material: OMD_Aluminium Men Ext
Pset_MemberCommon - IsExternal: yes; Reference: 50x180
Pset_QuantityTakeOff - Reference: 50x180
Name (Meneau rectangulaire:50x180:...) | Span (m)
3261219 | 1.17978
3261220 | 1.16013
3261221 | 0.691667
3261222 | 0.525
3261225 | 0.525
3261226 | 1.50833
3261230 | 1.745
3261231 | 1.20478
3261232 | 0.716667
3261236 | 1.48333
3261237 | 0.716667
3261238 | 1.53333
3261239 | 1.15478
3261240 | 1.06013
3261246 | 1.695
3261247 | 1.13513
3261248 | 1.53333
3261249 | 0.716667
3261250 | 0.55
3261251 | 0.55
4023131 | 1.15478
4023132 | 1.11013
3261263 | 1.17978
3261264 | 1.2001
3261265 | 0.691667
3261266 | 0.525
3261269 | 0.525
3261270 | 1.50833
3261274 | 1.745
3261275 | 1.20478
3261276 | 0.716667
3261280 | 1.48333
3261281 | 0.716667
3261282 | 1.53333
3261283 | 1.15478
3261284 | 1.1001
3261290 | 1.695
3261291 | 1.1751
3261292 | 1.53333
3261293 | 0.716667
3261294 | 0.55
3261295 | 0.55
4023138 | 1.15478
4023141 | 1.1501
3261308 | 0.297719
3261310 | 0.55
3261314 | 1.53333
3261325 | 0.716667
3261328 | 0.197719
3261334 | 0.8
3261335 | 0.85
3261824 | 0.85
3261846 | 0.55
3262096 | 0.272719
3262116 | 1.53333
3262117 | 0.55
3262118 | 0.716667
3262178 | 0.8
4025986 | 1.65
4026005 | 1.53333
4026006 | 0.55
4026007 | 0.716667
4026015 | 0.252281
4026021 | 1.50833
4026022 | 0.55
4026023 | 0.691667
4026030 | 1.7
4026032 | 0.277281
4026050 | 0.302281
4046439 | 0.202281

# IfcMember: Meneau rectangulaire:50x50 (1724)
Type - PredefinedType: MULLION; Material: OMD_Aluminium Men Ext
Pset_MemberCommon - IsExternal: yes; Reference: 50x50
Pset_QuantityTakeOff - Reference: 50x50
Name (Meneau rectangulaire:50x50:...) | In | Span (m)
3241977 | 0- Rdc | 1.2997
3241978 | 0- Rdc | 1.2997
3241979 | 0- Rdc | 0.47
3241980 | 0- Rdc | 1.71
3242037 | 0- Rdc | 1.71
3242038 | 0- Rdc | 0.47
3242114 | 0- Rdc | 1.1997
3242177 | 0- Rdc | 1.2997
3242178 | 0- Rdc | 1.2997
3242179 | 0- Rdc | 0.47
3242180 | 0- Rdc | 1.71
3242183 | 0- Rdc | 1.71
3242184 | 0- Rdc | 0.47
3242185 | 0- Rdc | 1.1997
3242197 | 0- Rdc | 0.649848
3242198 | 0- Rdc | 0.649848
3242199 | 0- Rdc | 0.47
3242200 | 0- Rdc | 1.71
3242203 | 0- Rdc | 1.71
3242204 | 0- Rdc | 0.47
3242205 | 0- Rdc | 0.599848
4777292 | 0- Rdc | 0.649848
4777293 | 0- Rdc | 0.649848
4777297 | 0- Rdc | 0.599848
3242215 | 0- Rdc | 1.3297
3242216 | 0- Rdc | 1.3297
3242217 | 0- Rdc | 0.47
3242218 | 0- Rdc | 1.71
3242221 | 0- Rdc | 1.71
3242222 | 0- Rdc | 0.47
3242223 | 0- Rdc | 1.2297
3242233 | 0- Rdc | 1.3297
3242234 | 0- Rdc | 1.3297
3242235 | 0- Rdc | 0.47
3242236 | 0- Rdc | 1.71
3242239 | 0- Rdc | 1.71
3242240 | 0- Rdc | 0.47
3242241 | 0- Rdc | 1.2297
3242253 | 0- Rdc | 1.3297
3242254 | 0- Rdc | 1.3297
3242255 | 0- Rdc | 0.47
3242256 | 0- Rdc | 1.71
3242259 | 0- Rdc | 1.71
3242260 | 0- Rdc | 0.47
3242261 | 0- Rdc | 1.2297
3242275 | 0- Rdc | 1.2997
3242276 | 0- Rdc | 1.2997
3242277 | 0- Rdc | 0.47
3242278 | 0- Rdc | 1.71
3242281 | 0- Rdc | 1.71
3242282 | 0- Rdc | 0.47
3242283 | 0- Rdc | 1.1997
3242293 | 0- Rdc | 1.3297
3242294 | 0- Rdc | 1.3297
3242295 | 0- Rdc | 0.47
3242296 | 0- Rdc | 1.71
3242299 | 0- Rdc | 1.71
3242300 | 0- Rdc | 0.47
3242301 | 0- Rdc | 1.2297
3242364 | 0- Rdc | 1.2997
3242365 | 0- Rdc | 1.2997
3242366 | 0- Rdc | 0.47
3242367 | 0- Rdc | 1.71
3242370 | 0- Rdc | 1.71
3242371 | 0- Rdc | 0.47
3242372 | 0- Rdc | 1.1997
3242409 | 0- Rdc | 1.2997
3242410 | 0- Rdc | 1.2997
3242411 | 0- Rdc | 0.47
3242412 | 0- Rdc | 1.71
3242415 | 0- Rdc | 1.71
3242416 | 0- Rdc | 0.47
3242417 | 0- Rdc | 1.1997
3242427 | 0- Rdc | 1.2997
3242428 | 0- Rdc | 1.2997
3242429 | 0- Rdc | 0.47
3242430 | 0- Rdc | 1.71
3242433 | 0- Rdc | 1.71
3242434 | 0- Rdc | 0.47
3242435 | 0- Rdc | 1.1997
3242445 | 0- Rdc | 1.2997
3242446 | 0- Rdc | 1.2997
3242447 | 0- Rdc | 0.47
3242448 | 0- Rdc | 1.71
3242451 | 0- Rdc | 1.71
3242452 | 0- Rdc | 0.47
3242453 | 0- Rdc | 1.1997
3242465 | 0- Rdc | 1.2997
3242466 | 0- Rdc | 1.2997
3242467 | 0- Rdc | 0.47
3242468 | 0- Rdc | 1.71
3242471 | 0- Rdc | 1.71
3242472 | 0- Rdc | 0.47
3242473 | 0- Rdc | 1.1997
3242483 | 0- Rdc | 1.2997
3242484 | 0- Rdc | 1.2997
3242485 | 0- Rdc | 0.47
3242486 | 0- Rdc | 1.71
3242489 | 0- Rdc | 1.71
3242490 | 0- Rdc | 0.47
3242491 | 0- Rdc | 1.1997
3242503 | 0- Rdc | 1.2997
3242504 | 0- Rdc | 1.2997
3242505 | 0- Rdc | 0.47
3242506 | 0- Rdc | 1.71
3242509 | 0- Rdc | 1.71
3242510 | 0- Rdc | 0.47
3242511 | 0- Rdc | 1.1997
3242521 | 0- Rdc | 1.2997
3242522 | 0- Rdc | 1.2997
3242523 | 0- Rdc | 0.47
3242524 | 0- Rdc | 1.71
3242527 | 0- Rdc | 1.71
3242528 | 0- Rdc | 0.47
3242529 | 0- Rdc | 1.1997
3242626 | 0- Rdc | 1.2997
3242627 | 0- Rdc | 1.2997
3242628 | 0- Rdc | 0.47
3242629 | 0- Rdc | 1.71
3242632 | 0- Rdc | 1.71
3242633 | 0- Rdc | 0.47
3242634 | 0- Rdc | 1.1997
3242691 | 0- Rdc | 1.2997
3242692 | 0- Rdc | 1.2997
3242693 | 0- Rdc | 0.47
3242694 | 0- Rdc | 1.71
3242697 | 0- Rdc | 1.71
3242698 | 0- Rdc | 0.47
3242699 | 0- Rdc | 1.1997
3242711 | 0- Rdc | 1.2997
3242712 | 0- Rdc | 1.2997
3242713 | 0- Rdc | 0.47
3242714 | 0- Rdc | 1.71
3242717 | 0- Rdc | 1.71
3242718 | 0- Rdc | 0.47
3242719 | 0- Rdc | 1.1997
3242735 | 0- Rdc | 1.2997
3242736 | 0- Rdc | 1.2997
3242737 | 0- Rdc | 0.47
3242738 | 0- Rdc | 1.71
3242741 | 0- Rdc | 1.71
3242742 | 0- Rdc | 0.47
3242743 | 0- Rdc | 1.1997
3242755 | 0- Rdc | 1.2997
3242756 | 0- Rdc | 1.2997
3242757 | 0- Rdc | 0.47
3242758 | 0- Rdc | 1.71
3242761 | 0- Rdc | 1.71
3242762 | 0- Rdc | 0.47
3242763 | 0- Rdc | 1.1997
3242789 | 0- Rdc | 1.2997
3242790 | 0- Rdc | 1.2997
3242791 | 0- Rdc | 0.47
3242792 | 0- Rdc | 1.71
3242795 | 0- Rdc | 1.71
3242796 | 0- Rdc | 0.47
3242797 | 0- Rdc | 1.1997
3242809 | 0- Rdc | 1.2997
3242810 | 0- Rdc | 1.2997
3242811 | 0- Rdc | 0.47
3242812 | 0- Rdc | 1.71
3242815 | 0- Rdc | 1.71
3242816 | 0- Rdc | 0.47
3242817 | 0- Rdc | 1.1997
3242831 | 0- Rdc | 1.2997
3242832 | 0- Rdc | 1.2997
3242833 | 0- Rdc | 0.47
3242834 | 0- Rdc | 1.71
3242837 | 0- Rdc | 1.71
3242838 | 0- Rdc | 0.47
3242839 | 0- Rdc | 1.1997
3242853 | 0- Rdc | 1.2997
3242854 | 0- Rdc | 1.2997
3242855 | 0- Rdc | 0.47
3242856 | 0- Rdc | 1.71
3242859 | 0- Rdc | 1.71
3242860 | 0- Rdc | 0.47
3242861 | 0- Rdc | 1.1997
3242875 | 0- Rdc | 1.2997
3242876 | 0- Rdc | 1.2997
3242877 | 0- Rdc | 0.47
3242878 | 0- Rdc | 1.71
3242881 | 0- Rdc | 1.71
3242882 | 0- Rdc | 0.47
3242883 | 0- Rdc | 1.1997
3243069 | 0- Rdc | 0.649848
3243070 | 0- Rdc | 0.649848
3243071 | 0- Rdc | 0.47
3243072 | 0- Rdc | 1.71
3243075 | 0- Rdc | 1.71
3243076 | 0- Rdc | 0.47
3243077 | 0- Rdc | 0.574848
4749459 | 0- Rdc | 0.649848
4749460 | 0- Rdc | 0.649848
4749463 | 0- Rdc | 0.574848
3243121 | 0- Rdc | 1.2997
3243122 | 0- Rdc | 1.2997
3243123 | 0- Rdc | 0.47
3243124 | 0- Rdc | 1.71
3243127 | 0- Rdc | 1.71
3243128 | 0- Rdc | 0.47
3243129 | 0- Rdc | 1.1997
3243143 | 0- Rdc | 1.2997
3243144 | 0- Rdc | 1.2997
3243145 | 0- Rdc | 0.47
3243146 | 0- Rdc | 1.71
3243149 | 0- Rdc | 1.71
3243150 | 0- Rdc | 0.47
3243151 | 0- Rdc | 1.1997
3243163 | 0- Rdc | 1.2997
3243164 | 0- Rdc | 1.2997
3243165 | 0- Rdc | 0.47
3243166 | 0- Rdc | 1.71
3243169 | 0- Rdc | 1.71
3243170 | 0- Rdc | 0.47
3243171 | 0- Rdc | 1.1997
3243181 | 0- Rdc | 1.2997
3243182 | 0- Rdc | 1.2997
3243183 | 0- Rdc | 0.47
3243184 | 0- Rdc | 1.71
3243187 | 0- Rdc | 1.71
3243188 | 0- Rdc | 0.47
3243189 | 0- Rdc | 1.1997
3243199 | 0- Rdc | 1.2997
3243200 | 0- Rdc | 1.2997
3243201 | 0- Rdc | 0.47
3243202 | 0- Rdc | 1.71
3243205 | 0- Rdc | 1.71
3243206 | 0- Rdc | 0.47
3243207 | 0- Rdc | 1.1997
3243219 | 0- Rdc | 0.649848
3243220 | 0- Rdc | 0.649848
3243221 | 0- Rdc | 0.47
3243222 | 0- Rdc | 1.71
3243225 | 0- Rdc | 1.71
3243226 | 0- Rdc | 0.47
3243227 | 0- Rdc | 0.574848
4777338 | 0- Rdc | 0.649848
4777339 | 0- Rdc | 0.649848
4777342 | 0- Rdc | 0.574848
4777415 | 0- Rdc | 1.735
3243301 | 0- Rdc | 1.2997
3243302 | 0- Rdc | 1.2997
3243303 | 0- Rdc | 0.47
3243304 | 0- Rdc | 1.71
3243307 | 0- Rdc | 1.71
3243308 | 0- Rdc | 0.47
3243309 | 0- Rdc | 1.1997
3243336 | 0- Rdc | 1.2997
3243337 | 0- Rdc | 1.2997
3243338 | 0- Rdc | 0.47
3243339 | 0- Rdc | 1.71
3243342 | 0- Rdc | 1.71
3243343 | 0- Rdc | 0.47
3243344 | 0- Rdc | 1.1997
3243488 | 0- Rdc | 1.2997
3243489 | 0- Rdc | 1.2997
3243490 | 0- Rdc | 0.47
3243491 | 0- Rdc | 1.71
3243494 | 0- Rdc | 1.71
3243495 | 0- Rdc | 0.47
3243496 | 0- Rdc | 1.1997
3243622 | 0- Rdc | 1.2997
3243623 | 0- Rdc | 1.2997
3243624 | 0- Rdc | 0.47
3243625 | 0- Rdc | 1.71
3243628 | 0- Rdc | 1.71
3243629 | 0- Rdc | 0.47
3243630 | 0- Rdc | 1.1997
3243663 | 0- Rdc | 1.2997
3243664 | 0- Rdc | 1.2997
3243665 | 0- Rdc | 0.47
3243666 | 0- Rdc | 1.71
3243669 | 0- Rdc | 1.71
3243670 | 0- Rdc | 0.47
3243671 | 0- Rdc | 1.1997
3243681 | 0- Rdc | 0.649848
3243682 | 0- Rdc | 0.649848
3243683 | 0- Rdc | 0.47
3243684 | 0- Rdc | 1.71
3243687 | 0- Rdc | 1.71
3243688 | 0- Rdc | 0.47
3243689 | 0- Rdc | 0.574848
4777195 | 0- Rdc | 0.649848
4777196 | 0- Rdc | 0.649848
4777202 | 0- Rdc | 0.574848
3243699 | 0- Rdc | 1.2997
3243700 | 0- Rdc | 1.2997
3243701 | 0- Rdc | 0.47
3243702 | 0- Rdc | 1.71
3243705 | 0- Rdc | 1.71
3243706 | 0- Rdc | 0.47
3243707 | 0- Rdc | 1.1997
3243717 | 0- Rdc | 1.2997
3243718 | 0- Rdc | 1.2997
3243719 | 0- Rdc | 0.47
3243720 | 0- Rdc | 1.71
3243723 | 0- Rdc | 1.71
3243724 | 0- Rdc | 0.47
3243725 | 0- Rdc | 1.1997
3243737 | 0- Rdc | 1.2997
3243738 | 0- Rdc | 1.2997
3243739 | 0- Rdc | 0.47
3243740 | 0- Rdc | 1.71
3243743 | 0- Rdc | 1.71
3243744 | 0- Rdc | 0.47
3243745 | 0- Rdc | 1.1997
3243755 | 0- Rdc | 0.649696
3243756 | 0- Rdc | 0.649696
3243757 | 0- Rdc | 0.47
3243758 | 0- Rdc | 1.71
3243761 | 0- Rdc | 1.71
3243762 | 0- Rdc | 0.47
3243763 | 0- Rdc | 0.549696
3243773 | 0- Rdc | 1.2997
3243774 | 0- Rdc | 1.2997
3243775 | 0- Rdc | 0.99
3243776 | 0- Rdc | 1.19
3243779 | 0- Rdc | 1.19
3243780 | 0- Rdc | 0.99
3243951 | 0- Rdc | 0.649848
3243952 | 0- Rdc | 0.649848
3243953 | 0- Rdc | 0.691667
3243954 | 0- Rdc | 0.525
3243957 | 0- Rdc | 0.525
3243958 | 0- Rdc | 1.50833
3243959 | 0- Rdc | 0.649848
3249009 | 0- Rdc | 0.649848
3249010 | 0- Rdc | 0.649848
3249018 | 0- Rdc | 0.649848
3249047 | 0- Rdc | 0.716667
3249202 | 0- Rdc | 1.48333
3249203 | 0- Rdc | 0.716667
3249208 | 0- Rdc | 1.50833
3249232 | 0- Rdc | 0.574848
3249240 | 0- Rdc | 0.624848
3249102 | 0- Rdc | 0.649848
3249103 | 0- Rdc | 0.649848
3249104 | 0- Rdc | 0.691667
3249105 | 0- Rdc | 0.525
3249108 | 0- Rdc | 0.525
3249109 | 0- Rdc | 1.50833
3249110 | 0- Rdc | 0.649848
3249114 | 0- Rdc | 0.649848
3249115 | 0- Rdc | 0.649848
3249116 | 0- Rdc | 0.649848
3249117 | 0- Rdc | 0.716667
3249280 | 0- Rdc | 1.48333
3249281 | 0- Rdc | 0.716667
3249286 | 0- Rdc | 1.50833
3249308 | 0- Rdc | 0.624848
3249309 | 0- Rdc | 0.574848
3249370 | 0- Rdc | 0.649848
3249371 | 0- Rdc | 0.649848
3249372 | 0- Rdc | 0.691667
3249373 | 0- Rdc | 0.525
3249376 | 0- Rdc | 0.525
3249377 | 0- Rdc | 1.50833
3249378 | 0- Rdc | 0.649848
3249382 | 0- Rdc | 0.649848
3249383 | 0- Rdc | 0.649848
3249384 | 0- Rdc | 0.649848
3249385 | 0- Rdc | 0.716667
3249389 | 0- Rdc | 1.48333
3249390 | 0- Rdc | 0.716667
3249391 | 0- Rdc | 1.50833
3249392 | 0- Rdc | 0.624848
3249393 | 0- Rdc | 0.574848
3249403 | 0- Rdc | 0.649848
3249404 | 0- Rdc | 0.649848
3249405 | 0- Rdc | 0.691667
3249406 | 0- Rdc | 0.525
3249409 | 0- Rdc | 0.525
3249410 | 0- Rdc | 1.50833
3249411 | 0- Rdc | 0.649848
3249415 | 0- Rdc | 0.649848
3249416 | 0- Rdc | 0.649848
3249417 | 0- Rdc | 0.649848
3249418 | 0- Rdc | 0.716667
3249422 | 0- Rdc | 1.48333
3249423 | 0- Rdc | 0.716667
3249424 | 0- Rdc | 1.50833
3249425 | 0- Rdc | 0.624848
3249426 | 0- Rdc | 0.574848
3249440 | 0- Rdc | 0.649848
3249441 | 0- Rdc | 0.649848
3249442 | 0- Rdc | 0.691667
3249443 | 0- Rdc | 0.525
3249446 | 0- Rdc | 0.525
3249447 | 0- Rdc | 1.50833
3249448 | 0- Rdc | 0.649848
3249452 | 0- Rdc | 0.649848
3249453 | 0- Rdc | 0.649848
3249454 | 0- Rdc | 0.649848
3249455 | 0- Rdc | 0.716667
3249459 | 0- Rdc | 1.48333
3249460 | 0- Rdc | 0.716667
3249461 | 0- Rdc | 1.50833
3249462 | 0- Rdc | 0.624848
3249463 | 0- Rdc | 0.574848
3249471 | 0- Rdc | 0.649848
3249472 | 0- Rdc | 0.649848
3249473 | 0- Rdc | 0.691667
3249474 | 0- Rdc | 0.525
3249477 | 0- Rdc | 0.525
3249478 | 0- Rdc | 1.50833
3249479 | 0- Rdc | 0.649848
3249483 | 0- Rdc | 0.649848
3249484 | 0- Rdc | 0.649848
3249485 | 0- Rdc | 0.649848
3249486 | 0- Rdc | 0.716667
3249490 | 0- Rdc | 1.48333
3249491 | 0- Rdc | 0.716667
3249492 | 0- Rdc | 1.50833
3249493 | 0- Rdc | 0.624848
3249494 | 0- Rdc | 0.574848
3249508 | 0- Rdc | 0.649848
3249509 | 0- Rdc | 0.649848
3249510 | 0- Rdc | 0.691667
3249511 | 0- Rdc | 0.525
3249514 | 0- Rdc | 0.525
3249515 | 0- Rdc | 1.50833
3249516 | 0- Rdc | 0.649848
3249520 | 0- Rdc | 0.649848
3249521 | 0- Rdc | 0.649848
3249522 | 0- Rdc | 0.649848
3249523 | 0- Rdc | 0.716667
3249527 | 0- Rdc | 1.48333
3249528 | 0- Rdc | 0.716667
3249529 | 0- Rdc | 1.50833
3249530 | 0- Rdc | 0.624848
3249531 | 0- Rdc | 0.574848
3249598 | 0- Rdc | 1.18
3249599 | 0- Rdc | 1.175
3249600 | 0- Rdc | 0.925
3249601 | 0- Rdc | 1.45
3249610 | 0- Rdc | 1.745
3249611 | 0- Rdc | 1.18
3249613 | 0- Rdc | 0.95
3249617 | 0- Rdc | 1.425
3249618 | 0- Rdc | 0.95
3249619 | 0- Rdc | 1.45
3249620 | 0- Rdc | 1.155
3249621 | 0- Rdc | 1.1
3250043 | 0- Rdc | 1.745
3250045 | 0- Rdc | 1.175
3250068 | 0- Rdc | 1.45
3250069 | 0- Rdc | 0.95
3258383 | Rez de Rue Simon | 1.2997
3258384 | Rez de Rue Simon | 1.2997
3258385 | Rez de Rue Simon | 0.47
3258386 | Rez de Rue Simon | 1.71
3258389 | Rez de Rue Simon | 1.71
3258390 | Rez de Rue Simon | 0.47
3258391 | Rez de Rue Simon | 1.1997
3258394 | Rez de Rue Simon | 1.2997
3258395 | Rez de Rue Simon | 1.2997
3258396 | Rez de Rue Simon | 0.47
3258397 | Rez de Rue Simon | 1.71
3258400 | Rez de Rue Simon | 1.71
3258401 | Rez de Rue Simon | 0.47
3258402 | Rez de Rue Simon | 1.1997
3258405 | Rez de Rue Simon | 0.649848
3258406 | Rez de Rue Simon | 0.649848
3258407 | Rez de Rue Simon | 2.225
3258408 | Rez de Rue Simon | 0.525
3258411 | Rez de Rue Simon | 0.525
3258412 | Rez de Rue Simon | 2.225
3258413 | Rez de Rue Simon | 0.649848
3263112 | Rez de Rue Simon | 0.649848
3263113 | Rez de Rue Simon | 0.649848
3263121 | Rez de Rue Simon | 0.649848
3263146 | Rez de Rue Simon | 2.225
3258416 | Rez de Rue Simon | 1.2997
3258417 | Rez de Rue Simon | 1.2997
3258418 | Rez de Rue Simon | 0.47
3258419 | Rez de Rue Simon | 1.71
3258422 | Rez de Rue Simon | 1.71
3258423 | Rez de Rue Simon | 0.47
3258424 | Rez de Rue Simon | 1.1997
3258427 | Rez de Rue Simon | 1.2997
3258428 | Rez de Rue Simon | 1.2997
3258429 | Rez de Rue Simon | 0.47
3258430 | Rez de Rue Simon | 1.71
3258433 | Rez de Rue Simon | 1.71
3258434 | Rez de Rue Simon | 0.47
3258435 | Rez de Rue Simon | 1.1997
3258438 | Rez de Rue Simon | 1.2997
3258439 | Rez de Rue Simon | 1.2997
3258440 | Rez de Rue Simon | 0.47
3258441 | Rez de Rue Simon | 1.71
3258444 | Rez de Rue Simon | 1.71
3258445 | Rez de Rue Simon | 0.47
3258446 | Rez de Rue Simon | 1.1997
3258449 | Rez de Rue Simon | 1.2997
3258450 | Rez de Rue Simon | 1.2997
3258451 | Rez de Rue Simon | 0.47
3258452 | Rez de Rue Simon | 1.71
3258455 | Rez de Rue Simon | 1.71
3258456 | Rez de Rue Simon | 0.47
3258457 | Rez de Rue Simon | 1.1997
3258460 | Rez de Rue Simon | 1.2997
3258461 | Rez de Rue Simon | 1.2997
3258462 | Rez de Rue Simon | 0.47
3258463 | Rez de Rue Simon | 1.71
3258466 | Rez de Rue Simon | 1.71
3258467 | Rez de Rue Simon | 0.47
3258468 | Rez de Rue Simon | 1.1997
3258471 | Rez de Rue Simon | 1.2997
3258472 | Rez de Rue Simon | 1.2997
3258473 | Rez de Rue Simon | 0.47
3258474 | Rez de Rue Simon | 1.71
3258477 | Rez de Rue Simon | 1.71
3258478 | Rez de Rue Simon | 0.47
3258479 | Rez de Rue Simon | 1.1997
3258482 | Rez de Rue Simon | 1.2997
3258483 | Rez de Rue Simon | 1.2997
3258484 | Rez de Rue Simon | 0.47
3258485 | Rez de Rue Simon | 1.71
3258488 | Rez de Rue Simon | 1.71
3258489 | Rez de Rue Simon | 0.47
3258490 | Rez de Rue Simon | 1.1997
3258493 | Rez de Rue Simon | 1.2997
3258494 | Rez de Rue Simon | 1.2997
3258495 | Rez de Rue Simon | 0.47
3258496 | Rez de Rue Simon | 1.71
3258499 | Rez de Rue Simon | 1.71
3258500 | Rez de Rue Simon | 0.47
3258501 | Rez de Rue Simon | 1.1997
3258504 | Rez de Rue Simon | 1.2997
3258505 | Rez de Rue Simon | 1.2997
3258506 | Rez de Rue Simon | 0.47
3258507 | Rez de Rue Simon | 1.71
3258510 | Rez de Rue Simon | 1.71
3258511 | Rez de Rue Simon | 0.47
3258512 | Rez de Rue Simon | 1.1997
3258515 | Rez de Rue Simon | 1.2997
3258516 | Rez de Rue Simon | 1.2997
3258517 | Rez de Rue Simon | 0.47
3258518 | Rez de Rue Simon | 1.71
3258521 | Rez de Rue Simon | 1.71
3258522 | Rez de Rue Simon | 0.47
3258523 | Rez de Rue Simon | 1.1997
3258526 | Rez de Rue Simon | 1.2997
3258527 | Rez de Rue Simon | 1.2997
3258528 | Rez de Rue Simon | 0.47
3258529 | Rez de Rue Simon | 1.71
3258532 | Rez de Rue Simon | 1.71
3258533 | Rez de Rue Simon | 0.47
3258534 | Rez de Rue Simon | 1.1997
3258537 | Rez de Rue Simon | 1.2997
3258538 | Rez de Rue Simon | 1.2997
3258539 | Rez de Rue Simon | 0.47
3258540 | Rez de Rue Simon | 1.71
3258543 | Rez de Rue Simon | 1.71
3258544 | Rez de Rue Simon | 0.47
3258545 | Rez de Rue Simon | 1.1997
3258548 | Rez de Rue Simon | 1.2997
3258549 | Rez de Rue Simon | 1.2997
3258550 | Rez de Rue Simon | 0.47
3258551 | Rez de Rue Simon | 1.71
3258554 | Rez de Rue Simon | 1.71
3258555 | Rez de Rue Simon | 0.47
3258556 | Rez de Rue Simon | 1.1997
3258559 | Rez de Rue Simon | 1.2997
3258560 | Rez de Rue Simon | 1.2997
3258561 | Rez de Rue Simon | 0.47
3258562 | Rez de Rue Simon | 1.71
3258565 | Rez de Rue Simon | 1.71
3258566 | Rez de Rue Simon | 0.47
3258567 | Rez de Rue Simon | 1.1997
3258570 | Rez de Rue Simon | 1.2997
3258571 | Rez de Rue Simon | 1.2997
3258572 | Rez de Rue Simon | 0.47
3258573 | Rez de Rue Simon | 1.71
3258576 | Rez de Rue Simon | 1.71
3258577 | Rez de Rue Simon | 0.47
3258578 | Rez de Rue Simon | 1.1997
3258581 | Rez de Rue Simon | 1.2997
3258582 | Rez de Rue Simon | 1.2997
3258583 | Rez de Rue Simon | 0.47
3258584 | Rez de Rue Simon | 1.71
3258587 | Rez de Rue Simon | 1.71
3258588 | Rez de Rue Simon | 0.47
3258589 | Rez de Rue Simon | 1.1997
3258592 | Rez de Rue Simon | 1.2997
3258593 | Rez de Rue Simon | 1.2997
3258594 | Rez de Rue Simon | 2.11
3258595 | Rez de Rue Simon | 0.67
3981674 | Rez de Rue Simon | 0.67
3981675 | Rez de Rue Simon | 2.11
3981783 | Rez de Rue Simon | 1.1997
3259398 | Rez de Rue Simon | 1.2997
3259399 | Rez de Rue Simon | 1.2997
3259400 | Rez de Rue Simon | 0.47
3259401 | Rez de Rue Simon | 1.71
3259404 | Rez de Rue Simon | 1.71
3259405 | Rez de Rue Simon | 0.47
3259406 | Rez de Rue Simon | 1.1997
3259409 | Rez de Rue Simon | 1.2997
3259410 | Rez de Rue Simon | 1.2997
3259411 | Rez de Rue Simon | 0.47
3259412 | Rez de Rue Simon | 1.71
3259415 | Rez de Rue Simon | 1.71
3259416 | Rez de Rue Simon | 0.47
3259417 | Rez de Rue Simon | 1.1997
3259420 | Rez de Rue Simon | 1.2997
3259421 | Rez de Rue Simon | 1.2997
3259422 | Rez de Rue Simon | 0.47
3259423 | Rez de Rue Simon | 1.71
3259426 | Rez de Rue Simon | 1.71
3259427 | Rez de Rue Simon | 0.47
3259428 | Rez de Rue Simon | 1.1997
3259431 | Rez de Rue Simon | 1.2997
3259432 | Rez de Rue Simon | 1.2997
3259433 | Rez de Rue Simon | 0.47
3259434 | Rez de Rue Simon | 1.71
3259437 | Rez de Rue Simon | 1.71
3259438 | Rez de Rue Simon | 0.47
3259439 | Rez de Rue Simon | 1.1997
3259442 | Rez de Rue Simon | 1.2997
3259443 | Rez de Rue Simon | 1.2997
3259444 | Rez de Rue Simon | 0.47
3259445 | Rez de Rue Simon | 1.71
3259448 | Rez de Rue Simon | 1.71
3259449 | Rez de Rue Simon | 0.47
3259450 | Rez de Rue Simon | 1.1997
3259453 | Rez de Rue Simon | 1.2997
3259454 | Rez de Rue Simon | 1.2997
3259455 | Rez de Rue Simon | 0.47
3259456 | Rez de Rue Simon | 1.71
3259459 | Rez de Rue Simon | 1.71
3259460 | Rez de Rue Simon | 0.47
3259461 | Rez de Rue Simon | 1.1997
3259464 | Rez de Rue Simon | 1.2997
3259465 | Rez de Rue Simon | 1.2997
3259466 | Rez de Rue Simon | 0.47
3259467 | Rez de Rue Simon | 1.71
3259470 | Rez de Rue Simon | 1.71
3259471 | Rez de Rue Simon | 0.47
3259472 | Rez de Rue Simon | 1.1997
3259475 | Rez de Rue Simon | 1.2997
3259476 | Rez de Rue Simon | 1.2997
3259477 | Rez de Rue Simon | 0.47
3259478 | Rez de Rue Simon | 1.71
3259481 | Rez de Rue Simon | 1.71
3259482 | Rez de Rue Simon | 0.47
3259483 | Rez de Rue Simon | 1.1997
3260690 | 0- Rdc | 1.18
3260691 | 0- Rdc | 1.175
3260692 | 0- Rdc | 0.925
3260693 | 0- Rdc | 1.45
3260701 | 0- Rdc | 1.745
3260702 | 0- Rdc | 1.18
3260703 | 0- Rdc | 0.95
3260707 | 0- Rdc | 1.425
3260708 | 0- Rdc | 0.95
3260709 | 0- Rdc | 1.45
3260710 | 0- Rdc | 1.155
3260711 | 0- Rdc | 1.1
3260716 | 0- Rdc | 1.745
3260718 | 0- Rdc | 1.175
3260719 | 0- Rdc | 1.45
3260720 | 0- Rdc | 0.95
3260743 | 0- Rdc | 1.18
3260744 | 0- Rdc | 1.175
3260745 | 0- Rdc | 0.925
3260746 | 0- Rdc | 1.45
3260754 | 0- Rdc | 1.745
3260755 | 0- Rdc | 1.18
3260756 | 0- Rdc | 0.95
3260760 | 0- Rdc | 1.425
3260761 | 0- Rdc | 0.95
3260762 | 0- Rdc | 1.45
3260763 | 0- Rdc | 1.155
3260764 | 0- Rdc | 1.1
3260769 | 0- Rdc | 1.745
3260771 | 0- Rdc | 1.175
3260772 | 0- Rdc | 1.45
3260773 | 0- Rdc | 0.95
4022861 | Rez de Rue Simon | 0.1
4022862 | Rez de Rue Simon | 0.3
4022870 | Rez de Rue Simon | 0.1
4022871 | Rez de Rue Simon | 0.1
4022918 | Rez de Rue Simon | 0.15
4022919 | Rez de Rue Simon | 0.4
4022927 | Rez de Rue Simon | 0.15
4022928 | Rez de Rue Simon | 0.15
4022989 | Rez de Rue Simon | 0.25
4022990 | Rez de Rue Simon | 0.3
4022996 | Rez de Rue Simon | 0.25
4022997 | Rez de Rue Simon | 0.25
4023045 | Rez de Rue Simon | 0.1
4023046 | Rez de Rue Simon | 0.2
4023051 | Rez de Rue Simon | 0.1
4023052 | Rez de Rue Simon | 0.1
3261336 | Rez de Rue Simon | 1.55833
3261337 | Rez de Rue Simon | 0.766667
3261344 | Rez de Rue Simon | 0.075
3261345 | Rez de Rue Simon | 0.1
3261706 | Rez de Rue Simon | 0.075
3261825 | Rez de Rue Simon | 0.1
3261845 | Rez de Rue Simon | 1.53333
3261847 | Rez de Rue Simon | 0.716667
4026040 | Rez de Rue Simon | 1.53333
4026041 | Rez de Rue Simon | 0.55
4026042 | Rez de Rue Simon | 0.716667
3263583 | Rez de Rue Simon | 1.18
3263584 | Rez de Rue Simon | 1.175
3263585 | Rez de Rue Simon | 0.691667
3263586 | Rez de Rue Simon | 0.55
3263589 | Rez de Rue Simon | 0.55
3263590 | Rez de Rue Simon | 1.53333
3263594 | Rez de Rue Simon | 0.8725
3263595 | Rez de Rue Simon | 1.18
3263596 | Rez de Rue Simon | 0.716667
3263600 | Rez de Rue Simon | 1.50833
3263601 | Rez de Rue Simon | 0.716667
3263602 | Rez de Rue Simon | 1.53333
3263603 | Rez de Rue Simon | 1.155
3263604 | Rez de Rue Simon | 1.1
3263609 | Rez de Rue Simon | 0.8725
3263610 | Rez de Rue Simon | 0.8225
3263611 | Rez de Rue Simon | 1.175
3263612 | Rez de Rue Simon | 1.53333
3263613 | Rez de Rue Simon | 0.716667
3263614 | Rez de Rue Simon | 0.55
3263615 | Rez de Rue Simon | 0.55
3263620 | Rez de Rue Simon | 0.8725
3263621 | Rez de Rue Simon | 0.8725
3263622 | Rez de Rue Simon | 0.8225
3263623 | Rez de Rue Simon | 1.55833
3263624 | Rez de Rue Simon | 0.716667
3264177 | 0- Rdc | 1.18
3264178 | 0- Rdc | 1.175
3264179 | 0- Rdc | 0.925
3264180 | 0- Rdc | 1.45
3264183 | 0- Rdc | 1.745
3264184 | 0- Rdc | 1.18
3264185 | 0- Rdc | 0.95
3264189 | 0- Rdc | 1.425
3264190 | 0- Rdc | 0.95
3264191 | 0- Rdc | 1.45
3264192 | 0- Rdc | 1.155
3264193 | 0- Rdc | 1.1
3264197 | 0- Rdc | 1.745
3264198 | 0- Rdc | 1.175
3264199 | 0- Rdc | 1.45
3264200 | 0- Rdc | 0.95
3269866 | Rez de Rue Simon | 1.30483
3269867 | Rez de Rue Simon | 1.30483
3269868 | Rez de Rue Simon | 2.13
3269869 | Rez de Rue Simon | 0.65
3981737 | Rez de Rue Simon | 0.65
3981738 | Rez de Rue Simon | 2.13
3981765 | Rez de Rue Simon | 1.20483
3293094 | 0- Rdc | 1.33314
3293095 | 0- Rdc | 1.33314
3293096 | 0- Rdc | 0.47
3293097 | 0- Rdc | 1.71
3293100 | 0- Rdc | 1.71
3293101 | 0- Rdc | 0.47
3293102 | 0- Rdc | 1.23314
3294429 | 1-R+1 | 1.2997
3294430 | 1-R+1 | 1.2997
3294431 | 1-R+1 | 0.47
3294432 | 1-R+1 | 1.71
3294435 | 1-R+1 | 1.71
3294436 | 1-R+1 | 0.47
3294437 | 1-R+1 | 1.1997
3294440 | 1-R+1 | 1.2997
3294441 | 1-R+1 | 1.2997
3294442 | 1-R+1 | 0.47
3294443 | 1-R+1 | 1.71
3294446 | 1-R+1 | 1.71
3294447 | 1-R+1 | 0.47
3294448 | 1-R+1 | 1.1997
3294451 | 1-R+1 | 1.2997
3294452 | 1-R+1 | 1.2997
3294453 | 1-R+1 | 0.47
3294454 | 1-R+1 | 1.71
3294457 | 1-R+1 | 1.71
3294458 | 1-R+1 | 0.47
3294459 | 1-R+1 | 1.1997
3294462 | 1-R+1 | 1.2997
3294463 | 1-R+1 | 1.2997
3294464 | 1-R+1 | 0.47
3294465 | 1-R+1 | 1.71
3294468 | 1-R+1 | 1.71
3294469 | 1-R+1 | 0.47
3294470 | 1-R+1 | 1.1997
3294473 | 1-R+1 | 1.2997
3294474 | 1-R+1 | 1.2997
3294475 | 1-R+1 | 0.47
3294476 | 1-R+1 | 1.71
3294479 | 1-R+1 | 1.71
3294480 | 1-R+1 | 0.47
3294481 | 1-R+1 | 1.1997
3294484 | 1-R+1 | 1.2997
3294485 | 1-R+1 | 1.2997
3294486 | 1-R+1 | 0.47
3294487 | 1-R+1 | 1.71
3294490 | 1-R+1 | 1.71
3294491 | 1-R+1 | 0.47
3294492 | 1-R+1 | 1.1997
3294495 | 1-R+1 | 1.2997
3294496 | 1-R+1 | 1.2997
3294497 | 1-R+1 | 0.47
3294498 | 1-R+1 | 1.71
3294501 | 1-R+1 | 1.71
3294502 | 1-R+1 | 0.47
3294503 | 1-R+1 | 1.1997
3294506 | 1-R+1 | 1.2997
3294507 | 1-R+1 | 1.2997
3294508 | 1-R+1 | 0.47
3294509 | 1-R+1 | 1.71
3294512 | 1-R+1 | 1.71
3294513 | 1-R+1 | 0.47
3294514 | 1-R+1 | 1.1997
3294517 | 1-R+1 | 1.2997
3294518 | 1-R+1 | 1.2997
3294519 | 1-R+1 | 0.47
3294520 | 1-R+1 | 1.71
3294523 | 1-R+1 | 1.71
3294524 | 1-R+1 | 0.47
3294525 | 1-R+1 | 1.1997
3294528 | 1-R+1 | 1.2997
3294529 | 1-R+1 | 1.2997
3294530 | 1-R+1 | 0.47
3294531 | 1-R+1 | 1.71
3294534 | 1-R+1 | 1.71
3294535 | 1-R+1 | 0.47
3294536 | 1-R+1 | 1.1997
3294539 | 1-R+1 | 1.2997
3294540 | 1-R+1 | 1.2997
3294541 | 1-R+1 | 0.47
3294542 | 1-R+1 | 1.71
3294545 | 1-R+1 | 1.71
3294546 | 1-R+1 | 0.47
3294547 | 1-R+1 | 1.1997
3294550 | 1-R+1 | 1.2997
3294551 | 1-R+1 | 1.2997
3294552 | 1-R+1 | 0.47
3294553 | 1-R+1 | 1.71
3294556 | 1-R+1 | 1.71
3294557 | 1-R+1 | 0.47
3294558 | 1-R+1 | 1.1997
3294561 | 1-R+1 | 1.2997
3294562 | 1-R+1 | 1.2997
3294563 | 1-R+1 | 0.47
3294564 | 1-R+1 | 1.71
3294567 | 1-R+1 | 1.71
3294568 | 1-R+1 | 0.47
3294569 | 1-R+1 | 1.1997
3294572 | 1-R+1 | 1.2997
3294573 | 1-R+1 | 1.2997
3294574 | 1-R+1 | 0.47
3294575 | 1-R+1 | 1.71
3294578 | 1-R+1 | 1.71
3294579 | 1-R+1 | 0.47
3294580 | 1-R+1 | 1.1997
3294583 | 1-R+1 | 1.2997
3294584 | 1-R+1 | 1.2997
3294585 | 1-R+1 | 0.47
3294586 | 1-R+1 | 1.71
3294589 | 1-R+1 | 1.71
3294590 | 1-R+1 | 0.47
3294591 | 1-R+1 | 1.1997
3294594 | 1-R+1 | 1.2997
3294595 | 1-R+1 | 1.2997
3294596 | 1-R+1 | 0.47
3294597 | 1-R+1 | 1.71
3294600 | 1-R+1 | 1.71
3294601 | 1-R+1 | 0.47
3294602 | 1-R+1 | 1.1997
3294605 | 1-R+1 | 1.2997
3294606 | 1-R+1 | 1.2997
3294607 | 1-R+1 | 0.47
3294608 | 1-R+1 | 1.71
3294611 | 1-R+1 | 1.71
3294612 | 1-R+1 | 0.47
3294613 | 1-R+1 | 1.1997
3294616 | 1-R+1 | 1.2997
3294617 | 1-R+1 | 1.2997
3294618 | 1-R+1 | 0.47
3294619 | 1-R+1 | 1.71
3294622 | 1-R+1 | 1.71
3294623 | 1-R+1 | 0.47
3294624 | 1-R+1 | 1.1997
3294627 | 1-R+1 | 1.2997
3294628 | 1-R+1 | 1.2997
3294629 | 1-R+1 | 0.47
3294630 | 1-R+1 | 1.71
3294633 | 1-R+1 | 1.71
3294634 | 1-R+1 | 0.47
3294635 | 1-R+1 | 1.1997
3294638 | 1-R+1 | 1.2997
3294639 | 1-R+1 | 1.2997
3294640 | 1-R+1 | 0.47
3294641 | 1-R+1 | 1.71
3294644 | 1-R+1 | 1.71
3294645 | 1-R+1 | 0.47
3294646 | 1-R+1 | 1.1997
3294649 | 1-R+1 | 1.2997
3294650 | 1-R+1 | 1.2997
3294651 | 1-R+1 | 0.47
3294652 | 1-R+1 | 1.71
3294655 | 1-R+1 | 1.71
3294656 | 1-R+1 | 0.47
3294657 | 1-R+1 | 1.1997
3294660 | 1-R+1 | 1.2997
3294661 | 1-R+1 | 1.2997
3294662 | 1-R+1 | 0.47
3294663 | 1-R+1 | 1.71
3294666 | 1-R+1 | 1.71
3294667 | 1-R+1 | 0.47
3294668 | 1-R+1 | 1.1997
3294671 | 1-R+1 | 1.2997
3294672 | 1-R+1 | 1.2997
3294673 | 1-R+1 | 0.47
3294674 | 1-R+1 | 1.71
3294677 | 1-R+1 | 1.71
3294678 | 1-R+1 | 0.47
3294679 | 1-R+1 | 1.1997
3294682 | 1-R+1 | 1.2997
3294683 | 1-R+1 | 1.2997
3294684 | 1-R+1 | 0.47
3294685 | 1-R+1 | 1.71
3294688 | 1-R+1 | 1.71
3294689 | 1-R+1 | 0.47
3294690 | 1-R+1 | 1.1997
3294693 | 1-R+1 | 1.2997
3294694 | 1-R+1 | 1.2997
3294695 | 1-R+1 | 0.47
3294696 | 1-R+1 | 1.71
3294699 | 1-R+1 | 1.71
3294700 | 1-R+1 | 0.47
3294701 | 1-R+1 | 1.1997
3294704 | 1-R+1 | 1.2997
3294705 | 1-R+1 | 1.2997
3294706 | 1-R+1 | 0.47
3294707 | 1-R+1 | 1.71
3294710 | 1-R+1 | 1.71
3294711 | 1-R+1 | 0.47
3294712 | 1-R+1 | 1.1997
3294715 | 1-R+1 | 1.2997
3294716 | 1-R+1 | 1.2997
3294717 | 1-R+1 | 0.47
3294718 | 1-R+1 | 1.71
3294721 | 1-R+1 | 1.71
3294722 | 1-R+1 | 0.47
3294723 | 1-R+1 | 1.1997
3294726 | 1-R+1 | 1.2997
3294727 | 1-R+1 | 1.2997
3294728 | 1-R+1 | 0.47
3294729 | 1-R+1 | 1.71
3294732 | 1-R+1 | 1.71
3294733 | 1-R+1 | 0.47
3294734 | 1-R+1 | 1.1997
3294737 | 1-R+1 | 0.649848
3294738 | 1-R+1 | 0.649848
3294739 | 1-R+1 | 0.47
3294740 | 1-R+1 | 1.71
3294743 | 1-R+1 | 1.71
3294744 | 1-R+1 | 0.47
3294745 | 1-R+1 | 0.574848
4749526 | 1-R+1 | 0.649848
4749527 | 1-R+1 | 0.649848
4749530 | 1-R+1 | 0.574848
3294748 | 1-R+1 | 1.2997
3294749 | 1-R+1 | 1.2997
3294750 | 1-R+1 | 0.47
3294751 | 1-R+1 | 1.71
3294754 | 1-R+1 | 1.71
3294755 | 1-R+1 | 0.47
3294756 | 1-R+1 | 1.1997
3294759 | 1-R+1 | 1.2997
3294760 | 1-R+1 | 1.2997
3294761 | 1-R+1 | 0.47
3294762 | 1-R+1 | 1.71
3294765 | 1-R+1 | 1.71
3294766 | 1-R+1 | 0.47
3294767 | 1-R+1 | 1.1997
3294770 | 1-R+1 | 1.2997
3294771 | 1-R+1 | 1.2997
3294772 | 1-R+1 | 0.47
3294773 | 1-R+1 | 1.71
3294776 | 1-R+1 | 1.71
3294777 | 1-R+1 | 0.47
3294778 | 1-R+1 | 1.1997
3294781 | 1-R+1 | 1.2997
3294782 | 1-R+1 | 1.2997
3294783 | 1-R+1 | 0.47
3294784 | 1-R+1 | 1.71
3294787 | 1-R+1 | 1.71
3294788 | 1-R+1 | 0.47
3294789 | 1-R+1 | 1.1997
3294792 | 1-R+1 | 1.2997
3294793 | 1-R+1 | 1.2997
3294794 | 1-R+1 | 0.47
3294795 | 1-R+1 | 1.71
3294798 | 1-R+1 | 1.71
3294799 | 1-R+1 | 0.47
3294800 | 1-R+1 | 1.1997
3294803 | 1-R+1 | 0.649848
3294804 | 1-R+1 | 0.649848
3294805 | 1-R+1 | 0.47
3294806 | 1-R+1 | 1.71
3294809 | 1-R+1 | 1.71
3294810 | 1-R+1 | 0.47
3294811 | 1-R+1 | 0.574848
4749619 | 1-R+1 | 0.649848
4749620 | 1-R+1 | 0.649848
4749623 | 1-R+1 | 0.574848
3294814 | 1-R+1 | 1.2997
3294815 | 1-R+1 | 1.2997
3294816 | 1-R+1 | 0.47
3294817 | 1-R+1 | 1.71
3294820 | 1-R+1 | 1.71
3294821 | 1-R+1 | 0.47
3294822 | 1-R+1 | 1.1997
3294825 | 1-R+1 | 1.2997
3294826 | 1-R+1 | 1.2997
3294827 | 1-R+1 | 0.47
3294828 | 1-R+1 | 1.71
3294831 | 1-R+1 | 1.71
3294832 | 1-R+1 | 0.47
3294833 | 1-R+1 | 1.1997
3294836 | 1-R+1 | 1.2997
3294837 | 1-R+1 | 1.2997
3294838 | 1-R+1 | 0.47
3294839 | 1-R+1 | 1.71
3294842 | 1-R+1 | 1.71
3294843 | 1-R+1 | 0.47
3294844 | 1-R+1 | 1.1997
3294847 | 1-R+1 | 1.2997
3294848 | 1-R+1 | 1.2997
3294849 | 1-R+1 | 0.47
3294850 | 1-R+1 | 1.71
3294853 | 1-R+1 | 1.71
3294854 | 1-R+1 | 0.47
3294855 | 1-R+1 | 1.1997
3294858 | 1-R+1 | 1.2997
3294859 | 1-R+1 | 1.2997
3294860 | 1-R+1 | 0.47
3294861 | 1-R+1 | 1.71
3294864 | 1-R+1 | 1.71
3294865 | 1-R+1 | 0.47
3294866 | 1-R+1 | 1.1997
3294869 | 1-R+1 | 1.2997
3294870 | 1-R+1 | 1.2997
3294871 | 1-R+1 | 0.47
3294872 | 1-R+1 | 1.71
3294875 | 1-R+1 | 1.71
3294876 | 1-R+1 | 0.47
3294877 | 1-R+1 | 1.1997
3294880 | 1-R+1 | 1.2997
3294881 | 1-R+1 | 1.2997
3294882 | 1-R+1 | 0.47
3294883 | 1-R+1 | 1.71
3294886 | 1-R+1 | 1.71
3294887 | 1-R+1 | 0.47
3294888 | 1-R+1 | 1.1997
3294902 | 1-R+1 | 1.2997
3294903 | 1-R+1 | 1.2997
3294904 | 1-R+1 | 0.47
3294905 | 1-R+1 | 1.71
3294908 | 1-R+1 | 1.71
3294909 | 1-R+1 | 0.47
3294910 | 1-R+1 | 1.1997
3295100 | 1-R+1 | 1.33248
3295101 | 1-R+1 | 1.33248
3295102 | 1-R+1 | 0.47
3295103 | 1-R+1 | 1.71
3295106 | 1-R+1 | 1.71
3295107 | 1-R+1 | 0.47
3295108 | 1-R+1 | 1.23248
3295345 | 1-R+1 | 1.2997
3295346 | 1-R+1 | 1.2997
3295347 | 1-R+1 | 0.47
3295348 | 1-R+1 | 1.71
3295351 | 1-R+1 | 1.71
3295352 | 1-R+1 | 0.47
3295353 | 1-R+1 | 1.1997
3295369 | 1-R+1 | 1.2997
3295370 | 1-R+1 | 1.2997
3295371 | 1-R+1 | 0.47
3295372 | 1-R+1 | 1.71
3295375 | 1-R+1 | 1.71
3295376 | 1-R+1 | 0.47
3295377 | 1-R+1 | 1.1997
3295395 | 1-R+1 | 1.2997
3295396 | 1-R+1 | 1.2997
3295397 | 1-R+1 | 0.47
3295398 | 1-R+1 | 1.71
3295401 | 1-R+1 | 1.71
3295402 | 1-R+1 | 0.47
3295403 | 1-R+1 | 1.1997
3295415 | 1-R+1 | 1.2997
3295416 | 1-R+1 | 1.2997
3295417 | 1-R+1 | 0.47
3295418 | 1-R+1 | 1.71
3295421 | 1-R+1 | 1.71
3295422 | 1-R+1 | 0.47
3295423 | 1-R+1 | 1.1997
3295441 | 1-R+1 | 1.2997
3295442 | 1-R+1 | 1.2997
3295443 | 1-R+1 | 0.47
3295444 | 1-R+1 | 1.71
3295447 | 1-R+1 | 1.71
3295448 | 1-R+1 | 0.47
3295449 | 1-R+1 | 1.1997
3295463 | 1-R+1 | 1.2997
3295464 | 1-R+1 | 1.2997
3295465 | 1-R+1 | 0.47
3295466 | 1-R+1 | 1.71
3295469 | 1-R+1 | 1.71
3295470 | 1-R+1 | 0.47
3295471 | 1-R+1 | 1.1997
3295487 | 1-R+1 | 1.2997
3295488 | 1-R+1 | 1.2997
3295489 | 1-R+1 | 0.47
3295490 | 1-R+1 | 1.71
3295493 | 1-R+1 | 1.71
3295494 | 1-R+1 | 0.47
3295495 | 1-R+1 | 1.1997
3296154 | 1-R+1 | 1.2997
3296155 | 1-R+1 | 1.2997
3296156 | 1-R+1 | 0.47
3296157 | 1-R+1 | 1.71
3296160 | 1-R+1 | 1.71
3296161 | 1-R+1 | 0.47
3296162 | 1-R+1 | 1.1997
3296197 | 1-R+1 | 1.2997
3296198 | 1-R+1 | 1.2997
3296199 | 1-R+1 | 0.47
3296200 | 1-R+1 | 1.71
3296203 | 1-R+1 | 1.71
3296204 | 1-R+1 | 0.47
3296205 | 1-R+1 | 1.1997
3296217 | 1-R+1 | 1.2997
3296218 | 1-R+1 | 1.2997
3296219 | 1-R+1 | 0.47
3296220 | 1-R+1 | 1.71
3296223 | 1-R+1 | 1.71
3296224 | 1-R+1 | 0.47
3296225 | 1-R+1 | 1.1997
3296237 | 1-R+1 | 1.2997
3296238 | 1-R+1 | 1.2997
3296239 | 1-R+1 | 0.47
3296240 | 1-R+1 | 1.71
3296243 | 1-R+1 | 1.71
3296244 | 1-R+1 | 0.47
3296245 | 1-R+1 | 1.1997
3296257 | 1-R+1 | 1.2997
3296258 | 1-R+1 | 1.2997
3296259 | 1-R+1 | 0.47
3296260 | 1-R+1 | 1.71
3296263 | 1-R+1 | 1.71
3296264 | 1-R+1 | 0.47
3296265 | 1-R+1 | 1.1997
3296293 | 1-R+1 | 1.2997
3296294 | 1-R+1 | 1.2997
3296295 | 1-R+1 | 0.47
3296296 | 1-R+1 | 1.71
3296299 | 1-R+1 | 1.71
3296300 | 1-R+1 | 0.47
3296301 | 1-R+1 | 1.1997
3296313 | 1-R+1 | 1.2997
3296314 | 1-R+1 | 1.2997
3296315 | 1-R+1 | 0.47
3296316 | 1-R+1 | 1.71
3296319 | 1-R+1 | 1.71
3296320 | 1-R+1 | 0.47
3296321 | 1-R+1 | 1.1997
3296562 | 1-R+1 | 1.2997
3296563 | 1-R+1 | 1.2997
3296564 | 1-R+1 | 0.47
3296565 | 1-R+1 | 1.71
3296568 | 1-R+1 | 1.71
3296569 | 1-R+1 | 0.47
3296570 | 1-R+1 | 1.1997
3296582 | 1-R+1 | 1.2997
3296583 | 1-R+1 | 1.2997
3296584 | 1-R+1 | 0.47
3296585 | 1-R+1 | 1.71
3296588 | 1-R+1 | 1.71
3296589 | 1-R+1 | 0.47
3296590 | 1-R+1 | 1.1997
3297502 | 2-R+2 | 1.1997
3297503 | 2-R+2 | 1.1997
3297504 | 2-R+2 | 1.65
3297505 | 2-R+2 | 1.65
3297602 | 2-R+2 | 1.1997
3297603 | 2-R+2 | 1.1997
3297604 | 2-R+2 | 1.65
3297605 | 2-R+2 | 1.65
3297917 | 2-R+2 | 1.04
3297918 | 2-R+2 | 1.04
3297919 | 2-R+2 | 1.65
3297920 | 2-R+2 | 1.65
3298371 | 2-R+2 | 1.04
3298372 | 2-R+2 | 1.04
3298373 | 2-R+2 | 1.65
3298374 | 2-R+2 | 1.65
3298386 | 2-R+2 | 1.04
3298387 | 2-R+2 | 1.04
3298388 | 2-R+2 | 1.65
3298389 | 2-R+2 | 1.65
3298399 | 2-R+2 | 1.04
3298400 | 2-R+2 | 1.04
3298401 | 2-R+2 | 1.65
3298402 | 2-R+2 | 1.65
3298414 | 2-R+2 | 0.57
3298415 | 2-R+2 | 0.57
3298416 | 2-R+2 | 1.55
3298417 | 2-R+2 | 1.55
4749851 | 2-R+2 | 0.57
4749852 | 2-R+2 | 0.57
3298429 | 2-R+2 | 1.04
3298430 | 2-R+2 | 1.04
3298431 | 2-R+2 | 1.65
3298432 | 2-R+2 | 1.65
3298444 | 2-R+2 | 1.04
3298445 | 2-R+2 | 1.04
3298446 | 2-R+2 | 1.65
3298447 | 2-R+2 | 1.65
3298457 | 2-R+2 | 1.04
3298458 | 2-R+2 | 1.04
3298459 | 2-R+2 | 1.65
3298460 | 2-R+2 | 1.65
3298474 | 2-R+2 | 1.04
3298475 | 2-R+2 | 1.04
3298476 | 2-R+2 | 1.65
3298477 | 2-R+2 | 1.65
3298487 | 2-R+2 | 1.04
3298488 | 2-R+2 | 1.04
3298489 | 2-R+2 | 1.65
3298490 | 2-R+2 | 1.65
3298500 | 2-R+2 | 1.04
3298501 | 2-R+2 | 1.04
3298502 | 2-R+2 | 1.65
3298503 | 2-R+2 | 1.65
3298513 | 2-R+2 | 1.04
3298514 | 2-R+2 | 1.04
3298515 | 2-R+2 | 1.65
3298516 | 2-R+2 | 1.65
3298526 | 2-R+2 | 1.04
3298527 | 2-R+2 | 1.04
3298528 | 2-R+2 | 1.65
3298529 | 2-R+2 | 1.65
3298539 | 2-R+2 | 1.04
3298540 | 2-R+2 | 1.04
3298541 | 2-R+2 | 1.65
3298542 | 2-R+2 | 1.65
3298552 | 2-R+2 | 1.04
3298553 | 2-R+2 | 1.04
3298554 | 2-R+2 | 1.65
3298555 | 2-R+2 | 1.65
3298565 | 2-R+2 | 1.04
3298566 | 2-R+2 | 1.04
3298567 | 2-R+2 | 1.65
3298568 | 2-R+2 | 1.65
3298578 | 2-R+2 | 1.04
3298579 | 2-R+2 | 1.04
3298580 | 2-R+2 | 1.65
3298581 | 2-R+2 | 1.65
3298595 | 2-R+2 | 1.04
3298596 | 2-R+2 | 1.04
3298597 | 2-R+2 | 1.65
3298598 | 2-R+2 | 1.65
3298608 | 2-R+2 | 1.04
3298609 | 2-R+2 | 1.04
3298610 | 2-R+2 | 1.65
3298611 | 2-R+2 | 1.65
3298623 | 2-R+2 | 1.04
3298624 | 2-R+2 | 1.04
3298625 | 2-R+2 | 1.65
3298626 | 2-R+2 | 1.65
3298636 | 2-R+2 | 1.04
3298637 | 2-R+2 | 1.04
3298638 | 2-R+2 | 1.65
3298639 | 2-R+2 | 1.65
3298649 | 2-R+2 | 1.04
3298650 | 2-R+2 | 1.04
3298651 | 2-R+2 | 1.65
3298652 | 2-R+2 | 1.65
3299355 | 2-R+2 | 1.1997
3299356 | 2-R+2 | 1.1997
3299357 | 2-R+2 | 1.65
3299358 | 2-R+2 | 1.65
3299372 | 2-R+2 | 1.1997
3299373 | 2-R+2 | 1.1997
3299374 | 2-R+2 | 1.65
3299375 | 2-R+2 | 1.65
3299464 | 2-R+2 | 1.04
3299465 | 2-R+2 | 1.04
3299466 | 2-R+2 | 1.65
3299467 | 2-R+2 | 1.65
3299824 | 2-R+2 | 1.04
3299825 | 2-R+2 | 1.04
3299826 | 2-R+2 | 1.65
3299827 | 2-R+2 | 1.65
3299839 | 2-R+2 | 1.04
3299840 | 2-R+2 | 1.04
3299841 | 2-R+2 | 1.65
3299842 | 2-R+2 | 1.65
3299852 | 2-R+2 | 1.04
3299853 | 2-R+2 | 1.04
3299854 | 2-R+2 | 1.65
3299855 | 2-R+2 | 1.65
3299865 | 2-R+2 | 1.04
3299866 | 2-R+2 | 1.04
3299867 | 2-R+2 | 1.65
3299868 | 2-R+2 | 1.65
3299878 | 2-R+2 | 1.04
3299879 | 2-R+2 | 1.04
3299880 | 2-R+2 | 1.65
3299881 | 2-R+2 | 1.65
3299893 | 2-R+2 | 1.04
3299894 | 2-R+2 | 1.04
3299895 | 2-R+2 | 1.65
3299896 | 2-R+2 | 1.65
3299908 | 2-R+2 | 1.04
3299909 | 2-R+2 | 1.04
3299910 | 2-R+2 | 1.65
3299911 | 2-R+2 | 1.65
3299923 | 2-R+2 | 1.04
3299924 | 2-R+2 | 1.04
3299925 | 2-R+2 | 1.65
3299926 | 2-R+2 | 1.65
3299936 | 2-R+2 | 1.04
3299937 | 2-R+2 | 1.04
3299938 | 2-R+2 | 1.65
3299939 | 2-R+2 | 1.65
3299951 | 2-R+2 | 1.04
3299952 | 2-R+2 | 1.04
3299953 | 2-R+2 | 1.65
3299954 | 2-R+2 | 1.65
3299964 | 2-R+2 | 1.04
3299965 | 2-R+2 | 1.04
3299966 | 2-R+2 | 1.65
3299967 | 2-R+2 | 1.65
3299977 | 2-R+2 | 1.04
3299978 | 2-R+2 | 1.04
3299979 | 2-R+2 | 1.65
3299980 | 2-R+2 | 1.65
3299990 | 2-R+2 | 1.04
3299991 | 2-R+2 | 1.04
3299992 | 2-R+2 | 1.65
3299993 | 2-R+2 | 1.65
3300032 | 2-R+2 | 1.04
3300033 | 2-R+2 | 1.04
3300034 | 2-R+2 | 1.65
3300035 | 2-R+2 | 1.65
3300045 | 2-R+2 | 1.04
3300046 | 2-R+2 | 1.04
3300047 | 2-R+2 | 1.65
3300048 | 2-R+2 | 1.65
3300304 | 2-R+2 | 1.04
3300305 | 2-R+2 | 1.04
3300306 | 2-R+2 | 1.65
3300307 | 2-R+2 | 1.65
3300683 | 2-R+2 | 1.04
3300684 | 2-R+2 | 1.04
3300685 | 2-R+2 | 1.65
3300686 | 2-R+2 | 1.65
3300698 | 2-R+2 | 1.04
3300699 | 2-R+2 | 1.04
3300700 | 2-R+2 | 1.65
3300701 | 2-R+2 | 1.65
3300711 | 2-R+2 | 1.04
3300712 | 2-R+2 | 1.04
3300713 | 2-R+2 | 1.65
3300714 | 2-R+2 | 1.65
3300728 | 2-R+2 | 1.04
3300729 | 2-R+2 | 1.04
3300730 | 2-R+2 | 1.65
3300731 | 2-R+2 | 1.65
3300743 | 2-R+2 | 1.04
3300744 | 2-R+2 | 1.04
3300745 | 2-R+2 | 1.65
3300746 | 2-R+2 | 1.65
3300756 | 2-R+2 | 1.04
3300757 | 2-R+2 | 1.04
3300758 | 2-R+2 | 1.65
3300759 | 2-R+2 | 1.65
3300842 | 2-R+2 | 1.04
3300843 | 2-R+2 | 1.04
3300844 | 2-R+2 | 1.65
3300845 | 2-R+2 | 1.65
3300857 | 2-R+2 | 1.04
3300858 | 2-R+2 | 1.04
3300859 | 2-R+2 | 1.65
3300860 | 2-R+2 | 1.65
3300870 | 2-R+2 | 1.04
3300871 | 2-R+2 | 1.04
3300872 | 2-R+2 | 1.65
3300873 | 2-R+2 | 1.65
3300883 | 2-R+2 | 1.04
3300884 | 2-R+2 | 1.04
3300885 | 2-R+2 | 1.65
3300886 | 2-R+2 | 1.65
3300896 | 2-R+2 | 1.04
3300897 | 2-R+2 | 1.04
3300898 | 2-R+2 | 1.65
3300899 | 2-R+2 | 1.65
3300911 | 2-R+2 | 1.04
3300912 | 2-R+2 | 1.04
3300913 | 2-R+2 | 1.65
3300914 | 2-R+2 | 1.65
3300926 | 2-R+2 | 1.04
3300927 | 2-R+2 | 1.04
3300928 | 2-R+2 | 1.65
3300929 | 2-R+2 | 1.65
3300939 | 2-R+2 | 1.04
3300940 | 2-R+2 | 1.04
3300941 | 2-R+2 | 1.65
3300942 | 2-R+2 | 1.65
3300954 | 2-R+2 | 1.04
3300955 | 2-R+2 | 1.04
3300956 | 2-R+2 | 1.65
3300957 | 2-R+2 | 1.65
3301093 | 2-R+2 | 1.04
3301094 | 2-R+2 | 1.04
3301095 | 2-R+2 | 1.65
3301096 | 2-R+2 | 1.65
3301307 | 2-R+2 | 1.04
3301308 | 2-R+2 | 1.04
3301309 | 2-R+2 | 1.65
3301310 | 2-R+2 | 1.65
3301322 | 2-R+2 | 1.04
3301323 | 2-R+2 | 1.04
3301324 | 2-R+2 | 1.65
3301325 | 2-R+2 | 1.65
3301341 | 2-R+2 | 1.04
3301342 | 2-R+2 | 1.04
3301343 | 2-R+2 | 1.65
3301344 | 2-R+2 | 1.65
3301358 | 2-R+2 | 1.04
3301359 | 2-R+2 | 1.04
3301360 | 2-R+2 | 1.65
3301361 | 2-R+2 | 1.65
3301377 | 2-R+2 | 1.04
3301378 | 2-R+2 | 1.04
3301379 | 2-R+2 | 1.65
3301380 | 2-R+2 | 1.65
3301390 | 2-R+2 | 1.04
3301391 | 2-R+2 | 1.04
3301392 | 2-R+2 | 1.65
3301393 | 2-R+2 | 1.65
3301405 | 2-R+2 | 1.04
3301406 | 2-R+2 | 1.04
3301407 | 2-R+2 | 1.65
3301408 | 2-R+2 | 1.65
3301420 | 2-R+2 | 1.04
3301421 | 2-R+2 | 1.04
3301422 | 2-R+2 | 1.65
3301423 | 2-R+2 | 1.65
3301435 | 2-R+2 | 1.04
3301436 | 2-R+2 | 1.04
3301437 | 2-R+2 | 1.65
3301438 | 2-R+2 | 1.65
3301450 | 2-R+2 | 1.04
3301451 | 2-R+2 | 1.04
3301452 | 2-R+2 | 1.65
3301453 | 2-R+2 | 1.65
3301463 | 2-R+2 | 1.04
3301464 | 2-R+2 | 1.04
3301465 | 2-R+2 | 1.65
3301466 | 2-R+2 | 1.65
3301480 | 2-R+2 | 1.04
3301481 | 2-R+2 | 1.04
3301482 | 2-R+2 | 1.65
3301483 | 2-R+2 | 1.65
3301497 | 2-R+2 | 1.04
3301498 | 2-R+2 | 1.04
3301499 | 2-R+2 | 1.65
3301500 | 2-R+2 | 1.65
3301660 | 2-R+2 | 1.04
3301661 | 2-R+2 | 1.04
3301662 | 2-R+2 | 1.65
3301663 | 2-R+2 | 1.65
3301739 | 2-R+2 | 1.04
3301740 | 2-R+2 | 1.04
3301741 | 2-R+2 | 1.65
3301742 | 2-R+2 | 1.65
3301752 | 2-R+2 | 1.04
3301753 | 2-R+2 | 1.04
3301754 | 2-R+2 | 1.65
3301755 | 2-R+2 | 1.65
3301765 | 2-R+2 | 1.04
3301766 | 2-R+2 | 1.04
3301767 | 2-R+2 | 1.65
3301768 | 2-R+2 | 1.65
3301778 | 2-R+2 | 1.04
3301779 | 2-R+2 | 1.04
3301780 | 2-R+2 | 1.65
3301781 | 2-R+2 | 1.65
3301791 | 2-R+2 | 1.04
3301792 | 2-R+2 | 1.04
3301793 | 2-R+2 | 1.65
3301794 | 2-R+2 | 1.65
3301804 | 2-R+2 | 1.04
3301805 | 2-R+2 | 1.04
3301806 | 2-R+2 | 1.65
3301807 | 2-R+2 | 1.65
3301817 | 2-R+2 | 1.04
3301818 | 2-R+2 | 1.04
3301819 | 2-R+2 | 1.65
3301820 | 2-R+2 | 1.65
3301832 | 2-R+2 | 1.04
3301833 | 2-R+2 | 1.04
3301834 | 2-R+2 | 1.65
3301835 | 2-R+2 | 1.65
3301847 | 2-R+2 | 1.04
3301848 | 2-R+2 | 1.04
3301849 | 2-R+2 | 1.65
3301850 | 2-R+2 | 1.65
3301860 | 2-R+2 | 1.04
3301861 | 2-R+2 | 1.04
3301862 | 2-R+2 | 1.65
3301863 | 2-R+2 | 1.65
3301873 | 2-R+2 | 1.04
3301874 | 2-R+2 | 1.04
3301875 | 2-R+2 | 1.65
3301876 | 2-R+2 | 1.65
3302230 | 2-R+2 | 1.04
3302231 | 2-R+2 | 1.04
3302232 | 2-R+2 | 1.65
3302233 | 2-R+2 | 1.65
3302243 | 2-R+2 | 1.04
3302244 | 2-R+2 | 1.04
3302245 | 2-R+2 | 1.65
3302246 | 2-R+2 | 1.65
3302256 | 2-R+2 | 1.04
3302257 | 2-R+2 | 1.04
3302258 | 2-R+2 | 1.65
3302259 | 2-R+2 | 1.65
3302269 | 2-R+2 | 1.04
3302270 | 2-R+2 | 1.04
3302271 | 2-R+2 | 1.65
3302272 | 2-R+2 | 1.65
3302537 | 2-R+2 | 1.04
3302538 | 2-R+2 | 1.04
3302539 | 2-R+2 | 1.65
3302540 | 2-R+2 | 1.65
3302806 | 2-R+2 | 1.04
3302807 | 2-R+2 | 1.04
3302808 | 2-R+2 | 1.65
3302809 | 2-R+2 | 1.65
3302821 | 2-R+2 | 1.04
3302822 | 2-R+2 | 1.04
3302823 | 2-R+2 | 1.65
3302824 | 2-R+2 | 1.65
3302834 | 2-R+2 | 1.04
3302835 | 2-R+2 | 1.04
3302836 | 2-R+2 | 1.65
3302837 | 2-R+2 | 1.65
3302855 | 2-R+2 | 1.04
3302856 | 2-R+2 | 1.04
3302857 | 2-R+2 | 1.65
3302858 | 2-R+2 | 1.65
3302870 | 2-R+2 | 1.04
3302871 | 2-R+2 | 1.04
3302872 | 2-R+2 | 1.65
3302873 | 2-R+2 | 1.65
3302883 | 2-R+2 | 1.04
3302884 | 2-R+2 | 1.04
3302885 | 2-R+2 | 1.65
3302886 | 2-R+2 | 1.65
3302900 | 2-R+2 | 1.04
3302901 | 2-R+2 | 1.04
3302902 | 2-R+2 | 1.65
3302903 | 2-R+2 | 1.65
3302913 | 2-R+2 | 1.04
3302914 | 2-R+2 | 1.04
3302915 | 2-R+2 | 1.65
3302916 | 2-R+2 | 1.65
3302930 | 2-R+2 | 1.04
3302931 | 2-R+2 | 1.04
3302932 | 2-R+2 | 1.65
3302933 | 2-R+2 | 1.65
3302943 | 2-R+2 | 1.04
3302944 | 2-R+2 | 1.04
3302945 | 2-R+2 | 1.65
3302946 | 2-R+2 | 1.65
3303135 | 2-R+2 | 1.04
3303136 | 2-R+2 | 1.04
3303137 | 2-R+2 | 1.65
3303138 | 2-R+2 | 1.65
3303150 | 2-R+2 | 1.04
3303151 | 2-R+2 | 1.04
3303152 | 2-R+2 | 1.65
3303153 | 2-R+2 | 1.65
3303165 | 2-R+2 | 1.04
3303166 | 2-R+2 | 1.04
3303167 | 2-R+2 | 1.65
3303168 | 2-R+2 | 1.65
3303180 | 2-R+2 | 1.04
3303181 | 2-R+2 | 1.04
3303182 | 2-R+2 | 1.65
3303183 | 2-R+2 | 1.65
3303201 | 2-R+2 | 1.04
3303202 | 2-R+2 | 1.04
3303203 | 2-R+2 | 1.65
3303204 | 2-R+2 | 1.65
3303214 | 2-R+2 | 1.04
3303215 | 2-R+2 | 1.04
3303216 | 2-R+2 | 1.65
3303217 | 2-R+2 | 1.65
3303227 | 2-R+2 | 1.04
3303228 | 2-R+2 | 1.04
3303229 | 2-R+2 | 1.65
3303230 | 2-R+2 | 1.65
3303242 | 2-R+2 | 1.04
3303243 | 2-R+2 | 1.04
3303244 | 2-R+2 | 1.65
3303245 | 2-R+2 | 1.65
3303255 | 2-R+2 | 1.04
3303256 | 2-R+2 | 1.04
3303257 | 2-R+2 | 1.65
3303258 | 2-R+2 | 1.65
3303492 | 2-R+2 | 1.04
3303493 | 2-R+2 | 1.04
3303494 | 2-R+2 | 1.65
3303495 | 2-R+2 | 1.65
3303507 | 2-R+2 | 1.04
3303508 | 2-R+2 | 1.04
3303509 | 2-R+2 | 1.65
3303510 | 2-R+2 | 1.65
3303520 | 2-R+2 | 1.04
3303521 | 2-R+2 | 1.04
3303522 | 2-R+2 | 1.65
3303523 | 2-R+2 | 1.65
3303541 | 2-R+2 | 1.04
3303542 | 2-R+2 | 1.04
3303543 | 2-R+2 | 1.65
3303544 | 2-R+2 | 1.65
3303560 | 2-R+2 | 1.04
3303561 | 2-R+2 | 1.04
3303562 | 2-R+2 | 1.65
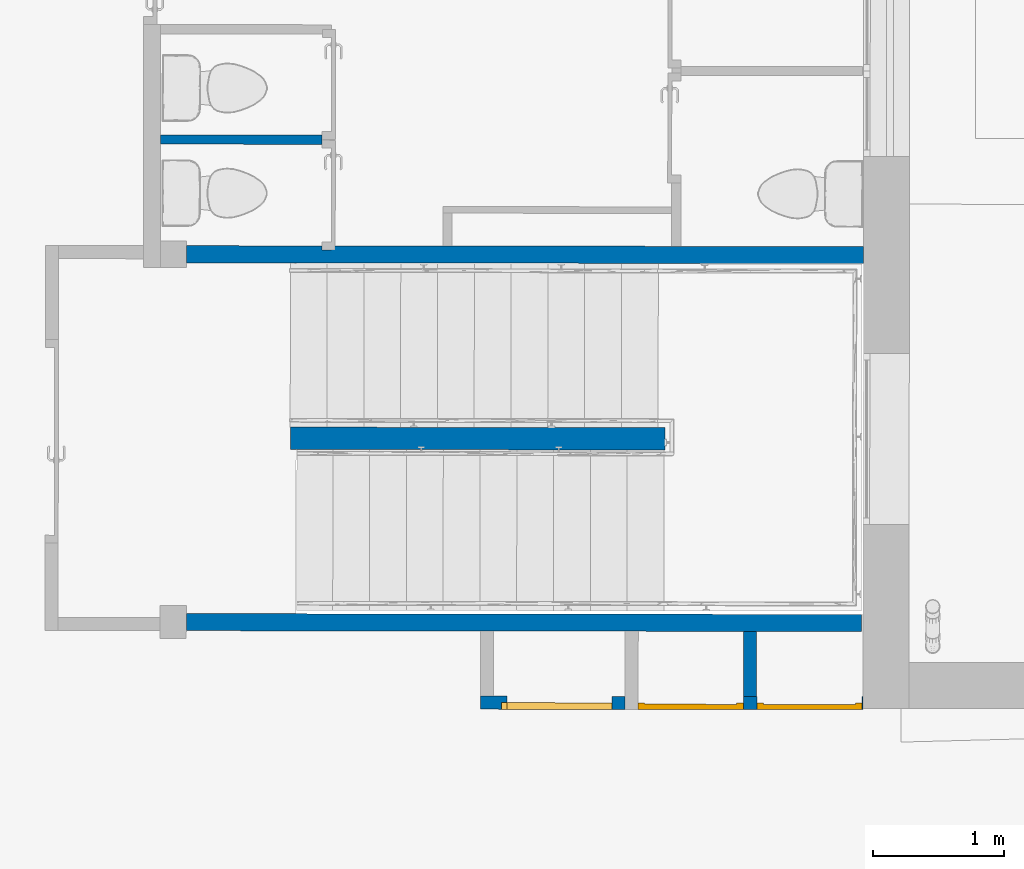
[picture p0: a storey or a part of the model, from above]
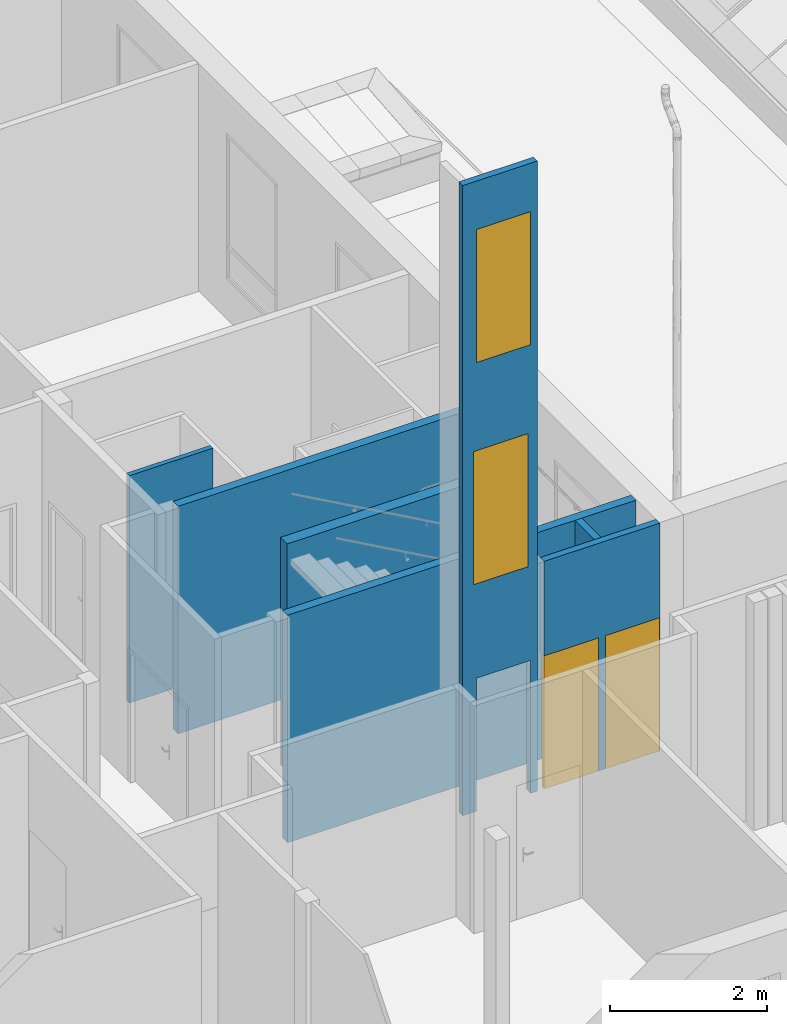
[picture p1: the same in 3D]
Properties of the parts of a building model (IFC2X3), part 3 of 4

# IfcMember: Meneau rectangulaire:50x50 (1724)
Name (Meneau rectangulaire:50x50:...) | In | Span (m)
3303563 | 2-R+2 | 1.65
3303573 | 2-R+2 | 1.04
3303574 | 2-R+2 | 1.04
3303575 | 2-R+2 | 1.65
3303576 | 2-R+2 | 1.65
3303586 | 2-R+2 | 1.04
3303587 | 2-R+2 | 1.04
3303588 | 2-R+2 | 1.65
3303589 | 2-R+2 | 1.65
3303601 | 2-R+2 | 1.04
3303602 | 2-R+2 | 1.04
3303603 | 2-R+2 | 1.65
3303604 | 2-R+2 | 1.65
3303618 | 2-R+2 | 1.04
3303619 | 2-R+2 | 1.04
3303620 | 2-R+2 | 1.65
3303621 | 2-R+2 | 1.65
3303631 | 2-R+2 | 1.04
3303632 | 2-R+2 | 1.04
3303633 | 2-R+2 | 1.65
3303634 | 2-R+2 | 1.65
3303861 | 2-R+2 | 1.04
3303862 | 2-R+2 | 1.04
3303863 | 2-R+2 | 1.65
3303864 | 2-R+2 | 1.65
3303880 | 2-R+2 | 1.04
3303881 | 2-R+2 | 1.04
3303882 | 2-R+2 | 1.65
3303883 | 2-R+2 | 1.65
4317777 | Rez de Rue Simon | 0.841047
4317778 | Rez de Rue Simon | 0.848148
4317779 | Rez de Rue Simon | 0.9
4317780 | Rez de Rue Simon | 0.9
4318290 | Rez de Rue Simon | 0.843787
4318291 | Rez de Rue Simon | 0.841047
4318355 | Rez de Rue Simon | 0.848148
4318356 | Rez de Rue Simon | 0.843787
4318372 | Rez de Rue Simon | 0.9
4318373 | Rez de Rue Simon | 0.9
4317908 | Rez de Rue Simon | 0.842672
4317910 | Rez de Rue Simon | 0.9
4318239 | Rez de Rue Simon | 0.842672
4318240 | Rez de Rue Simon | 0.84208
4318383 | Rez de Rue Simon | 0.9
4724971 | Rez de Rue Simon | 0.84005
4725107 | Rez de Rue Simon | 0.9
4730075 | Rez de Rue Simon | 0.84208
4730076 | Rez de Rue Simon | 0.843265
4730112 | Rez de Rue Simon | 0.843265
4730113 | Rez de Rue Simon | 0.84005
4730142 | Rez de Rue Simon | 0.9
4318024 | Rez de Rue Simon | 0.842672
4318025 | Rez de Rue Simon | 0.842672
4318026 | Rez de Rue Simon | 0.9
4318027 | Rez de Rue Simon | 0.9
4318074 | Rez de Rue Simon | 0.842672
4318075 | Rez de Rue Simon | 0.842672
4318141 | Rez de Rue Simon | 0.842672
4318142 | Rez de Rue Simon | 0.842672
4318391 | Rez de Rue Simon | 0.9
4318392 | Rez de Rue Simon | 0.9
4667427 | 0- Rdc | 0.65
4667428 | 0- Rdc | 0.65
4667429 | 0- Rdc | 0.47
4667430 | 0- Rdc | 1.71
4667433 | 0- Rdc | 1.71
4667434 | 0- Rdc | 0.47
4667435 | 0- Rdc | 0.55
4667594 | 1-R+1 | 0.649696
4667595 | 1-R+1 | 0.649696
4667596 | 1-R+1 | 0.47
4667597 | 1-R+1 | 1.71
4667600 | 1-R+1 | 1.71
4667601 | 1-R+1 | 0.47
4667602 | 1-R+1 | 0.549696
4667605 | 1-R+1 | 0.65
4667606 | 1-R+1 | 0.65
4667607 | 1-R+1 | 0.47
4667608 | 1-R+1 | 1.71
4667611 | 1-R+1 | 1.71
4667612 | 1-R+1 | 0.47
4667613 | 1-R+1 | 0.55

# IfcMember: Meneau rectangulaire:50x50 Int (102)
Type - PredefinedType: MULLION; Material: OMD_Bois Men Int
Pset_MemberCommon - Reference: 50x50 Int
Pset_QuantityTakeOff - Reference: 50x50 Int
Name (Meneau rectangulaire:50x50 Int:...) | In | IsExternal | Span (m)
4749647 | 0- Rdc | yes | 1.735
4749648 | 1-R+1 | yes | 1.735
4749640 | 1-R+1 | yes | 1.735
4749872 | 2-R+2 | yes | 1.55
4140119 | rez de rue -1.10m | yes | 1
4140121 | rez de rue -1.10m | yes | 1
4140122 | rez de rue -1.10m | yes | 0.39
4141734 | rez de rue -1.10m | yes | 1
4142432 | rez de rue -1.10m | yes | 1
4142608 | rez de rue -1.10m | yes | 0.39
4142609 | rez de rue -1.10m | yes | 0.46
4142618 | rez de rue -1.10m | yes | 0.39
4142774 | rez de rue -1.10m | yes | 0.925
4697976 | rez de rue -1.10m | yes | 0.46
4697977 | rez de rue -1.10m | yes | 0.5
4697984 | rez de rue -1.10m | yes | 0.46
4698025 | rez de rue -1.10m | yes | 0.5
4698026 | rez de rue -1.10m | yes | 1.1
4698033 | rez de rue -1.10m | yes | 0.5
4723206 | rez de rue -1.10m | yes | 1
4723275 | rez de rue -1.10m | yes | 0.5
4723276 | rez de rue -1.10m | yes | 0.46
4723277 | rez de rue -1.10m | yes | 0.39
4723278 | rez de rue -1.10m | yes | 1
4279757 | rez de rue -1.10m | yes | 1
4279759 | rez de rue -1.10m | yes | 1.1
4279760 | rez de rue -1.10m | yes | 0.39
4282101 | rez de rue -1.10m | yes | 1
4282121 | rez de rue -1.10m | yes | 1
4698127 | rez de rue -1.10m | yes | 0.46
4698128 | rez de rue -1.10m | yes | 0.5
4698136 | rez de rue -1.10m | yes | 0.46
4698285 | rez de rue -1.10m | yes | 0.5
4698286 | rez de rue -1.10m | yes | 1
4698293 | rez de rue -1.10m | yes | 0.5
4722912 | rez de rue -1.10m | yes | 1
4723385 | rez de rue -1.10m | yes | 0.5
4723386 | rez de rue -1.10m | yes | 0.46
4723387 | rez de rue -1.10m | yes | 1
4723430 | rez de rue -1.10m | yes | 0.39
4723431 | rez de rue -1.10m | yes | 0.46
4723435 | rez de rue -1.10m | yes | 0.39
4723436 | rez de rue -1.10m | yes | 0.39
4723475 | rez de rue -1.10m | yes | 0.925
4723577 | rez de rue -1.10m | yes | 1
4723578 | rez de rue -1.10m | yes | 1
4723579 | rez de rue -1.10m | yes | 0.39
4723582 | rez de rue -1.10m | yes | 1
4723586 | rez de rue -1.10m | yes | 1
4723592 | rez de rue -1.10m | yes | 0.39
4723593 | rez de rue -1.10m | yes | 0.46
4723594 | rez de rue -1.10m | yes | 0.925
4723599 | rez de rue -1.10m | yes | 0.46
4723600 | rez de rue -1.10m | yes | 0.5
4723605 | rez de rue -1.10m | yes | 0.45
4723606 | rez de rue -1.10m | yes | 0.173333
4723611 | rez de rue -1.10m | yes | 1.1
4723616 | rez de rue -1.10m | yes | 0.266667
4723617 | rez de rue -1.10m | yes | 0.266667
4723618 | rez de rue -1.10m | yes | 0.266667
4723620 | rez de rue -1.10m | yes | 0.5
4723621 | rez de rue -1.10m | yes | 0.5
4723622 | rez de rue -1.10m | yes | 0.45
4723623 | rez de rue -1.10m | yes | 0.39
4723624 | rez de rue -1.10m | yes | 1
4723625 | rez de rue -1.10m | yes | 0.5
4723626 | rez de rue -1.10m | yes | 0.46
4723627 | rez de rue -1.10m | yes | 0.39
4723628 | rez de rue -1.10m | yes | 1
4723996 | rez de rue -1.10m | yes | 1
4723997 | rez de rue -1.10m | yes | 1
4723998 | rez de rue -1.10m | yes | 0.39
4724001 | rez de rue -1.10m | yes | 1
4724005 | rez de rue -1.10m | yes | 1
4724006 | rez de rue -1.10m | yes | 1
4724012 | rez de rue -1.10m | yes | 0.39
4724013 | rez de rue -1.10m | yes | 0.46
4724014 | rez de rue -1.10m | yes | 0.925
4724019 | rez de rue -1.10m | yes | 0.46
4724020 | rez de rue -1.10m | yes | 0.5
4724025 | rez de rue -1.10m | yes | 0.24
4724026 | rez de rue -1.10m | yes | 0.24
4724027 | rez de rue -1.10m | yes | 0.24
4724032 | rez de rue -1.10m | yes | 0.41
4724033 | rez de rue -1.10m | yes | 0.16
4724038 | rez de rue -1.10m | yes | 1.1
4724039 | rez de rue -1.10m | yes | 0.5
4724041 | rez de rue -1.10m | yes | 0.5
4724042 | rez de rue -1.10m | yes | 0.41
4724043 | rez de rue -1.10m | yes | 0.39
4724044 | rez de rue -1.10m | yes | 0.46
4724045 | rez de rue -1.10m | yes | 0.5
4724046 | rez de rue -1.10m | yes | 0.39
4724047 | rez de rue -1.10m | yes | 1
5333560 | R-1 | no | 0.9
5333561 | R-1 | no | 0.9
5333562 | R-1 | no | 1
5333563 | R-1 | no | 1
5334332 | R-1 | no | 0.9
5334333 | R-1 | no | 0.9
5334334 | R-1 | no | 1
5334335 | R-1 | no | 1

# IfcMember: Meneau rectangulaire:50x50 Int anthracite (50)
In: rez de rue -1.10m
Type - PredefinedType: MULLION; Material: OMD_Bois Men Int anthracite
Pset_MemberCommon - IsExternal: yes; Reference: 50x50 Int anthracite
Pset_QuantityTakeOff - Reference: 50x50 Int anthracite
Name (Meneau rectangulaire:50x50 Int anthracite:...) | Span (m)
3665533 | 0.785187
3665535 | 1.1
3665536 | 0.63
3665977 | 0.45
3666107 | 0.45
3666152 | 0.786519
3666211 | 0.703438
3666254 | 0.625
3666311 | 1.90625
3666396 | 0.625
3666412 | 1
3666420 | 1
3666427 | 1
3666434 | 1
3666440 | 1.1
3666447 | 1
3666454 | 1
3666461 | 1
3667129 | 0.700155
3667828 | 0.63
3667829 | 0.46
3667837 | 0.63
3667838 | 0.63
3667839 | 0.63
3667840 | 0.63
3667841 | 0.63
3667842 | 0.63
3667843 | 0.63
3667844 | 0.63
3667915 | 1.85625
4907601 | 0.5
4907602 | 1.1
4907607 | 0.5
4907608 | 0.5
4907609 | 0.5
4907610 | 0.5
4907611 | 0.5
4907612 | 0.5
4907613 | 0.5
4907614 | 0.5
4907676 | 0.46
4907677 | 0.5
4907684 | 0.46
4907685 | 0.46
4907686 | 0.46
4907687 | 0.46
4907688 | 0.46
4907689 | 0.46
4907690 | 0.46
4907691 | 0.46

# IfcMember: Meneau rectangulaire:50x50 beige, Meneau rectangulaire:50x50 beige:4777226
In: 0- Rdc
Type - PredefinedType: MULLION; Material: OMD-RAL 1015
Pset_MemberCommon - IsExternal: yes; Reference: 50x50 beige; Span: 1.735 m
Pset_QuantityTakeOff - Reference: 50x50 beige

# IfcMember: Meneau rectangulaire:5x20 métalique bleu (51)
In: Rez de Rue Simon
Type - PredefinedType: MULLION; Material: OMD_ anthracite
Pset_MemberCommon - IsExternal: yes; Reference: 5x20 métalique bleu; Span: 0.46 m
Pset_QuantityTakeOff - Reference: 5x20 métalique bleu
Name (Meneau rectangulaire:5x20 métalique bleu:...)
4053563
4053570
4053573
4053574
4053575
4053576
4053577
4053578
4053582
4055745
4055747
4055748
4055749
4055752
4055753
4055754
4055755
4056926
4056927
4056928
4056929
4056930
4056931
4056932
4056933
4056934
4056953
4056954
4056955
4056956
4056957
4056958
4056959
4056960
4057024
4057025
4057026
4057027
4057028
4057029
4057030
4057031
4057032
4057051
4057052
4057053
4057054
4057055
4057056
4057057
4057058

# IfcMember: Meneau rectangulaire:HT 100x50 Int anthracite 2 (8)
In: rez de rue -1.10m
Type - PredefinedType: MULLION; Material: OMD_Bois Men Int anthracite
Pset_MemberCommon - IsExternal: yes; Reference: HT 100x50 Int anthracite 2
Pset_QuantityTakeOff - Reference: HT 100x50 Int anthracite 2
Name (Meneau rectangulaire:HT 100x50 Int anthracite 2:...) | Span (m)
3665534 | 0.736519
3665978 | 0.735187
3666033 | 0.45
3666108 | 0.703438
3666153 | 0.45
3666212 | 0.6
3666312 | 0.65
3667130 | 0.700155

# IfcMember: Meneau rectangulaire:ht 100x50 (8)
In: rez de rue -1.10m
Type - PredefinedType: MULLION; Material: OMD_Bois Men Int
Pset_MemberCommon - IsExternal: yes; Reference: ht 100x50
Pset_QuantityTakeOff - Reference: ht 100x50
Name (Meneau rectangulaire:ht 100x50:...) | Span (m)
4141735 | 1.025
4723207 | 1
4279758 | 1
4282102 | 1.025
4723583 | 1
4723587 | 1.025
4724002 | 1.025
4724007 | 1

# IfcOpeningElement: Opening (416)
Name | In | Reference | sets with these values
8 x Mur de base:MUR 35:3227843 | 0- Rdc | Menuiserie Ext 1F+1OB VERTIC | 2
Mur de base:MUR 26:3227899:1 | 0- Rdc | MUR 26 | 2
9 x Mur de base:MUR 35:3227989 | 0- Rdc | Menuiserie Ext 1F+1OB VERTIC | 2
7 x Mur de base:MUR 35:3227997 | 0- Rdc | Menuiserie Ext 2OF+1F VERTIC | 2
2 x Sol:Dalle 20:239263 | 0- Rdc | Dalle 20 | 2
Mur de base:MUR 15:3230399 | 0- Rdc | 80x204 | 2
Mur de base:MUR 15:3230399 | 0- Rdc | OMD - Baie libre | 2
Mur de base:MUR 15:3230403 | 0- Rdc | OMD - Baie libre | 2
Mur de base:MUR 10:3230552 | 0- Rdc | 80x204 | 2
Mur de base:MUR 10:3230687 | 0- Rdc | 136x204 | 2
Mur de base:MUR 10:3232841 | 0- Rdc | 80x204 | 2
Mur de base:MUR 10:3232851 | 0- Rdc | 80x204 | 2
Mur de base:MUR 13:3233919 | 0- Rdc | 70X204 | 2
Mur de base:MUR 10:3234887 | 0- Rdc | 80X204 | 2
Mur de base:MUR 7:3235074 | 0- Rdc | 70X204 | 2
Mur de base:MUR 10:3238699 | 0- Rdc | 80x204 | 2
Mur de base:MUR 10:3238703 | 0- Rdc | 80x204 | 2
Mur de base:MUR 10:3238869 | 0- Rdc | 80x204 | 2
Mur de base:MUR 10:3238891 | 0- Rdc | 80x204 | 2
Mur de base:MUR 10:3239367 | 0- Rdc | 80x204 | 2
Mur de base:MUR 10:3250338 | 0- Rdc | Menuiserie Ext 1F+1OB VERTIC | 2
2 x Sol:Dalle 20:239263 | 1-R+1 | Dalle 20 | 2
2 x Mur de base:MUR 7:3255219 | Rez de Rue Simon | 60X204 | 2
Mur de base:MUR 7:3255223:1 | Rez de Rue Simon | MUR 7 | 2
Mur de base:MUR 30:3256956 | Rez de Rue Simon | double 180x204 | 2
Mur de base:MUR 30:3256956 | Rez de Rue Simon | 80x204 | 2
8 x Mur de base:MUR 30:3256956 | Rez de Rue Simon | Menuiserie Ext 1F+1OB VERTIC | 2
8 x Mur de base:MUR 35:3256962 | Rez de Rue Simon | Menuiserie Ext 1F+1OB VERTIC | 2
Mur de base:MUR 35:3256962 | Rez de Rue Simon | 80x204 | 2
Mur de base:MUR 35:3256962 | Rez de Rue Simon | 140x204 | 2
Mur de base:MUR 10:3261059 | 0- Rdc | Menuiserie Ext 1F+1OB VERTIC | 2
Mur de base:MUR 10:3261062 | 0- Rdc | Menuiserie Ext 1F+1OB VERTIC | 2
Mur de base:MUR 10:3263579 | Rez de Rue Simon | Menuiserie Ext 1F+1OB VERTIC | 2
Mur de base:MUR 10:3263677 | 0- Rdc | Menuiserie Ext 1F+1OB VERTIC | 2
Mur de base:MUR 49.5:3265371 | Rez de Rue Simon | 80x204 | 2
2 x Mur de base:MUR 49.5:4816864 | Rez de Rue Simon | MUR 49.5 | 2
Mur de base:MUR 10:3265524 | Rez de Rue Simon | 70X204 | 2
Mur de base:Cloison 70mm:3267391 | Rez de Rue Simon | 80x204 | 2
Mur de base:MUR 10:3273200 | R-1 | 100x100 | 2
Mur de base:MUR 13:3273248 | R-1 | 140x204 | 2
Mur de base:MUR 20:3273914:1 | R-1 | MUR 20 | 2
Mur de base:MUR 13:3277078:1 | R-1 | MUR 13 | 2
Mur de base:MUR 13:3277079 | R-1 | 80x204 | 2
Mur de base:MUR 20:3277340:1 | R-1 | MUR 20 | 2
Mur de base:MUR 20:3277340:2 | R-1 | MUR 20 | 2
Mur de base:MUR 10:3277680:1 | R-1 | MUR 10 | 2
Mur de base:MUR 35:3294419 | 1-R+1 | Menuiserie Ext 1F+1OB VERTIC | 2
8 x Mur de base:MUR 35:3294420 | 1-R+1 | Menuiserie Ext 1F+1OB VERTIC | 2
Mur de base:MUR 35:3294421:1 | 1-R+1 | MUR 35 | 2
Mur de base:MUR 35:3294421:2 | 1-R+1 | MUR 35 | 2
Mur de base:MUR 35:3294421:3 | 1-R+1 | MUR 35 | 2
Mur de base:MUR 35:3294421:4 | 1-R+1 | MUR 35 | 2
Mur de base:MUR 35:3294421:5 | 1-R+1 | MUR 35 | 2
Mur de base:MUR 35:3294421:6 | 1-R+1 | MUR 35 | 2
Mur de base:MUR 35:3294421:7 | 1-R+1 | MUR 35 | 2
Mur de base:MUR 35:3294421:8 | 1-R+1 | MUR 35 | 2
Mur de base:MUR 35:3294421:9 | 1-R+1 | MUR 35 | 2
Mur de base:MUR 35:3294421:10 | 1-R+1 | MUR 35 | 2
Mur de base:MUR 35:3294421:11 | 1-R+1 | MUR 35 | 2
Mur de base:MUR 35:3294421:12 | 1-R+1 | MUR 35 | 2
Mur de base:MUR 35:3294421:13 | 1-R+1 | MUR 35 | 2
Mur de base:MUR 35:3294421:14 | 1-R+1 | MUR 35 | 2
Mur de base:MUR 35:3294421:15 | 1-R+1 | MUR 35 | 2
Mur de base:MUR 35:3294421:16 | 1-R+1 | MUR 35 | 2
Mur de base:MUR 35:3294421:17 | 1-R+1 | MUR 35 | 2
8 x Mur de base:MUR 35:3294422 | 1-R+1 | Menuiserie Ext 1F+1OB VERTIC | 2
Mur de base:MUR 35:3294423:1 | 1-R+1 | MUR 35 | 2
Mur de base:MUR 35:3294423:2 | 1-R+1 | MUR 35 | 2
Mur de base:MUR 35:3294423:3 | 1-R+1 | MUR 35 | 2
Mur de base:MUR 35:3294423:4 | 1-R+1 | MUR 35 | 2
Mur de base:MUR 35:3294423:5 | 1-R+1 | MUR 35 | 2
Mur de base:MUR 35:3294423:6 | 1-R+1 | MUR 35 | 2
Mur de base:MUR 35:3294423:7 | 1-R+1 | MUR 35 | 2
Mur de base:MUR 35:3294423:8 | 1-R+1 | MUR 35 | 2
Mur de base:MUR 35:3294423:9 | 1-R+1 | MUR 35 | 2
Mur de base:MUR 35:3294423:10 | 1-R+1 | MUR 35 | 2
Mur de base:MUR 35:3294423:11 | 1-R+1 | MUR 35 | 2
Mur de base:MUR 35:3294424:1 | 1-R+1 | MUR 35 | 2
9 x Mur de base:MUR 35:3294425 | 1-R+1 | Menuiserie Ext 1F+1OB VERTIC | 2
7 x Mur de base:MUR 35:3294426 | 1-R+1 | Menuiserie Ext 1F+1OB VERTIC | 2
Mur de base:MUR 10:3296980 | 1-R+1 | 136x204 | 2
Mur de base:MUR 30:3297107 | 2-R+2 | Menuiserie Ext 1F+1OB VERTIC | 2
16 x Mur de base:MUR 30:3297108 | 2-R+2 | Menuiserie Ext 1F+1OB VERTIC | 2
16 x Mur de base:MUR 30:3297110 | 2-R+2 | Menuiserie Ext 1F+1OB VERTIC | 2
16 x Mur de base:MUR 30:3297113 | 2-R+2 | Menuiserie Ext 1F+1OB VERTIC | 2
14 x Mur de base:MUR 30:3297114 | 2-R+2 | Menuiserie Ext 1F+1OB VERTIC | 2
Sol:corniche:3298972 | 2-R+2 | corniche | 2
2 x Sol:Dalle 20:239263 | 2-R+2 | Dalle 20 | 2
Sol:corniche 2:3306717 | 3-Combles | corniche 2 | 2
Mur de base:MUR 13:3326610 | Rez de Rue Simon | 93x204 | 2
Mur de base:MUR 13:3326610 | Rez de Rue Simon | 80x204 | 2
Mur de base:MUR 13:3326611 | Rez de Rue Simon | 80x204 | 2
Mur de base:MUR 13:3326611 | Rez de Rue Simon | 93x204 | 2
Mur de base:Cloison 100mm CF1h:3375893 | rez de rue -1.10m | 140x204 +occulus | 2
Mur de base:MUR 13:3469219 | Rez de Rue Simon | 1.43m x 2.04m | 2
3 x Mur de base:joue plâtre:3498601 | Rez de Rue Simon | Menuiserie Int | 2
3 x Mur de base:Cloison 120mm CF1h:5332358 | rez de rue -1.10m | Cloison 120mm CF1h | 2
Mur de base:Cloison bois:3572526 | rez de rue -1.10m | 2520x 1000mm | 2
4 x Mur de base:Cloison bois:3559356 | rez de rue -1.10m | Cloison bois | 2
Mur de base:Cloison bois:3572680 | rez de rue -1.10m | 3370x 1000mm | 2
Mur de base:Cloison 100mm CF1h:3607132 | R-1 | 100x100 | 2
Mur de base:Cloison 100mm CF1h:3800630 | R-1 | Trappe | 2
2 x Mur de base:ITI 120mm+BA13 vide 5cm:5295547 | Rez de Rue Simon | ITI 120mm+BA13 vide 5cm | 2
Mur de base:Cloison 100mm:4035082 | 0- Rdc | 80X204 | 2
2 x Mur de base:Cloison 100mm CF1h:4138279 | rez de rue -1.10m | Menuiserie Int | 2
Mur de base:ITI85+ba13:4165247 | Rez de Rue Simon | 93x204 | 2
Mur de base:MUR 30:4204240 | R-1 | 0915 x 2134mm | 2
Mur de base:MUR 30:4204241 | R-1 | 0915 x 2134mm | 2
Mur de base:faïence SANITAIRES:4210743:1 | Rez de Rue Simon | faïence SANITAIRES | 2
Mur de base:faïence SANITAIRES:4210743:2 | Rez de Rue Simon | faïence SANITAIRES | 2
Mur de base:faïence SANITAIRES:4210972:1 | Rez de Rue Simon | faïence SANITAIRES | 2
2 x Mur de base:faïence SANITAIRES:4210646 | Rez de Rue Simon | faïence SANITAIRES | 2
4 x Mur de base:faïence douches:4292241 | rez de rue -1.10m | faïence douches | 2
3 x Mur de base:MUR 5 PIERRE:4312346 | Rez de Rue Simon | MUR 5 PIERRE | 2
Mur de base:MUR 35:4895833:1 | 0- Rdc | MUR 35 | 2
Mur de base:MUR 35:4895833:2 | 0- Rdc | MUR 35 | 2
Mur de base:MUR 35:4895833:3 | 0- Rdc | MUR 35 | 2
Mur de base:MUR 35:4895833:4 | 0- Rdc | MUR 35 | 2
Mur de base:MUR 35:4895833:5 | 0- Rdc | MUR 35 | 2
Mur de base:MUR 35:4895833:6 | 0- Rdc | MUR 35 | 2
Mur de base:MUR 35:4895833:7 | 0- Rdc | MUR 35 | 2
Mur de base:MUR 35:4895833:8 | 0- Rdc | MUR 35 | 2
Mur de base:MUR 35:4896983:1 | 0- Rdc | MUR 35 | 2
Sol:Dalle 162:3688578 | Rez de Rue Simon | Dalle 162 | 2
OMD_Porte 2V tunnel:double 140x204:3229246:1 | 0- Rdc
OMD_Porte 1V tunnel:80x204:3231644:1 | 0- Rdc
OMD_Porte 1V tunnel:80x204:3231591:1 | 0- Rdc
OMD_Porte 1V tunnel:80x204:3231764:1 | 0- Rdc
OMD_Porte 1V tunnel:80x204:3231482:1 | 0- Rdc
OMD_Porte 1V tunnel:80x204:3231686:1 | 0- Rdc
OMD_Porte 1V tunnel:80x204:3231909:1 | 0- Rdc
OMD_Porte 1V tunnel:80x204:3231947:1 | 0- Rdc
OMD_Porte 1V tunnel:80x204:3231793:1 | 0- Rdc
OMD_Porte 1V tunnel:80x204:3231849:1 | 0- Rdc
OMD_Porte 1V tunnel:80x204:3231995:1 | 0- Rdc
OMD_Porte 1V tunnel:80x204:3232034:1 | 0- Rdc
OMD_Porte 2V tunnel:140x204:3232291:1 | 0- Rdc
Mur de base:MUR 13:3230407 | 0- Rdc
Mur de base:MUR 15:3230439 | 0- Rdc
Grz_Placard 1V:80X204:3238035:1 | 0- Rdc
Grz_Placard 1V:80X204:3238078:1 | 0- Rdc
OMD_Porte 1V tunnel:80x204:3238131:1 | 0- Rdc
OMD_Porte 1V tunnel:80x204:3232161:1 | 0- Rdc
OMD_Porte 1V tunnel:80x204:3232368:1 | 0- Rdc
OMD_Porte 1V tunnel:80x204:3232412:1 | 0- Rdc
OMD_Porte 1V tunnel:80x204:3232451:1 | 0- Rdc
OMD_Porte 2V tunnel:136x204:3230876:1 | 0- Rdc
OMD_Porte 1V tunnel:80x204:3232497:1 | 0- Rdc
OMD_Porte 1V tunnel:80x204:3232786:1 | 0- Rdc
OMD_Porte 2V tunnel:140x204:3232753:1 | 0- Rdc
OMD_Porte 1V tunnel:80x204:3232856:1 | 0- Rdc
OMD_Porte 1V tunnel:80x204:3233002:1 | 0- Rdc
OMD_Porte 1V tunnel:80x204:3233087:1 | 0- Rdc
OMD_Porte 1V tunnel:80x204:3233126:1 | 0- Rdc
OMD_Porte 1V tunnel:80x204:3233646:1 | 0- Rdc
OMD_Porte 1V tunnel:80x204:3233674:1 | 0- Rdc
OMD_Porte 1V tunnel:80x204:3233712:1 | 0- Rdc
OMD_Porte 1V tunnel:80x204:3233755:1 | 0- Rdc
OMD_Porte 1V tunnel:80x204:3233830:1 | 0- Rdc
OMD_Porte 1V tunnel:80x204:3233864:1 | 0- Rdc
OMD_Porte 1V tunnel:80x204:3234995:1 | 0- Rdc
OMD_Porte 2V tunnel:140x204:3234919:1 | 0- Rdc
Grz_Placard 1V:80X204:3237916:1 | 0- Rdc
Grz_Placard 1V:80X204:3237959:1 | 0- Rdc
OMD_Porte 1V tunnel:70X204:3236512:1 | 0- Rdc
OMD_Porte 1V tunnel:70X204:3236555:1 | 0- Rdc
OMD_Porte 1V tunnel:80x204:3236409:1 | 0- Rdc
OMD_Porte 1V tunnel:70X204:3236455:1 | 0- Rdc
OMD_Porte 1V tunnel:80x204:3238283:1 | 0- Rdc
OMD_Porte 1V tunnel:80x204:3238304:1 | 0- Rdc
OMD_Porte 1V tunnel:80x204:3238455:1 | 0- Rdc
OMD_Porte 2V tunnel:140x204:3238388:1 | 0- Rdc
OMD_Porte 2V tunnel:140x204:3238674:1 | 0- Rdc
OMD_Porte 2V tunnel:140x204:3238504:1 | 0- Rdc
OMD_Porte 1V tunnel:80x204:3238961:1 | 0- Rdc
OMD_Porte 1V tunnel:80x204:3239001:1 | 0- Rdc
OMD_Porte 1V tunnel:80x204:3239080:1 | 0- Rdc
OMD_Porte 1V tunnel:80x204:3239041:1 | 0- Rdc
OMD_Porte 1V tunnel:80x204:3239213:1 | 0- Rdc
OMD_Porte 1V tunnel:80x204:3239109:1 | 0- Rdc
OMD_Porte 1V tunnel:80x204:3239439:1 | 0- Rdc
OMD_Porte 2V tunnel:140x204:3239482:1 | 0- Rdc
OMD_Porte 2V tunnel:140x204:3251587:1 | Rez de Rue Simon
OMD_Porte 2V tunnel:140x204:3254864:1 | Rez de Rue Simon
OMD_Porte 2V tunnel:140x204:3255027:1 | Rez de Rue Simon
OMD_Porte 1V tunnel:80x204:3255115:1 | Rez de Rue Simon
OMD_Porte 1V tunnel:80x204:3256236:1 | Rez de Rue Simon
OMD_Porte 1V tunnel:80x204:3256272:1 | Rez de Rue Simon
OMD_Porte 1V tunnel:60X204:3256344:1 | Rez de Rue Simon
OMD_Porte 1V tunnel:60X204:3256375:1 | Rez de Rue Simon
OMD_Porte 2V tunnel:140x204:3256571:1 | Rez de Rue Simon
OMD_Porte 1V tunnel:80x204:3256708:1 | Rez de Rue Simon
OMD_Porte 2V tunnel:140x204:3256848:1 | Rez de Rue Simon
OMD_Porte 1V tunnel:80x204:3257045:1 | Rez de Rue Simon
OMD_Porte 2V tunnel:140x204:3292890:1 | Rez de Rue Simon
OMD_Porte 1V tunnel:80x204:3257151:1 | Rez de Rue Simon
OMD_Porte 1V tunnel:80x204:3257261:1 | Rez de Rue Simon
OMD_Porte 1V tunnel:80x204:3257412:1 | Rez de Rue Simon
OMD_Porte 1V tunnel:80x204:3257467:1 | Rez de Rue Simon
OMD_Porte 1V tunnel:80x204:3257583:1 | Rez de Rue Simon
Grz_Placard 1V:80X204:3257746:1 | Rez de Rue Simon
Grz_Placard 1V:80X204:3257783:1 | Rez de Rue Simon
OMD_Porte 2V tunnel:140x204:3260093:1 | Rez de Rue Simon
OMD_Porte 1V tunnel:80x204:3259892:1 | Rez de Rue Simon
OMD_Porte 2V tunnel:140x204:3259964:1 | Rez de Rue Simon
Grz_Placard 1V:53x204:3265552:1 | Rez de Rue Simon
Grz_Placard 2V:140x204:3265580:1 | Rez de Rue Simon
Mur de base:MUR 10:3265524 | Rez de Rue Simon
OMD_Porte 1V tunnel:80x204:3267236:1 | Rez de Rue Simon
Mur de base:MUR 13:3267283 | Rez de Rue Simon
OMD_Porte 2V tunnel:140x204:3268039:1 | Rez de Rue Simon
OMD_Porte 1V tunnel:80x204:3268249:1 | Rez de Rue Simon
OMD_Porte 1V tunnel:80x204:3268777:1 | Rez de Rue Simon
OMD_Porte 2V tunnel:double 180x204:3268940:1 | Rez de Rue Simon
Tierce (R):1.43m x 2.04m:3469239:1 | Rez de Rue Simon
OMD_Porte 1V tunnel:80x204:3268376:1 | Rez de Rue Simon
OMD_Porte 1V tunnel:80x204:3268453:1 | Rez de Rue Simon
OMD_Porte 1V tunnel:80x204:3268461:1 | Rez de Rue Simon
OMD_Porte 1V tunnel:80x204:3268469:1 | Rez de Rue Simon
OMD_Porte 1V tunnel:80x204:3268528:1 | Rez de Rue Simon
OMD_Porte 1V tunnel:80x204:3268536:1 | Rez de Rue Simon
OMD_Porte 1V tunnel:80x204:3268544:1 | Rez de Rue Simon
OMD_Porte 2V tunnel:140x204:3268616:1 | Rez de Rue Simon
OMD_Porte 1V tunnel:80x204:3269706:1 | Rez de Rue Simon
OMD_Porte 1V tunnel:80x204:3269565:1 | Rez de Rue Simon
OMD_Porte 1V tunnel:80x204:3269628:1 | Rez de Rue Simon
OMD_Porte 2V tunnel:140x204:3274242:1 | R-1
OMD_Porte 1V tunnel:80x204:3273387:1 | R-1
OMD_Porte 2V tunnel:double 160x204:3274028:1 | R-1
OMD_Porte 1V tunnel:80x204:3277082:1 | R-1
OMD_Porte 2V tunnel:140x204:3277154:1 | R-1
OMD_Porte 1V tunnel:80x204:3277709:1 | R-1
OMD_Porte 1V tunnel:80x204:3277820:1 | R-1
OMD_Porte 1V tunnel:80x204:3277902:1 | R-1
OMD_Porte 1V tunnel:80x204:3277743:1 | R-1
OMD_Porte 1V tunnel:80x204:3277777:1 | R-1
OMD_Porte 1V tunnel:80x204:3277851:1 | R-1
OMD_Porte 2V tunnel:double 180x204:3293616:1 | 0- Rdc
OMD_Porte 1V tunnel:80x204:3293674:1 | 0- Rdc
OMD_Porte 2V tunnel:140x204:3295109:1 | 1-R+1
OMD_Porte 2V tunnel:double 140x204:3296977:1 | 1-R+1
OMD_Porte 2V tunnel:136x204:3296981:1 | 1-R+1
OMD_Porte 2V tunnel:140x204:3296987:1 | 1-R+1
OMD_Porte 1V tunnel:90x204:3319910:1 | Rez de Rue Simon
Grz_porte 1V recouvrement 30°:80x204:3326648:1 | Rez de Rue Simon
OMD_Porte 2V tunnel:140x204 +occulus:3329272:1 | rez de rue -1.10m
Grz_porte 1V recouvrement 30°:93x204:3336251:1 | rez de rue -1.10m
Grz_porte 1V recouvrement 30°:93x204:3336307:1 | rez de rue -1.10m
Grz_porte 1V recouvrement 30°:80x204:3375339:1 | Rez de Rue Simon
Grz_porte 1V recouvrement 30°:80x204:3375352:1 | Rez de Rue Simon
Grz_porte 1V recouvrement 30°:93x204:3375354:1 | Rez de Rue Simon
Grz_porte 1V recouvrement 30°:80x204:3375360:1 | Rez de Rue Simon
Grz_porte 1V recouvrement 30°:80x204:3375361:1 | Rez de Rue Simon
Grz_porte 1V recouvrement 30°:93x204:3375894:1 | rez de rue -1.10m
OMD_Porte 2V tunnel:140x204 +occulus:3377111:1 | rez de rue -1.10m
OMD_Porte 2V tunnel:140x204 +occulus:3455930:1 | rez de rue -1.10m
Grz_porte 1V recouvrement 30°:93x204:3428447:1 | rez de rue -1.10m
Double (T):1.83m x 2.04m:3694307:1 | rez de rue -1.10m
Double (T):1.83m x 2.04m:3694244:1 | rez de rue -1.10m
Double (T):1.63m x 2.04m:3547414:1 | rez de rue -1.10m
Grz_porte 1V recouvrement 30°:93x204:4233025:1 | rez de rue -1.10m
Grz_porte 1V recouvrement 30°:80x204:4099117:1 | rez de rue -1.10m
Grz_porte 1V recouvrement 30°:93x204:4156472:1 | rez de rue -1.10m
Grz_porte 1V recouvrement 30°:80x204:4236965:1 | rez de rue -1.10m
Grz_Placard 1V:80X204:5340598:1 | 0- Rdc
Grz_Placard 1V:80X204:5373717:1 | 0- Rdc
Grz_Placard 1V:80X204:5373759:1 | 0- Rdc
Double (T):1.63m x 2.04m:4138939:1 | rez de rue -1.10m
OMD_Porte 2V tunnel:140x204 +occulus:4138959:1 | rez de rue -1.10m
Tierce (R):1.20m x 2.04m:4204126:1 | R-1
Tierce (R):1.20m x 2.04m:4204151:1 | R-1
Grz_Garage sectionnelle:porte sectionnelle 3.6X3:4898337:1 | Rez de Rue Simon
Tierce (R):1.43m x 2.04m:5334413:1 | Rez de Rue Simon
OMD_Porte 1V tunnel:70X204:5335770:1 | Rez de Rue Simon
Grz_Placard 2V:140x204:5366304:1 | Rez de Rue Simon

# IfcPlate: Panneau système:MAILLE (2)
In: Rez de Rue Simon
Type - PredefinedType: CURTAIN_PANEL; Material: Verre 0.01 m
Material: OMD-Maille
Pset_PlateCommon - IsExternal: yes; Reference: MAILLE
Pset_QuantityTakeOff - Reference: MAILLE
Name (Panneau système:MAILLE:...)
4323527
4323621

# IfcPlate: Panneau système:Vitré (544)
Type - PredefinedType: CURTAIN_PANEL; Material: Verre 0.01 m
Type - Pset_PlateCommon - ThermalTransmittance: 6.7069 kg/K/s3
Material: Verre
Pset_PlateCommon - IsExternal: yes; Reference: Vitré
Pset_QuantityTakeOff - Reference: Vitré
Name (Panneau système:Vitré:...) | In
3241976 | 0- Rdc
3242030 | 0- Rdc
3242176 | 0- Rdc
3242182 | 0- Rdc
3242196 | 0- Rdc
3242202 | 0- Rdc
4777281 | 0- Rdc
3242214 | 0- Rdc
3242220 | 0- Rdc
3242232 | 0- Rdc
3242238 | 0- Rdc
3242252 | 0- Rdc
3242258 | 0- Rdc
3242274 | 0- Rdc
3242280 | 0- Rdc
3242292 | 0- Rdc
3242298 | 0- Rdc
3242363 | 0- Rdc
3242369 | 0- Rdc
3242408 | 0- Rdc
3242414 | 0- Rdc
3242426 | 0- Rdc
3242432 | 0- Rdc
3242444 | 0- Rdc
3242450 | 0- Rdc
3242464 | 0- Rdc
3242470 | 0- Rdc
3242482 | 0- Rdc
3242488 | 0- Rdc
3242502 | 0- Rdc
3242508 | 0- Rdc
3242520 | 0- Rdc
3242526 | 0- Rdc
3242625 | 0- Rdc
3242631 | 0- Rdc
3242690 | 0- Rdc
3242696 | 0- Rdc
3242710 | 0- Rdc
3242716 | 0- Rdc
3242734 | 0- Rdc
3242740 | 0- Rdc
3242754 | 0- Rdc
3242760 | 0- Rdc
3242788 | 0- Rdc
3242794 | 0- Rdc
3242808 | 0- Rdc
3242814 | 0- Rdc
3242830 | 0- Rdc
3242836 | 0- Rdc
3242852 | 0- Rdc
3242858 | 0- Rdc
3242874 | 0- Rdc
3242880 | 0- Rdc
3243068 | 0- Rdc
3243074 | 0- Rdc
4749448 | 0- Rdc
3243120 | 0- Rdc
3243126 | 0- Rdc
3243142 | 0- Rdc
3243148 | 0- Rdc
3243162 | 0- Rdc
3243168 | 0- Rdc
3243180 | 0- Rdc
3243186 | 0- Rdc
3243198 | 0- Rdc
3243204 | 0- Rdc
3243218 | 0- Rdc
3243224 | 0- Rdc
4777327 | 0- Rdc
3243300 | 0- Rdc
3243306 | 0- Rdc
3243335 | 0- Rdc
3243341 | 0- Rdc
3243487 | 0- Rdc
3243493 | 0- Rdc
3243621 | 0- Rdc
3243627 | 0- Rdc
3243662 | 0- Rdc
3243668 | 0- Rdc
3243680 | 0- Rdc
3243686 | 0- Rdc
4777184 | 0- Rdc
3243698 | 0- Rdc
3243704 | 0- Rdc
3243716 | 0- Rdc
3243722 | 0- Rdc
3243736 | 0- Rdc
3243742 | 0- Rdc
3243772 | 0- Rdc
3243778 | 0- Rdc
3243950 | 0- Rdc
3248997 | 0- Rdc
3249190 | 0- Rdc
3249191 | 0- Rdc
3243956 | 0- Rdc
3249101 | 0- Rdc
3249112 | 0- Rdc
3249268 | 0- Rdc
3249269 | 0- Rdc
3249107 | 0- Rdc
3249369 | 0- Rdc
3249380 | 0- Rdc
3249387 | 0- Rdc
3249388 | 0- Rdc
3249375 | 0- Rdc
3249402 | 0- Rdc
3249413 | 0- Rdc
3249420 | 0- Rdc
3249421 | 0- Rdc
3249408 | 0- Rdc
3249439 | 0- Rdc
3249450 | 0- Rdc
3249457 | 0- Rdc
3249458 | 0- Rdc
3249445 | 0- Rdc
3249470 | 0- Rdc
3249481 | 0- Rdc
3249488 | 0- Rdc
3249489 | 0- Rdc
3249476 | 0- Rdc
3249507 | 0- Rdc
3249518 | 0- Rdc
3249525 | 0- Rdc
3249526 | 0- Rdc
3249513 | 0- Rdc
3249597 | 0- Rdc
3250028 | 0- Rdc
3249608 | 0- Rdc
3249615 | 0- Rdc
3249616 | 0- Rdc
3258382 | Rez de Rue Simon
3258388 | Rez de Rue Simon
3258393 | Rez de Rue Simon
3258399 | Rez de Rue Simon
3258404 | Rez de Rue Simon
3263100 | Rez de Rue Simon
3258410 | Rez de Rue Simon
3258415 | Rez de Rue Simon
3258421 | Rez de Rue Simon
3258426 | Rez de Rue Simon
3258432 | Rez de Rue Simon
3258437 | Rez de Rue Simon
3258443 | Rez de Rue Simon
3258448 | Rez de Rue Simon
3258454 | Rez de Rue Simon
3258459 | Rez de Rue Simon
3258465 | Rez de Rue Simon
3258470 | Rez de Rue Simon
3258476 | Rez de Rue Simon
3258481 | Rez de Rue Simon
3258487 | Rez de Rue Simon
3258492 | Rez de Rue Simon
3258498 | Rez de Rue Simon
3258503 | Rez de Rue Simon
3258509 | Rez de Rue Simon
3258514 | Rez de Rue Simon
3258520 | Rez de Rue Simon
3258525 | Rez de Rue Simon
3258531 | Rez de Rue Simon
3258536 | Rez de Rue Simon
3258542 | Rez de Rue Simon
3258547 | Rez de Rue Simon
3258553 | Rez de Rue Simon
3258558 | Rez de Rue Simon
3258564 | Rez de Rue Simon
3258569 | Rez de Rue Simon
3258575 | Rez de Rue Simon
3258580 | Rez de Rue Simon
3258586 | Rez de Rue Simon
3259397 | Rez de Rue Simon
3259403 | Rez de Rue Simon
3259408 | Rez de Rue Simon
3259414 | Rez de Rue Simon
3259419 | Rez de Rue Simon
3259425 | Rez de Rue Simon
3259430 | Rez de Rue Simon
3259436 | Rez de Rue Simon
3259441 | Rez de Rue Simon
3259447 | Rez de Rue Simon
3259452 | Rez de Rue Simon
3259458 | Rez de Rue Simon
3259463 | Rez de Rue Simon
3259469 | Rez de Rue Simon
3259474 | Rez de Rue Simon
3259480 | Rez de Rue Simon
3260689 | 0- Rdc
3260713 | 0- Rdc
3260699 | 0- Rdc
3260705 | 0- Rdc
3260706 | 0- Rdc
3260742 | 0- Rdc
3260766 | 0- Rdc
3260752 | 0- Rdc
3260758 | 0- Rdc
3260759 | 0- Rdc
3261218 | Rez de Rue Simon
3261228 | Rez de Rue Simon
3261234 | Rez de Rue Simon
3261235 | Rez de Rue Simon
4022847 | Rez de Rue Simon
4022901 | Rez de Rue Simon
4022902 | Rez de Rue Simon
3261262 | Rez de Rue Simon
3261272 | Rez de Rue Simon
3261278 | Rez de Rue Simon
3261279 | Rez de Rue Simon
4023030 | Rez de Rue Simon
4022973 | Rez de Rue Simon
4022975 | Rez de Rue Simon
3261306 | Rez de Rue Simon
3262079 | Rez de Rue Simon
3261330 | Rez de Rue Simon
3261900 | Rez de Rue Simon
3261322 | Rez de Rue Simon
3261901 | Rez de Rue Simon
3262081 | Rez de Rue Simon
3261695 | Rez de Rue Simon
3261902 | Rez de Rue Simon
3263582 | Rez de Rue Simon
3263606 | Rez de Rue Simon
3263617 | Rez de Rue Simon
3263592 | Rez de Rue Simon
3263598 | Rez de Rue Simon
3263599 | Rez de Rue Simon
3263608 | Rez de Rue Simon
3264176 | 0- Rdc
3264195 | 0- Rdc
3264182 | 0- Rdc
3264187 | 0- Rdc
3264188 | 0- Rdc
3293093 | 0- Rdc
3293099 | 0- Rdc
3294428 | 1-R+1
3294434 | 1-R+1
3294439 | 1-R+1
3294445 | 1-R+1
3294450 | 1-R+1
3294456 | 1-R+1
3294461 | 1-R+1
3294467 | 1-R+1
3294472 | 1-R+1
3294478 | 1-R+1
3294483 | 1-R+1
3294489 | 1-R+1
3294494 | 1-R+1
3294500 | 1-R+1
3294505 | 1-R+1
3294511 | 1-R+1
3294516 | 1-R+1
3294522 | 1-R+1
3294527 | 1-R+1
3294533 | 1-R+1
3294538 | 1-R+1
3294544 | 1-R+1
3294549 | 1-R+1
3294555 | 1-R+1
3294560 | 1-R+1
3294566 | 1-R+1
3294571 | 1-R+1
3294577 | 1-R+1
3294582 | 1-R+1
3294588 | 1-R+1
3294593 | 1-R+1
3294599 | 1-R+1
3294604 | 1-R+1
3294610 | 1-R+1
3294615 | 1-R+1
3294621 | 1-R+1
3294626 | 1-R+1
3294632 | 1-R+1
3294637 | 1-R+1
3294643 | 1-R+1
3294648 | 1-R+1
3294654 | 1-R+1
3294659 | 1-R+1
3294665 | 1-R+1
3294670 | 1-R+1
3294676 | 1-R+1
3294681 | 1-R+1
3294687 | 1-R+1
3294692 | 1-R+1
3294698 | 1-R+1
3294703 | 1-R+1
3294709 | 1-R+1
3294714 | 1-R+1
3294720 | 1-R+1
3294725 | 1-R+1
3294731 | 1-R+1
3294736 | 1-R+1
3294742 | 1-R+1
4749515 | 1-R+1
3294747 | 1-R+1
3294753 | 1-R+1
3294758 | 1-R+1
3294764 | 1-R+1
3294769 | 1-R+1
3294775 | 1-R+1
3294780 | 1-R+1
3294786 | 1-R+1
3294791 | 1-R+1
3294797 | 1-R+1
3294802 | 1-R+1
3294808 | 1-R+1
4749608 | 1-R+1
3294813 | 1-R+1
3294819 | 1-R+1
3294824 | 1-R+1
3294830 | 1-R+1
3294835 | 1-R+1
3294841 | 1-R+1
3294846 | 1-R+1
3294852 | 1-R+1
3294857 | 1-R+1
3294863 | 1-R+1
3294868 | 1-R+1
3294874 | 1-R+1
3294879 | 1-R+1
3294885 | 1-R+1
3294901 | 1-R+1
3294907 | 1-R+1
3295099 | 1-R+1
3295105 | 1-R+1
3295344 | 1-R+1
3295350 | 1-R+1
3295368 | 1-R+1
3295374 | 1-R+1
3295394 | 1-R+1
3295400 | 1-R+1
3295414 | 1-R+1
3295420 | 1-R+1
3295440 | 1-R+1
3295446 | 1-R+1
3295462 | 1-R+1
3295468 | 1-R+1
3295486 | 1-R+1
3295492 | 1-R+1
3296153 | 1-R+1
3296159 | 1-R+1
3296196 | 1-R+1
3296202 | 1-R+1
3296216 | 1-R+1
3296222 | 1-R+1
3296236 | 1-R+1
3296242 | 1-R+1
3296256 | 1-R+1
3296262 | 1-R+1
3296292 | 1-R+1
3296298 | 1-R+1
3296312 | 1-R+1
3296318 | 1-R+1
3296561 | 1-R+1
3296567 | 1-R+1
3296581 | 1-R+1
3296587 | 1-R+1
3297501 | 2-R+2
3297601 | 2-R+2
3297916 | 2-R+2
3298370 | 2-R+2
3298385 | 2-R+2
3298398 | 2-R+2
3298413 | 2-R+2
4749845 | 2-R+2
3298428 | 2-R+2
3298443 | 2-R+2
3298456 | 2-R+2
3298473 | 2-R+2
3298486 | 2-R+2
3298499 | 2-R+2
3298512 | 2-R+2
3298525 | 2-R+2
3298538 | 2-R+2
3298551 | 2-R+2
3298564 | 2-R+2
3298577 | 2-R+2
3298594 | 2-R+2
3298607 | 2-R+2
3298622 | 2-R+2
3298635 | 2-R+2
3298648 | 2-R+2
3299354 | 2-R+2
3299371 | 2-R+2
3299463 | 2-R+2
3299823 | 2-R+2
3299838 | 2-R+2
3299851 | 2-R+2
3299864 | 2-R+2
3299877 | 2-R+2
3299892 | 2-R+2
3299907 | 2-R+2
3299922 | 2-R+2
3299935 | 2-R+2
3299950 | 2-R+2
3299963 | 2-R+2
3299976 | 2-R+2
3299989 | 2-R+2
3300031 | 2-R+2
3300044 | 2-R+2
3300303 | 2-R+2
3300682 | 2-R+2
3300697 | 2-R+2
3300710 | 2-R+2
3300727 | 2-R+2
3300742 | 2-R+2
3300755 | 2-R+2
3300841 | 2-R+2
3300856 | 2-R+2
3300869 | 2-R+2
3300882 | 2-R+2
3300895 | 2-R+2
3300910 | 2-R+2
3300925 | 2-R+2
3300938 | 2-R+2
3300953 | 2-R+2
3301092 | 2-R+2
3301306 | 2-R+2
3301321 | 2-R+2
3301340 | 2-R+2
3301357 | 2-R+2
3301376 | 2-R+2
3301389 | 2-R+2
3301404 | 2-R+2
3301419 | 2-R+2
3301434 | 2-R+2
3301449 | 2-R+2
3301462 | 2-R+2
3301479 | 2-R+2
3301496 | 2-R+2
3301659 | 2-R+2
3301738 | 2-R+2
3301751 | 2-R+2
3301764 | 2-R+2
3301777 | 2-R+2
3301790 | 2-R+2
3301803 | 2-R+2
3301816 | 2-R+2
3301831 | 2-R+2
3301846 | 2-R+2
3301859 | 2-R+2
3301872 | 2-R+2
3302229 | 2-R+2
3302242 | 2-R+2
3302255 | 2-R+2
3302268 | 2-R+2
3302536 | 2-R+2
3302805 | 2-R+2
3302820 | 2-R+2
3302833 | 2-R+2
3302854 | 2-R+2
3302869 | 2-R+2
3302882 | 2-R+2
3302899 | 2-R+2
3302912 | 2-R+2
3302929 | 2-R+2
3302942 | 2-R+2
3303134 | 2-R+2
3303149 | 2-R+2
3303164 | 2-R+2
3303179 | 2-R+2
3303200 | 2-R+2
3303213 | 2-R+2
3303226 | 2-R+2
3303241 | 2-R+2
3303254 | 2-R+2
3303491 | 2-R+2
3303506 | 2-R+2
3303519 | 2-R+2
3303540 | 2-R+2
3303559 | 2-R+2
3303572 | 2-R+2
3303585 | 2-R+2
3303600 | 2-R+2
3303617 | 2-R+2
3303630 | 2-R+2
3303860 | 2-R+2
3303879 | 2-R+2
3665529 | rez de rue -1.10m
3666145 | rez de rue -1.10m
3666100 | rez de rue -1.10m
3666204 | rez de rue -1.10m
3666304 | rez de rue -1.10m
3666389 | rez de rue -1.10m
3666025 | rez de rue -1.10m
3665970 | rez de rue -1.10m
4907645 | rez de rue -1.10m
4907646 | rez de rue -1.10m
4907647 | rez de rue -1.10m
4907648 | rez de rue -1.10m
4907650 | rez de rue -1.10m
4907651 | rez de rue -1.10m
4907652 | rez de rue -1.10m
4907653 | rez de rue -1.10m
3667791 | rez de rue -1.10m
4141727 | rez de rue -1.10m
4723194 | rez de rue -1.10m
4697966 | rez de rue -1.10m
4723196 | rez de rue -1.10m
5445406 | 0- Rdc
5445413 | 0- Rdc
5445415 | 0- Rdc
5445417 | 0- Rdc
5445419 | 0- Rdc
5445319 | 0- Rdc
5445326 | 0- Rdc
5445328 | 0- Rdc
5445330 | 0- Rdc
5445332 | 0- Rdc
4279755 | rez de rue -1.10m
4282095 | rez de rue -1.10m
4698115 | rez de rue -1.10m
4698116 | rez de rue -1.10m
4318348 | Rez de Rue Simon
4318232 | Rez de Rue Simon
4730068 | Rez de Rue Simon
4318067 | Rez de Rue Simon
4723585 | rez de rue -1.10m
4723581 | rez de rue -1.10m
4723604 | rez de rue -1.10m
4723597 | rez de rue -1.10m
4724000 | rez de rue -1.10m
4724004 | rez de rue -1.10m
4724031 | rez de rue -1.10m
4724017 | rez de rue -1.10m
5289596 | 0- Rdc
5369631 | 0- Rdc
5289600 | 0- Rdc
5369773 | 0- Rdc
5369844 | 0- Rdc
5370073 | 0- Rdc
5370142 | 0- Rdc
5289606 | 0- Rdc
5370342 | 0- Rdc
5289644 | 0- Rdc
5289664 | 0- Rdc
5289651 | 0- Rdc
5289653 | 0- Rdc
5289675 | 0- Rdc
5289685 | 0- Rdc
5289690 | 0- Rdc
5289700 | 0- Rdc
5333308 | 0- Rdc
5327254 | 0- Rdc
5327901 | 0- Rdc
5378886 | 0- Rdc
5378898 | 0- Rdc

# IfcPlate: Panneau système:Vitré +vitro (16)
In: rez de rue -1.10m
Type - PredefinedType: CURTAIN_PANEL; Material: Verre 0.01 m
Material: Verre, vitrage transparent
Pset_PlateCommon - IsExternal: yes; Reference: Vitré +vitro
Pset_QuantityTakeOff - Reference: Vitré +vitro
Name (Panneau système:Vitré +vitro:...)
4907568
4907569
4907570
4907571
4907573
4907574
4907575
4907576
4698015
4723195
4698273
4698274
4723614
4723610
4724023
4724037

# IfcPlate: Panneau système:Vitré opal (8)
Type - PredefinedType: CURTAIN_PANEL; Material: Verre 0.01 m
Material: OMD-Verre opal
Pset_PlateCommon - IsExternal: yes; Reference: Vitré opal
Pset_QuantityTakeOff - Reference: Vitré opal
Name (Panneau système:Vitré opal:...) | In
3243754 | 0- Rdc
3243760 | 0- Rdc
4667426 | 0- Rdc
4667432 | 0- Rdc
4667593 | 1-R+1
4667599 | 1-R+1
4667604 | 1-R+1
4667610 | 1-R+1

# IfcPlate: Panneau système:plein (6)
Type - PredefinedType: CURTAIN_PANEL; Material: Verre 0.01 m
Material: Trap- Dallmer- Polypropylene
Pset_PlateCommon - Reference: plein
Pset_QuantityTakeOff - Reference: plein
Name (Panneau système:plein:...) | In | IsExternal
3258591 | Rez de Rue Simon | yes
3981667 | Rez de Rue Simon | yes
3269865 | Rez de Rue Simon | yes
3981730 | Rez de Rue Simon | yes
5333558 | R-1 | no
5334330 | R-1 | no

# IfcPlate: Panneau système:plein bois (4)
In: rez de rue -1.10m
Type - PredefinedType: CURTAIN_PANEL; Material: Verre 0.01 m
Material: OMD_Porte Stratifié
Pset_PlateCommon - IsExternal: yes; Reference: plein bois
Pset_QuantityTakeOff - Reference: plein bois
Name (Panneau système:plein bois:...)
4142590
4723419
4723589
4724009

# IfcRailing: Garde-corps:BUGAL_502010101, Garde-corps:BUGAL_502010101:5262598
In: 0- Rdc
Material: Aluminium, Verre
Pset_QuantityTakeOff - Reference: BUGAL_502010101
Pset_RailingCommon - IsExternal: no; Reference: BUGAL_502010101; Height: 1.2192 m

# IfcRailing: Garde-corps:OMD_Garde Corps Régulier 1m (5)
Material: <Unnamed>, Peinture - Grise, OMD_RAL1032
Pset_QuantityTakeOff - Reference: OMD_Garde Corps Régulier 1m
Pset_RailingCommon - IsExternal: no; Reference: OMD_Garde Corps Régulier 1m; Height: 1.05 m
Name (Garde-corps:OMD_Garde Corps Régulier 1m:...) | In
3631689 | 0- Rdc
3631693 | 0- Rdc
3631807 | 0- Rdc
3631846 | 0- Rdc
5437312 | rez de rue -1.10m

# IfcRailing: Garde-corps:OMD_Main Courante (35)
Pset_QuantityTakeOff - Reference: OMD_Main Courante
Pset_RailingCommon - IsExternal: no; Reference: OMD_Main Courante; Height: 0.9 m
Name (Garde-corps:OMD_Main Courante:...) | In | Material
3229065 | 0- Rdc | <Unnamed>, Aluminium
3229069 | 0- Rdc | <Unnamed>, Aluminium
3231333 | 0- Rdc | <Unnamed>, Aluminium
3231337 | 0- Rdc | <Unnamed>, Aluminium
3234783 | 0- Rdc | <Unnamed>, Aluminium
3234787 | 0- Rdc | <Unnamed>, Aluminium
3240013 | 0- Rdc | <Unnamed>, Aluminium
3240017 | 0- Rdc | <Unnamed>, Aluminium
3257979 | Rez de Rue Simon | <Unnamed>, Aluminium
3257983 | Rez de Rue Simon | <Unnamed>, Aluminium
3258057 | Rez de Rue Simon | <Unnamed>, Aluminium
3258061 | Rez de Rue Simon | <Unnamed>, Aluminium
3258137 | Rez de Rue Simon | <Unnamed>, Aluminium
3258141 | Rez de Rue Simon | <Unnamed>, Aluminium
3285202 | R-1 | <Unnamed>, Aluminium
3285206 | R-1 | <Unnamed>, Aluminium
3285239 | R-1 | <Unnamed>, Aluminium
3285243 | R-1 | <Unnamed>, Aluminium
3291581 | R-1 | <Unnamed>, Aluminium
3291585 | R-1 | <Unnamed>, Aluminium
3294094 | 1-R+1 | <Unnamed>, Aluminium
3294098 | 1-R+1 | <Unnamed>, Aluminium
3294163 | 1-R+1 | <Unnamed>, Aluminium
3294167 | 1-R+1 | <Unnamed>, Aluminium
3294228 | 1-R+1 | <Unnamed>, Aluminium
3294232 | 1-R+1 | <Unnamed>, Aluminium
3294297 | 1-R+1 | <Unnamed>, Aluminium
3294301 | 1-R+1 | <Unnamed>, Aluminium
3320619 | rez de rue -1.10m | OMD_RAL1032, Aluminium
3320623 | rez de rue -1.10m | <Unnamed>, Aluminium
3328728 | R-1 | <Unnamed>, Aluminium
3329474 | R-1 | <Unnamed>, Aluminium
4134812 | R-1 | <Unnamed>, Aluminium
4134865 | R-1 | <Unnamed>, Aluminium
5437315 | rez de rue -1.10m | <Unnamed>, Aluminium

# IfcRoof: Toit de base:Couverture tuile, Toit de base:Couverture tuile:3304539
In: 2-R+2
Material: Tuiles, toiture 0.02 m, OMD_Bois 0.04 m, OMD_Bois 0.06 m
Pset_QuantityTakeOff - Reference: Couverture tuile
Pset_RoofCommon - IsExternal: yes; Reference: Couverture tuile; ProjectedArea: 2143.69 m2; TotalArea: 2474.09 m2

# IfcRoof: Toit de base:Toit dallettes 80*40, Toit de base:Toit dallettes 80*40:4655178
In: 0- Rdc
Material: OMD-Lame terasse composite 0.04 m, OMD-Vide 0.25 m, Maçonnerie - Isolant 0.1 m
Pset_QuantityTakeOff - Reference: Toit dallettes 80*40
Pset_RoofCommon - IsExternal: yes; Reference: Toit dallettes 80*40; ProjectedArea: 75.2661 m2; TotalArea: 75.2691 m2

# IfcRoof: Toit de base:Toit végétalisée (3)
In: 0- Rdc
Material: OMD _toiture végétalisée 0.05 m, OMD_couche drainante 0.05 m, Maçonnerie - Isolant 0.16 m
Pset_QuantityTakeOff - Reference: Toit végétalisée
Pset_RoofCommon - IsExternal: yes; Reference: Toit végétalisée
Name (Toit de base:Toit végétalisée:...) | ProjectedArea (m2) | TotalArea (m2)
4081846 | 120.7 | 120.704
4081980 | 31.7307 | 31.7319
4655724 | 119.799 | 119.804

# IfcRoof: Toit de base:toit isol 10+étanchéité, Toit de base:toit isol 10+étanchéité:3811939
In: 0- Rdc
Material: OMD_Bande Sterile 0.05 m, Maçonnerie - Isolant 0.15 m
Pset_QuantityTakeOff - Reference: toit isol 10+étanchéité
Pset_RoofCommon - IsExternal: yes; Reference: toit isol 10+étanchéité; ProjectedArea: 352.751 m2; TotalArea: 70.3567 m2

# IfcRoof: Toit de base:toit terrasse 35 (9)
Material: OMD tranche 0.35 m
Pset_QuantityTakeOff - Reference: toit terrasse 35
Pset_RoofCommon - IsExternal: yes; Reference: toit terrasse 35
Name (Toit de base:toit terrasse 35:...) | In | ProjectedArea (m2) | TotalArea (m2)
3495543 | 0- Rdc | 1.20991 | 1.20996
3495677 | 0- Rdc | 1.20991 | 1.20996
3495768 | 0- Rdc | 1.20991 | 1.20996
3495828 | 0- Rdc | 1.20992 | 1.20996
3495856 | 0- Rdc | 1.20991 | 1.20996
3495888 | 0- Rdc | 1.20991 | 1.20996
3496000 | 0- Rdc | 1.20991 | 1.20996
4239414 | 0- Rdc | 482.258 | 426.189
4711984 | 2-R+2 | 313.241 | 313.241

# IfcRoof: Vitres inclinées:Toit en verre 1 m x 2 m (3)
In: 0- Rdc
Pset_QuantityTakeOff - Reference: Toit en verre 1 m x 2 m
Pset_RoofCommon - IsExternal: yes; Reference: Toit en verre 1 m x 2 m
Name (Vitres inclinées:Toit en verre 1 m x 2 m:...) | ProjectedArea (m2)
4240144 | 5.06602
4241132 | 5.15846
5289593 | 63.7932

# IfcSlab: Palier monobloc:150 mm d'épaisseur (14)
Type - PredefinedType: LANDING
Material: <Unnamed>
Pset_QuantityTakeOff - Reference: 150 mm d'épaisseur; sets with these values: 2
Pset_SlabCommon - IsExternal: no; PitchAngle: 0 deg; Reference: 150 mm d'épaisseur
Name (Escalier coulé sur place:Escalier:...) | In
3228538 Landing 1 | 0- Rdc
3231157 Landing 1 | 0- Rdc
3234227 Landing 1 | 0- Rdc
3239510 Landing 1 | 0- Rdc
3251507 Landing 1 | Rez de Rue Simon
3257963 Landing 1 | Rez de Rue Simon
3258041 Landing 1 | Rez de Rue Simon
3258121 Landing 1 | Rez de Rue Simon
3291574 Landing 1 | R-1
3294087 Landing 1 | 1-R+1
3294156 Landing 1 | 1-R+1
3294221 Landing 1 | 1-R+1
3294290 Landing 1 | 1-R+1
4134805 Landing 1 | R-1

# IfcSlab: Sol:Dalle 162, Sol:Dalle 162:4921252
In: Rez de Rue Simon
Type - PredefinedType: FLOOR; Material: <Unnamed> 0.025 m, OMD_Chape 0.03 m, OMD_Sable 0.03 m, OMD_Béton blanc 0.162 m
Type - Pset_ReinforcementBarPitchOfSlab - Description: Dalle béton 20cm
Pset_QuantityTakeOff - Reference: Dalle 162; sets with these values: 2
Pset_SlabCommon - LoadBearing: no; IsExternal: no; PitchAngle: 0 deg; Reference: Dalle 162

# IfcSlab: Sol:Dalle 20 (14)
Type - PredefinedType: FLOOR; Material: OMD_Béton blanc 0.2 m
Type - Pset_ReinforcementBarPitchOfSlab - Description: Dalle béton 20cm
Pset_QuantityTakeOff - Reference: Dalle 20; sets with these values: 2
Pset_SlabCommon - LoadBearing: no; Reference: Dalle 20; IsExternal: no
Name (Sol:Dalle 20:...) | In | PitchAngle (deg)
3228047 | 0- Rdc | 0
3251882 | 1-R+1 | 0
3285183 | R-1 | 0
3285183:2 | R-1 | 0
3304230 | 2-R+2 | 0
3304274 | 3-Combles | 0
3313586 | 0- Rdc | 0.51
3631741 | 0- Rdc | 0
3631785 | 0- Rdc | 0
3632521 | 0- Rdc | 0
3632865 | 0- Rdc | 31.1993 | Material: OMD_Béton blanc
4082149 | R-1 | 0
5442062 | Rez de Rue Simon | 0
5442062:2 | Rez de Rue Simon | 0

# IfcSlab: Sol:Dalle 25, Sol:Dalle 25:5291298
In: R-1
Type - PredefinedType: FLOOR; Material: Béton, coulé sur place 0.25 m
Type - Pset_ReinforcementBarPitchOfSlab - Description: Dalle béton 20cm
Type - Pset_SlabCommon - ThermalTransmittance: 4.184 kg/K/s3
Pset_QuantityTakeOff - Reference: Dalle 25; sets with these values: 2
Pset_SlabCommon - LoadBearing: no; IsExternal: no; PitchAngle: 0 deg; Reference: Dalle 25

# IfcSlab: Sol:Dalle béton 13 cm, Sol:Dalle béton 13 cm:3807331
In: rez de rue -1.10m
Type - PredefinedType: FLOOR; Material: OMD_dalle 0.01 m, Béton - Béton coulé sur place 0.13 m, OMD_ITE 10cm 0.1 m
Type - Pset_ReinforcementBarPitchOfSlab - Description: Dalle béton 20cm
Pset_QuantityTakeOff - Reference: Dalle béton 13 cm; sets with these values: 2
Pset_SlabCommon - LoadBearing: no; IsExternal: no; PitchAngle: 0 deg; Reference: Dalle béton 13 cm

# IfcSlab: Sol:Lino black & white doodle, Sol:Lino black & white doodle:3552580
In: Rez de Rue Simon
Type - PredefinedType: FLOOR; Material: OMD_black&white doodle 0.02 m
Type - Pset_ReinforcementBarPitchOfSlab - Description: Dalle béton 20cm
Pset_QuantityTakeOff - Reference: Lino black & white doodle; sets with these values: 2
Pset_SlabCommon - LoadBearing: no; IsExternal: no; PitchAngle: 0 deg; Reference: Lino black & white doodle

# IfcSlab: Sol:Lino parquet, Sol:Lino parquet:3553369
In: Rez de Rue Simon
Type - PredefinedType: FLOOR; Material: OMD_Lino parquet 0.02 m
Type - Pset_ReinforcementBarPitchOfSlab - Description: Dalle béton 20cm
Pset_QuantityTakeOff - Reference: Lino parquet; sets with these values: 2
Pset_SlabCommon - LoadBearing: no; IsExternal: no; PitchAngle: 0 deg; Reference: Lino parquet

# IfcSlab: Sol:OSB 22mm + réagréage 3mm, Sol:OSB 22mm + réagréage 3mm:3314762
In: rez de rue -1.10m
Type - PredefinedType: FLOOR; Material: OMD_flotex 2 0.005 m, OMD_Béton blanc 0.01 m, Résineux, bois de construction 0.022 m
Type - Pset_ReinforcementBarPitchOfSlab - Description: Dalle béton 20cm
Type - Pset_SlabCommon - ThermalTransmittance: 5.45455 kg/K/s3
Pset_QuantityTakeOff - Reference: OSB 22mm + réagréage 3mm; sets with these values: 2
Pset_SlabCommon - LoadBearing: no; IsExternal: no; PitchAngle: 0 deg; Reference: OSB 22mm + réagréage 3mm

# IfcSlab: Sol:carrelage effet béton 60*60 (5)
Type - PredefinedType: FLOOR; Material: OMD_carrelage effet béton 0.02 m
Type - Pset_ReinforcementBarPitchOfSlab - Description: Dalle béton 20cm
Pset_QuantityTakeOff - Reference: carrelage effet béton 60*60; sets with these values: 2
Pset_SlabCommon - LoadBearing: no; IsExternal: no; PitchAngle: 0 deg; Reference: carrelage effet béton 60*60
Name (Sol:carrelage effet béton 60*60:...) | In
4169943 | rez de rue -1.10m
4170360 | Rez de Rue Simon
4170672 | Rez de Rue Simon
4170710 | Rez de Rue Simon
5192790 | rez de rue -1.10m

# IfcSlab: Sol:corniche, Sol:corniche:3298970
In: 2-R+2
Type - PredefinedType: FLOOR; Material: OMD_ anthracite 0.05 m
Type - Pset_ReinforcementBarPitchOfSlab - Description: Dalle béton 20cm
Pset_QuantityTakeOff - Reference: corniche; sets with these values: 2
Pset_SlabCommon - LoadBearing: no; IsExternal: no; PitchAngle: 0 deg; Reference: corniche

# IfcSlab: Sol:corniche 2, Sol:corniche 2:3306643
In: 3-Combles
Type - PredefinedType: FLOOR; Material: OMD_Béton blanc 0.2 m
Type - Pset_ReinforcementBarPitchOfSlab - Description: Dalle béton 20cm
Pset_QuantityTakeOff - Reference: corniche 2; sets with these values: 2
Pset_SlabCommon - LoadBearing: no; IsExternal: no; PitchAngle: 0 deg; Reference: corniche 2

# IfcSlab: Sol:estrade, Sol:estrade:3285294
In: R-1
Type - PredefinedType: FLOOR; Material: OMD_Béton blanc 0.15 m
Type - Pset_ReinforcementBarPitchOfSlab - Description: Dalle béton 20cm
Pset_QuantityTakeOff - Reference: estrade; sets with these values: 2
Pset_SlabCommon - LoadBearing: no; IsExternal: no; PitchAngle: 0 deg; Reference: estrade

# IfcSlab: Sol:pl travail, Sol:pl travail:3499372
In: Rez de Rue Simon
PredefinedType: FLOOR
Pset_QuantityTakeOff - Reference: pl travail; sets with these values: 2
Pset_SlabCommon - LoadBearing: no; IsExternal: no; PitchAngle: 0 deg; Reference: pl travail

# IfcSlab: Sol:pl travail (4)
Type - PredefinedType: FLOOR; Material: OMD-plan de travail béton 0.035 m
Type - Pset_ReinforcementBarPitchOfSlab - Description: Dalle béton 20cm
Pset_QuantityTakeOff - Reference: pl travail; sets with these values: 2
Pset_SlabCommon - LoadBearing: no; IsExternal: no; PitchAngle: 0 deg; Reference: pl travail
Name (Sol:pl travail:...) | In
2 x 3499372 | Rez de Rue Simon
4237932 | rez de rue -1.10m
4237954 | rez de rue -1.10m

# IfcSlab: Sol:tablettes (2)
In: Rez de Rue Simon
Type - PredefinedType: FLOOR; Material: 10 Oak 0.08 m
Type - Pset_ReinforcementBarPitchOfSlab - Description: Dalle béton 20cm
Pset_QuantityTakeOff - Reference: tablettes; sets with these values: 2
Pset_SlabCommon - LoadBearing: no; IsExternal: no; PitchAngle: 0 deg; Reference: tablettes
Name (Sol:tablettes:...)
4028647
4028647:2

# IfcSlab: Toit de base:Toit dallettes 80*40, Toit de base:Toit dallettes 80*40:4655178
In: 0- Rdc
PredefinedType: ROOF; Material: OMD-Lame terasse composite 0.04 m, OMD-Vide 0.25 m, Maçonnerie - Isolant 0.1 m
Pset_QuantityTakeOff - Reference: Toit dallettes 80*40; sets with these values: 2
Pset_SlabCommon - IsExternal: yes; Reference: Toit dallettes 80*40; PitchAngle: 0.51 deg

# IfcSlab: Toit de base:Toit végétalisée (3)
In: 0- Rdc
PredefinedType: ROOF; Material: OMD _toiture végétalisée 0.05 m, OMD_couche drainante 0.05 m, Maçonnerie - Isolant 0.16 m
Pset_QuantityTakeOff - Reference: Toit végétalisée; sets with these values: 2
Pset_SlabCommon - IsExternal: yes; Reference: Toit végétalisée; PitchAngle: 0.51 deg
Name (Toit de base:Toit végétalisée:...)
4081846
4081980
4655724

# IfcSlab: Toit de base:toit terrasse 35 (8)
PredefinedType: ROOF; Material: OMD tranche 0.35 m
Pset_QuantityTakeOff - Reference: toit terrasse 35; sets with these values: 2
Pset_SlabCommon - IsExternal: yes; Reference: toit terrasse 35
Name (Toit de base:toit terrasse 35:...) | In | PitchAngle (deg)
3495543 | 0- Rdc | 0.51
3495677 | 0- Rdc | 0.51
3495768 | 0- Rdc | 0.51
3495828 | 0- Rdc | 0.51
3495856 | 0- Rdc | 0.51
3495888 | 0- Rdc | 0.51
3496000 | 0- Rdc | 0.51
4711984 | 2-R+2 | 0

# IfcStair: Escalier coulé sur place:Monobloc (21)
Pset_QuantityTakeOff - Reference: Monobloc
Pset_StairCommon - IsExternal: no; Reference: Monobloc
Name (Escalier coulé sur place:Escalier:...) | In | ShapeType | NumberOfRiser | NumberOfTreads | RiserHeight (m) | TreadLength (m)
3228538 | 0- Rdc | HALF_TURN_STAIR | 22 | 20 | 0.161364 | 0.28
3231157 | 0- Rdc | HALF_TURN_STAIR | 22 | 20 | 0.156818 | 0.28
3234227 | 0- Rdc | HALF_TURN_STAIR | 22 | 20 | 0.156818 | 0.28
3239510 | 0- Rdc | HALF_TURN_STAIR | 22 | 20 | 0.161364 | 0.28
3251507 | Rez de Rue Simon | HALF_TURN_STAIR | 22 | 20 | 0.161364 | 0.28
3257963 | Rez de Rue Simon | HALF_TURN_STAIR | 22 | 20 | 0.161364 | 0.28
3258041 | Rez de Rue Simon | HALF_TURN_STAIR | 22 | 20 | 0.161364 | 0.28
3258121 | Rez de Rue Simon | HALF_TURN_STAIR | 22 | 20 | 0.161364 | 0.28
3285199 | R-1 | STRAIGHT_RUN_STAIR | 5 | 4 | 0.146 | 0.28
3285236 | R-1 | STRAIGHT_RUN_STAIR | 5 | 4 | 0.146 | 0.28
3291574 | R-1 |  | 18 | 16 | 0.153889 | 0.28
3294087 | 1-R+1 | HALF_TURN_STAIR | 22 | 20 | 0.161364 | 0.28
3294156 | 1-R+1 | HALF_TURN_STAIR | 22 | 20 | 0.161364 | 0.307273
3294221 | 1-R+1 | HALF_TURN_STAIR | 22 | 20 | 0.161364 | 0.307273
3294290 | 1-R+1 | HALF_TURN_STAIR | 22 | 20 | 0.161364 | 0.28
3320616 | rez de rue -1.10m | STRAIGHT_RUN_STAIR | 7 | 6 | 0.154286 | 0.28
3631488 | 0- Rdc | STRAIGHT_RUN_STAIR | 11 | 10 | 0.184559 | 0.260882
3798358 | Rez de Rue Simon | STRAIGHT_RUN_STAIR | 5 | 4 | 0.153333 | 0.323333
3799033 | Rez de Rue Simon | STRAIGHT_RUN_STAIR | 5 | 4 | 0.153333 | 0.323333
4134805 | R-1 |  | 18 | 16 | 0.153889 | 0.28
5437309 | rez de rue -1.10m | STRAIGHT_RUN_STAIR | 7 | 6 | 0.154286 | 0.28

# IfcStair: Escalier coulé sur place:Monobloc 2 (2)
In: R-1
ShapeType: STRAIGHT_RUN_STAIR
Pset_QuantityTakeOff - Reference: Monobloc 2
Pset_StairCommon - IsExternal: no; Reference: Monobloc 2; NumberOfRiser: 5; NumberOfTreads: 4; RiserHeight: 0.13 m; TreadLength: 0.3 m
Name (Escalier coulé sur place:Escalier:...)
3285303
3285306

# IfcStairFlight: Volée monobloc:Nez de marche 5 mm (3)
Material: <Unnamed>
Pset_QuantityTakeOff - Reference: Nez de marche 5 mm
Pset_StairFlightCommon - Reference: Nez de marche 5 mm; NosingLength: 0.005 m
Name (Escalier coulé sur place:Escalier:...) | In | NumberOfRiser = Pset_StairFlightCommon, NumberOfRiser | NumberOfTreads = Pset_StairFlightCommon, NumberOfTreads | RiserHeight (m) | TreadLength (m) | Pset_StairFlightCommon, RiserHeight (m) | Pset_StairFlightCommon, TreadLength (m) = TreadLengthAtOffset (m) = TreadLengthAtInnerSide (m)
3631488 Run 1 | 0- Rdc | 11 | 10 | 0.605508 | 0.855913 | 0.184559 | 0.260882
3798358 Run 1 | Rez de Rue Simon | 5 | 4 | 0.503062 | 1.0608 | 0.153333 | 0.323333
3799033 Run 1 | Rez de Rue Simon | 5 | 4 | 0.503062 | 1.0608 | 0.153333 | 0.323333

# IfcStairFlight: Volée monobloc:Nez de marche 5 mm (34)
Type - PredefinedType: STRAIGHT
Pset_QuantityTakeOff - Reference: Nez de marche 5 mm
Pset_StairFlightCommon - Reference: Nez de marche 5 mm; NosingLength: 0.005 m
Name (Escalier coulé sur place:Escalier:...) | In | NumberOfRiser = Pset_StairFlightCommon, NumberOfRiser | NumberOfTreads = Pset_StairFlightCommon, NumberOfTreads | RiserHeight (m) | TreadLength (m) | Material | Pset_StairFlightCommon, RiserHeight (m) | Pset_StairFlightCommon, TreadLength (m) = TreadLengthAtOffset (m) = TreadLengthAtInnerSide (m) | WalkingLineOffset (m)
3228538 Run 1 | 0- Rdc | 11 | 10 | 0.529408 | 0.918635 | <Unnamed> | 0.161364 | 0.28 | 2.05052
3228538 Run 2 | 0- Rdc | 11 | 10 | 0.529408 | 0.918635 | <Unnamed> | 0.161364 | 0.28 | 2.05052
3231157 Run 1 | 0- Rdc | 11 | 10 | 0.514495 | 0.918635 | <Unnamed> | 0.156818 | 0.28 | 2.05052
3231157 Run 2 | 0- Rdc | 11 | 10 | 0.514495 | 0.918635 | <Unnamed> | 0.156818 | 0.28 | 2.05052
3234227 Run 1 | 0- Rdc | 11 | 10 | 0.514495 | 0.918635 | <Unnamed> | 0.156818 | 0.28 | 2.05052
3234227 Run 2 | 0- Rdc | 11 | 10 | 0.514495 | 0.918635 | <Unnamed> | 0.156818 | 0.28 | 2.05052
3239510 Run 1 | 0- Rdc | 11 | 10 | 0.529408 | 0.918635 | <Unnamed> | 0.161364 | 0.28 | 2.05052
3239510 Run 2 | 0- Rdc | 11 | 10 | 0.529408 | 0.918635 | <Unnamed> | 0.161364 | 0.28 | 2.05052
3251507 Run 1 | Rez de Rue Simon | 11 | 10 | 0.529408 | 0.918635 | <Unnamed> | 0.161364 | 0.28 | 2.05052
3251507 Run 2 | Rez de Rue Simon | 11 | 10 | 0.529408 | 0.918635 | <Unnamed> | 0.161364 | 0.28 | 2.05052
3257963 Run 1 | Rez de Rue Simon | 11 | 10 | 0.529408 | 0.918635 | <Unnamed> | 0.161364 | 0.28 | 2.05052
3257963 Run 2 | Rez de Rue Simon | 11 | 10 | 0.529408 | 0.918635 | <Unnamed> | 0.161364 | 0.28 | 2.05052
3258041 Run 1 | Rez de Rue Simon | 11 | 10 | 0.529408 | 0.918635 | <Unnamed> | 0.161364 | 0.28 | 2.05052
3258041 Run 2 | Rez de Rue Simon | 11 | 10 | 0.529408 | 0.918635 | <Unnamed> | 0.161364 | 0.28 | 2.05052
3258121 Run 1 | Rez de Rue Simon | 11 | 10 | 0.529408 | 0.918635 | <Unnamed> | 0.161364 | 0.28 | 2.05052
3258121 Run 2 | Rez de Rue Simon | 11 | 10 | 0.529408 | 0.918635 | <Unnamed> | 0.161364 | 0.28 | 2.05052
3285199 Run 1 | R-1 | 5 | 4 | 0.479003 | 0.918635 | <Unnamed> | 0.146 | 0.28 | 4.24049
3285236 Run 1 | R-1 | 5 | 4 | 0.479003 | 0.918635 | <Unnamed> | 0.146 | 0.28 | 4.24049
3285303 Run 1 | R-1 | 5 | 4 | 0.426509 | 0.984252 | <Unnamed> | 0.13 | 0.3 | 1.14845
3285306 Run 1 | R-1 | 5 | 4 | 0.426509 | 0.984252 | <Unnamed> | 0.13 | 0.3 | 1.14845
3291574 Run 1 | R-1 | 11 | 10 | 0.504885 | 0.918635 | <Unnamed> | 0.153889 | 0.28 | 2.05052
3291574 Run 2 | R-1 | 7 | 6 | 0.504885 | 0.918635 | <Unnamed> | 0.153889 | 0.28 | 2.05052
3294087 Run 1 | 1-R+1 | 11 | 10 | 0.529408 | 0.918635 | <Unnamed> | 0.161364 | 0.28 | 2.05052
3294087 Run 2 | 1-R+1 | 11 | 10 | 0.529408 | 0.918635 | <Unnamed> | 0.161364 | 0.28 | 2.05052
3294156 Run 1 | 1-R+1 | 11 | 10 | 0.529408 | 1.00811 | <Unnamed> | 0.161364 | 0.307273 | 2.05052
3294156 Run 2 | 1-R+1 | 11 | 10 | 0.529408 | 1.00811 | <Unnamed> | 0.161364 | 0.307273 | 2.05052
3294221 Run 1 | 1-R+1 | 11 | 10 | 0.529408 | 1.00811 | <Unnamed> | 0.161364 | 0.307273 | 2.05052
3294221 Run 2 | 1-R+1 | 11 | 10 | 0.529408 | 1.00811 | <Unnamed> | 0.161364 | 0.307273 | 2.05052
3294290 Run 1 | 1-R+1 | 11 | 10 | 0.529408 | 0.918635 | <Unnamed> | 0.161364 | 0.28 | 2.05052
3294290 Run 2 | 1-R+1 | 11 | 10 | 0.529408 | 0.918635 | <Unnamed> | 0.161364 | 0.28 | 2.05052
3320616 Run 1 | rez de rue -1.10m | 7 | 6 | 0.506187 | 0.918635 | OMD_RAL1032 | 0.154286 | 0.28 | 2.54265
4134805 Run 1 | R-1 | 11 | 10 | 0.504885 | 0.918635 | <Unnamed> | 0.153889 | 0.28 | 2.05052
4134805 Run 2 | R-1 | 7 | 6 | 0.504885 | 0.918635 | <Unnamed> | 0.153889 | 0.28 | 2.05052
5437309 Run 1 | rez de rue -1.10m | 7 | 6 | 0.506187 | 0.918635 | OMD_RAL1032 | 0.154286 | 0.28 | 1.80446

# IfcWall: Mur de base:BA 20, Mur de base:BA 20:5442001
In: rez de rue -1.10m
Type - PredefinedType: STANDARD; Material: Béton - Béton coulé sur place 0.2 m
Type - Pset_ReinforcementBarPitchOfWall - Description: Voile béton armé 20cm
Pset_QuantityTakeOff - Reference: BA 20; sets with these values: 2
Pset_WallCommon - IsExternal: yes; ExtendToStructure: no; LoadBearing: no; Reference: BA 20

# IfcWall: Mur de base:BA 20 + isol (9)
In: 0- Rdc
Type - PredefinedType: STANDARD; Material: Maçonnerie - Isolant 0.1 m, Béton - Béton coulé sur place 0.2 m
Type - Pset_ReinforcementBarPitchOfWall - Description: Voile béton armé 20cm
Pset_QuantityTakeOff - Reference: BA 20 + isol; sets with these values: 2
Pset_WallCommon - IsExternal: yes; ExtendToStructure: no; LoadBearing: no; Reference: BA 20 + isol
Name (Mur de base:BA 20 + isol:...)
3451478
3451479
3451480
3451481
4078339
4078349
4078354
4078359
4078364

# IfcWall: Mur de base:BARDAGE (8)
In: Rez de Rue Simon
Type - PredefinedType: STANDARD; Material: OMD-Bardage beige foncé 0.035 m, Mur par défaut 0.05 m
Type - Pset_ReinforcementBarPitchOfWall - Description: Voile béton armé 20cm
Pset_QuantityTakeOff - Reference: BARDAGE; sets with these values: 2
Pset_WallCommon - IsExternal: yes; ExtendToStructure: no; LoadBearing: no; Reference: BARDAGE
Name (Mur de base:BARDAGE:...)
4848773
4848779
4848785
4848791
4848797
4848803
4848809
4848815

# IfcWall: Mur de base:Cloison 100mm (4)
Type - PredefinedType: STANDARD; Material: OMD_Cloison 100mm 0.1 m
Type - Pset_ReinforcementBarPitchOfWall - Description: Cloison 98/48 BA25
Pset_QuantityTakeOff - Reference: Cloison 100mm; sets with these values: 2
Pset_WallCommon - LoadBearing: no; IsExternal: no; Reference: Cloison 100mm
Name (Mur de base:Cloison 100mm:...) | In | ExtendToStructure
3377504 | Rez de Rue Simon | yes
3592538 | rez de rue -1.10m | yes
3598239 | rez de rue -1.10m | yes
4004467 | Rez de Rue Simon | no

# IfcWall: Mur de base:Cloison 100mm CF1h (12)
Type - PredefinedType: STANDARD; Material: OMD_Cloison 100mm CF1h 0.1 m
Type - Pset_ReinforcementBarPitchOfWall - Description: Cloison 98/48 BA25 CF1h
Pset_QuantityTakeOff - Reference: Cloison 100mm CF1h; sets with these values: 2
Pset_WallCommon - LoadBearing: no; IsExternal: no; Reference: Cloison 100mm CF1h
Name (Mur de base:Cloison 100mm CF1h:...) | In | ExtendToStructure
3378583 | rez de rue -1.10m | yes
3453910 | rez de rue -1.10m | yes
3541852 | rez de rue -1.10m | no
3542126 | rez de rue -1.10m | no
3786123 | rez de rue -1.10m | no
3786517 | rez de rue -1.10m | yes
3974351 | rez de rue -1.10m | no
3977831 | rez de rue -1.10m | yes
4137910 | rez de rue -1.10m | yes
4138453 | rez de rue -1.10m | yes
4203980 | R-1 | yes
4204071 | R-1 | yes

# IfcWall: Mur de base:Cloison bois isolant 85mm (2)
Type - PredefinedType: STANDARD; Material: Maçonnerie - Isolant 0.085 m, Mur par défaut 0.05 m, OMD_panneaux bois 0.025 m
Type - Pset_ReinforcementBarPitchOfWall - Description: Carreaux de Platre 7 cm
Pset_QuantityTakeOff - Reference: Cloison bois isolant 85mm; sets with these values: 2
Pset_WallCommon - LoadBearing: no; IsExternal: no; Reference: Cloison bois isolant 85mm
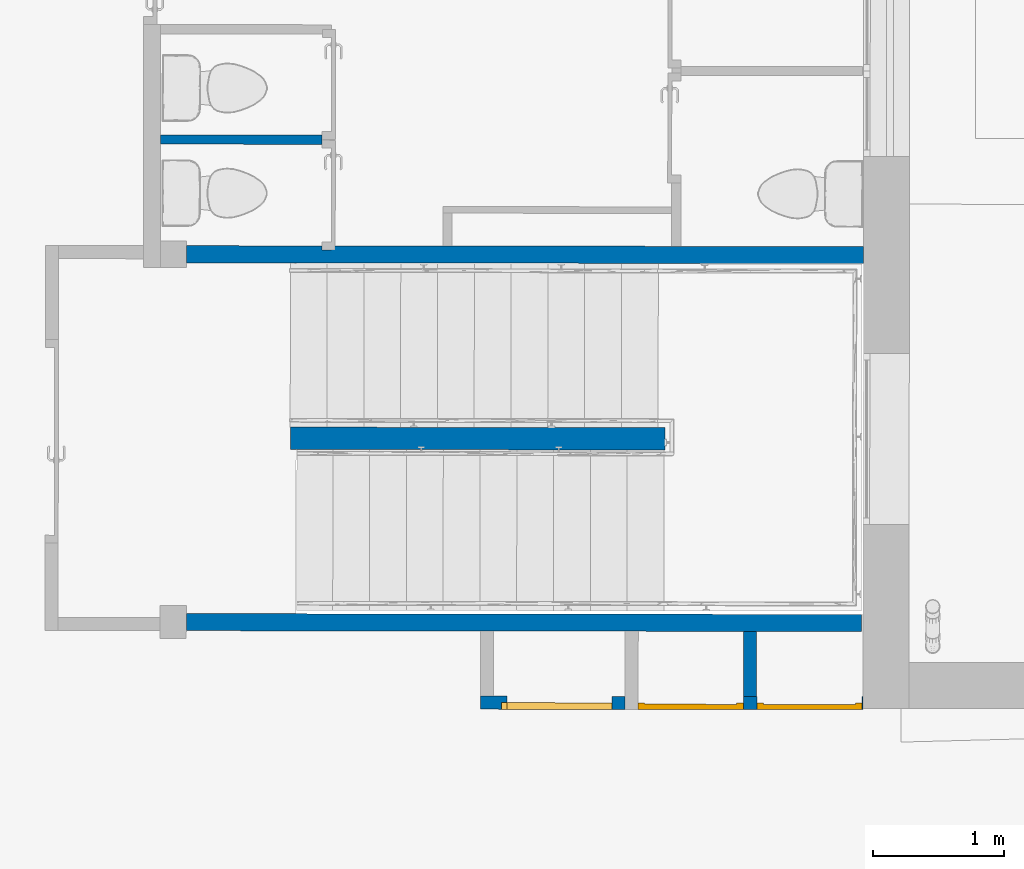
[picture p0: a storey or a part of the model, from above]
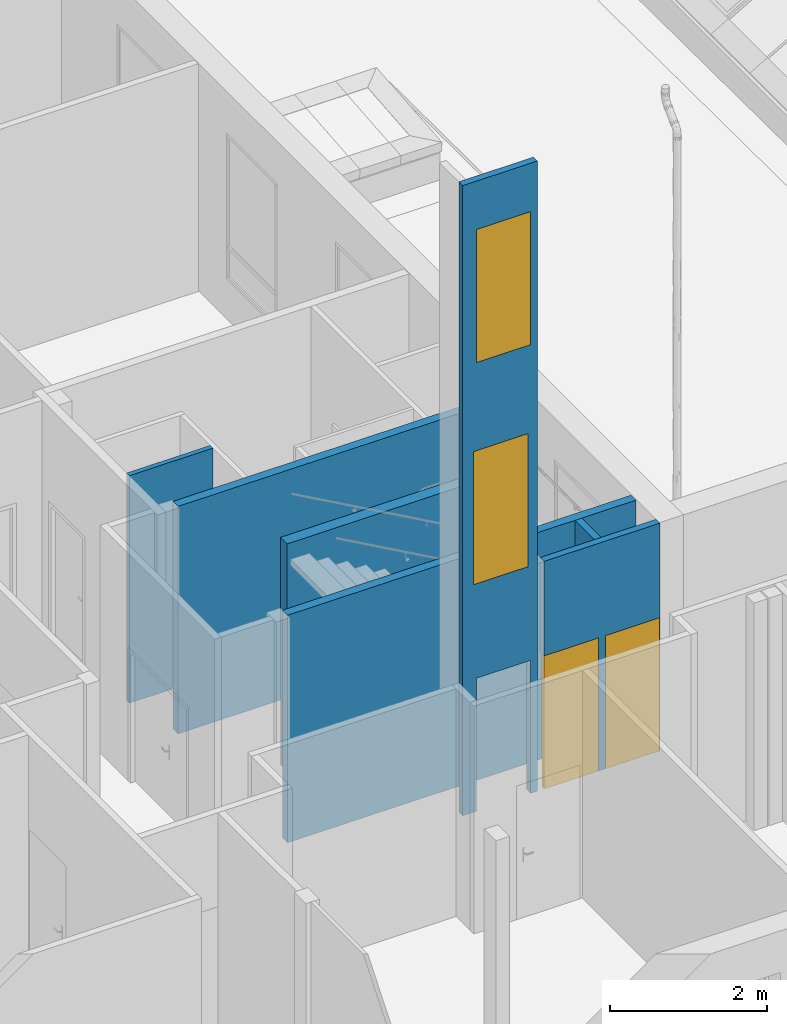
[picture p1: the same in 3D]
Properties of the parts of a building model (IFC2X3), part 4 of 4

# IfcWall: Mur de base:Cloison bois isolant 85mm (2)
Name (Mur de base:Cloison bois isolant 85mm:...) | In | ExtendToStructure
3576695 | rez de rue -1.10m | yes
3577404 | Rez de Rue Simon | no

# IfcWall: Mur de base:ITI 120mm+BA13 (2)
In: rez de rue -1.10m
Type - PredefinedType: STANDARD; Material: OMD_BA 25 0.013 m, Mur par défaut 0.02 m, Maçonnerie - Isolant 0.12 m
Type - Pset_ReinforcementBarPitchOfWall - Description: Cloison 98/48 BA25
Pset_QuantityTakeOff - Reference: ITI 120mm+BA13; sets with these values: 2
Pset_WallCommon - LoadBearing: no; IsExternal: no; Reference: ITI 120mm+BA13
Name (Mur de base:ITI 120mm+BA13:...) | ExtendToStructure
3826156 | yes
4186858 | no

# IfcWall: Mur de base:ITI85+ba13, Mur de base:ITI85+ba13:4024571
In: rez de rue -1.10m
Type - PredefinedType: STANDARD; Material: Maçonnerie - Isolant 0.085 m, TV_Black 0.013 m
Type - Pset_ReinforcementBarPitchOfWall - Description: Carreaux de Platre 7 cm
Pset_QuantityTakeOff - Reference: ITI85+ba13; sets with these values: 2
Pset_WallCommon - LoadBearing: no; IsExternal: no; ExtendToStructure: yes; Reference: ITI85+ba13

# IfcWall: Mur de base:MUR 10 (4)
Type - PredefinedType: STANDARD; Material: OMD_Béton blanc 0.1 m
Type - Pset_ReinforcementBarPitchOfWall - Description: Voile béton armé 20cm
Pset_QuantityTakeOff - Reference: MUR 10; sets with these values: 2
Pset_WallCommon - IsExternal: yes; ExtendToStructure: no; LoadBearing: no; Reference: MUR 10
Name (Mur de base:MUR 10:...) | In
3239279 | 0- Rdc
3239283 | 0- Rdc
3251504 | Rez de Rue Simon
3260421 | Rez de Rue Simon

# IfcWall: Mur de base:MUR 13 (12)
Type - PredefinedType: STANDARD; Material: OMD_Béton blanc 0.13 m
Type - Pset_ReinforcementBarPitchOfWall - Description: Voile béton armé 20cm
Pset_QuantityTakeOff - Reference: MUR 13; sets with these values: 2
Pset_WallCommon - IsExternal: yes; ExtendToStructure: no; LoadBearing: no; Reference: MUR 13
Name (Mur de base:MUR 13:...) | In
3251658 | Rez de Rue Simon
3251945 | Rez de Rue Simon
3255006 | Rez de Rue Simon
3259861 | Rez de Rue Simon
3267279 | Rez de Rue Simon
3268351 | Rez de Rue Simon
3269455 | Rez de Rue Simon
3269459 | Rez de Rue Simon
3275586 | R-1
3277080 | R-1
3340371 | R-1
3949852 | R-1

# IfcWall: Mur de base:MUR 20, Mur de base:MUR 20:4770194
In: R-1
Type - PredefinedType: STANDARD; Material: Béton - Béton coulé sur place 0.2 m
Type - Pset_ReinforcementBarPitchOfWall - Description: Voile béton armé 20cm
Pset_QuantityTakeOff - Reference: MUR 20; sets with these values: 2
Pset_WallCommon - IsExternal: yes; ExtendToStructure: no; LoadBearing: no; Reference: MUR 20

# IfcWall: Mur de base:MUR 26, Mur de base:MUR 26:3291796
In: R-1
Type - PredefinedType: STANDARD; Material: OMD_Béton blanc 0.26 m
Type - Pset_ReinforcementBarPitchOfWall - Description: Voile béton armé 20cm
Pset_QuantityTakeOff - Reference: MUR 26; sets with these values: 2
Pset_WallCommon - IsExternal: yes; ExtendToStructure: no; LoadBearing: no; Reference: MUR 26

# IfcWall: Mur de base:MUR 27, Mur de base:MUR 27:4884612
In: R-1
Type - PredefinedType: STANDARD; Material: OMD_Béton blanc 0.27 m
Type - Pset_ReinforcementBarPitchOfWall - Description: Voile béton armé 20cm
Pset_QuantityTakeOff - Reference: MUR 27; sets with these values: 2
Pset_WallCommon - IsExternal: yes; ExtendToStructure: no; LoadBearing: no; Reference: MUR 27

# IfcWall: Mur de base:MUR 30 (13)
Type - PredefinedType: STANDARD; Material: OMD_Béton blanc 0.3 m
Type - Pset_ReinforcementBarPitchOfWall - Description: Voile béton armé 20cm
Pset_QuantityTakeOff - Reference: MUR 30; sets with these values: 2
Pset_WallCommon - IsExternal: yes; LoadBearing: no; Reference: MUR 30
Name (Mur de base:MUR 30:...) | In | ExtendToStructure
3251064 | Rez de Rue Simon | no
3258377 | Rez de Rue Simon | no
3258378 | Rez de Rue Simon | no
3259955 | Rez de Rue Simon | no
3271948 | R-1 | no
3271949 | R-1 | no
3297109 | 2-R+2 | yes
3297111 | 2-R+2 | yes
3297112 | 2-R+2 | yes
3630292 | Rez de Rue Simon | no
3960417 | R-1 | no
4897562 | R-1 | no
4897992 | Rez de Rue Simon | no

# IfcWall: Mur de base:MUR 35 (9)
Type - PredefinedType: STANDARD; Material: OMD_Béton blanc 0.35 m
Type - Pset_ReinforcementBarPitchOfWall - Description: Voile béton armé 20cm
Pset_QuantityTakeOff - Reference: MUR 35; sets with these values: 2
Pset_WallCommon - Reference: MUR 35; IsExternal: yes; ExtendToStructure: no; LoadBearing: no
Name (Mur de base:MUR 35:...) | In
3227822 | 0- Rdc
3227895 | 0- Rdc
3258374 | Rez de Rue Simon
3258375 | Rez de Rue Simon
3291892 | 0- Rdc
3295097 | 1-R+1
3625902 | R-1
3626806 | R-1
3632823 | 0- Rdc

# IfcWall: Mur de base:MUR 49.5, Mur de base:MUR 49.5:3260417
In: Rez de Rue Simon
Type - PredefinedType: STANDARD; Material: OMD_Béton blanc 0.495 m
Type - Pset_ReinforcementBarPitchOfWall - Description: Voile béton armé 20cm
Pset_QuantityTakeOff - Reference: MUR 49.5; sets with these values: 2
Pset_WallCommon - IsExternal: yes; ExtendToStructure: no; LoadBearing: no; Reference: MUR 49.5

# IfcWall: Mur de base:MUR 5 PIERRE, Mur de base:MUR 5 PIERRE:4312838
In: Rez de Rue Simon
Type - PredefinedType: STANDARD; Material: OMD_PIERRE 0.05 m
Type - Pset_ReinforcementBarPitchOfWall - Description: Voile béton armé 20cm
Pset_QuantityTakeOff - Reference: MUR 5 PIERRE; sets with these values: 2
Pset_WallCommon - IsExternal: yes; ExtendToStructure: no; LoadBearing: no; Reference: MUR 5 PIERRE

# IfcWall: Mur de base:ba13 (5)
In: Rez de Rue Simon
Type - PredefinedType: STANDARD; Material: OMD_Cloison 100mm 0.013 m
Type - Pset_ReinforcementBarPitchOfWall - Description: Cloison 98/48 BA25
Pset_QuantityTakeOff - Reference: ba13; sets with these values: 2
Pset_WallCommon - ExtendToStructure: no; LoadBearing: no; IsExternal: no; Reference: ba13
Name (Mur de base:ba13:...)
3558067
3558160
3558287
3558419
3558644

# IfcWall: Mur de base:faïence SANITAIRES (4)
In: Rez de Rue Simon
Type - PredefinedType: STANDARD; Material: OMD-faience saniataires 0.02 m
Type - Pset_ReinforcementBarPitchOfWall - Description: Cloison en stratifié compact
Pset_QuantityTakeOff - Reference: faïence SANITAIRES; sets with these values: 2
Pset_WallCommon - ExtendToStructure: no; LoadBearing: no; IsExternal: no; Reference: faïence SANITAIRES
Name (Mur de base:faïence SANITAIRES:...)
4210857
4211073
4211286
4211336

# IfcWall: Mur de base:faïence douches, Mur de base:faïence douches:4293349
In: rez de rue -1.10m
Type - PredefinedType: STANDARD; Material: OMD faience douche 60*120 0.02 m
Type - Pset_ReinforcementBarPitchOfWall - Description: Cloison en stratifié compact
Pset_QuantityTakeOff - Reference: faïence douches; sets with these values: 2
Pset_WallCommon - ExtendToStructure: no; LoadBearing: no; IsExternal: no; Reference: faïence douches

# IfcWall: Mur de base:joue plâtre (2)
In: Rez de Rue Simon
Type - PredefinedType: STANDARD; Material: OMD_Cloison 100mm 0.02 m
Type - Pset_ReinforcementBarPitchOfWall - Description: Cloison 98/48 BA25
Pset_QuantityTakeOff - Reference: joue plâtre; sets with these values: 2
Pset_WallCommon - ExtendToStructure: no; LoadBearing: no; IsExternal: no; Reference: joue plâtre
Name (Mur de base:joue plâtre:...)
5460708
5466884

# IfcWall: Mur de base:miroir (3)
In: Rez de Rue Simon
Type - PredefinedType: STANDARD; Material: OMD-miroir 0.005 m
Type - Pset_ReinforcementBarPitchOfWall - Description: Cloison en stratifié compact
Pset_QuantityTakeOff - Reference: miroir; sets with these values: 2
Pset_WallCommon - ExtendToStructure: no; LoadBearing: no; IsExternal: no; Reference: miroir
Name (Mur de base:miroir:...)
4219433
4219595
5338576

# IfcWallStandardCase: Mur de base:BA 20 (5)
In: rez de rue -1.10m
Type - PredefinedType: STANDARD; Material: Béton - Béton coulé sur place 0.2 m
Type - Pset_ReinforcementBarPitchOfWall - Description: Voile béton armé 20cm
Pset_QuantityTakeOff - Reference: BA 20; sets with these values: 2
Pset_WallCommon - IsExternal: yes; LoadBearing: no; Reference: BA 20
Name (Mur de base:BA 20:...) | ExtendToStructure
3797485 | no
3797611 | no
5441278 | no
5441348 | no
5441956 | yes

# IfcWallStandardCase: Mur de base:BA 20 + isol (3)
In: 0- Rdc
Type - PredefinedType: STANDARD; Material: Maçonnerie - Isolant 0.1 m, Béton - Béton coulé sur place 0.2 m
Type - Pset_ReinforcementBarPitchOfWall - Description: Voile béton armé 20cm
Pset_QuantityTakeOff - Reference: BA 20 + isol; sets with these values: 2
Pset_WallCommon - IsExternal: yes; ExtendToStructure: no; LoadBearing: no; Reference: BA 20 + isol
Name (Mur de base:BA 20 + isol:...)
4078344
4078369
4080102

# IfcWallStandardCase: Mur de base:BARDAGE (36)
In: Rez de Rue Simon
Type - PredefinedType: STANDARD; Material: OMD-Bardage beige foncé 0.035 m, Mur par défaut 0.05 m
Type - Pset_ReinforcementBarPitchOfWall - Description: Voile béton armé 20cm
Pset_QuantityTakeOff - Reference: BARDAGE; sets with these values: 2
Pset_WallCommon - IsExternal: yes; ExtendToStructure: no; LoadBearing: no; Reference: BARDAGE
Name (Mur de base:BARDAGE:...)
4848143
4848149
4848155
4848370
4848376
4848384
4848390
4848398
4848404
4848410
4848416
4848424
4848432
4848438
4848482
4848616
4848622
4848628
4848634
4848640
4848646
4848652
4848658
4848664
4848670
4848676
4848682
4848725
4848731
4848737
4848743
4848749
4848755
4848761
4848767
5184391

# IfcWallStandardCase: Mur de base:BARDAGE perforé, Mur de base:BARDAGE perforé:4315134
In: Rez de Rue Simon
Type - PredefinedType: STANDARD; Material: OMD-bardage perforé 0.035 m, Mur par défaut 0.05 m
Type - Pset_ReinforcementBarPitchOfWall - Description: Voile béton armé 20cm
Pset_QuantityTakeOff - Reference: BARDAGE perforé; sets with these values: 2
Pset_WallCommon - IsExternal: yes; ExtendToStructure: no; LoadBearing: no; Reference: BARDAGE perforé

# IfcWallStandardCase: Mur de base:Cloison 100mm (22)
Type - PredefinedType: STANDARD; Material: OMD_Cloison 100mm 0.1 m
Type - Pset_ReinforcementBarPitchOfWall - Description: Cloison 98/48 BA25
Pset_QuantityTakeOff - Reference: Cloison 100mm; sets with these values: 2
Pset_WallCommon - LoadBearing: no; IsExternal: no; Reference: Cloison 100mm
Name (Mur de base:Cloison 100mm:...) | In | ExtendToStructure
3592407 | rez de rue -1.10m | yes
3598364 | rez de rue -1.10m | yes
3693013 | Rez de Rue Simon | no
4035034 | 0- Rdc | no
4035082 | 0- Rdc | no
4158997 | rez de rue -1.10m | yes
4165918 | Rez de Rue Simon | no
4230413 | rez de rue -1.10m | yes
4230414 | rez de rue -1.10m | yes
4234089 | rez de rue -1.10m | yes
4913728 | rez de rue -1.10m | no
4913771 | rez de rue -1.10m | no
4913866 | rez de rue -1.10m | no
4913867 | rez de rue -1.10m | no
4919176 | rez de rue -1.10m | no
4921980 | Rez de Rue Simon | no
5324686 | rez de rue -1.10m | yes
5324731 | rez de rue -1.10m | yes
5434153 | Rez de Rue Simon | no
5434188 | Rez de Rue Simon | no
5439869 | Rez de Rue Simon | no
5439935 | Rez de Rue Simon | no

# IfcWallStandardCase: Mur de base:Cloison 100mm Acoustique (7)
Type - PredefinedType: STANDARD; Material: OMD_Cloison 100mm Acoustique 0.1 m
Type - Pset_ReinforcementBarPitchOfWall - Description: Cloison 98/48 BA25 Duo tech'
Pset_QuantityTakeOff - Reference: Cloison 100mm Acoustique; sets with these values: 2
Pset_WallCommon - LoadBearing: no; IsExternal: no; Reference: Cloison 100mm Acoustique
Name (Mur de base:Cloison 100mm Acoustique:...) | In | ExtendToStructure
4190371 | rez de rue -1.10m | yes
4190455 | rez de rue -1.10m | yes
4721579 | Rez de Rue Simon | no
4721700 | Rez de Rue Simon | no
4721757 | rez de rue -1.10m | no
4721802 | rez de rue -1.10m | no
4722233 | rez de rue -1.10m | yes

# IfcWallStandardCase: Mur de base:Cloison 100mm CF1h (22)
Type - PredefinedType: STANDARD; Material: OMD_Cloison 100mm CF1h 0.1 m
Type - Pset_ReinforcementBarPitchOfWall - Description: Cloison 98/48 BA25 CF1h
Pset_QuantityTakeOff - Reference: Cloison 100mm CF1h; sets with these values: 2
Pset_WallCommon - LoadBearing: no; IsExternal: no; Reference: Cloison 100mm CF1h
Name (Mur de base:Cloison 100mm CF1h:...) | In | ExtendToStructure
3375893 | rez de rue -1.10m | yes
3378586 | rez de rue -1.10m | yes
3532231 | rez de rue -1.10m | yes
3541956 | rez de rue -1.10m | yes
3542083 | rez de rue -1.10m | yes
3542102 | rez de rue -1.10m | no
3562198 | rez de rue -1.10m | yes
3562277 | rez de rue -1.10m | yes
3591002 | rez de rue -1.10m | yes
3591041 | rez de rue -1.10m | yes
3607132 | R-1 | no
3800630 | R-1 | yes
4005539 | Rez de Rue Simon | no
4130642 | R-1 | no
4130696 | R-1 | no
4131028 | R-1 | no
4131073 | R-1 | no
4138279 | rez de rue -1.10m | yes
4911990 | rez de rue -1.10m | no
4919177 | rez de rue -1.10m | yes
5308348 | R-1 | no
5308472 | R-1 | no

# IfcWallStandardCase: Mur de base:Cloison 120mm CF1h, Mur de base:Cloison 120mm CF1h:3534526
In: rez de rue -1.10m
Type - PredefinedType: STANDARD; Material: OMD_Cloison 100mm CF1h 0.12 m
Type - Pset_ReinforcementBarPitchOfWall - Description: Cloison 98/48 BA25 CF1h
Pset_QuantityTakeOff - Reference: Cloison 120mm CF1h; sets with these values: 2
Pset_WallCommon - ExtendToStructure: no; LoadBearing: no; IsExternal: no; Reference: Cloison 120mm CF1h

# IfcWallStandardCase: Mur de base:Cloison 20 Stratifiée (5)
Type - PredefinedType: STANDARD; Material: OMD_Cloison Stratifiée 0.02 m
Type - Pset_ReinforcementBarPitchOfWall - Description: Cloison en stratifié compact
Type - Pset_WallCommon - ThermalTransmittance: 6 kg/K/s3
Pset_QuantityTakeOff - Reference: Cloison 20 Stratifiée; sets with these values: 2
Pset_WallCommon - ExtendToStructure: no; LoadBearing: no; IsExternal: no; Reference: Cloison 20 Stratifiée
Name (Mur de base:Cloison 20 Stratifiée:...) | In
3375345 | Rez de Rue Simon
3375351 | Rez de Rue Simon
3375358 | Rez de Rue Simon
3375359 | Rez de Rue Simon
5287304 | 0- Rdc

# IfcWallStandardCase: Mur de base:Cloison 70mm (8)
In: Rez de Rue Simon
Type - PredefinedType: STANDARD; Material: OMD_Cloison 100mm 0.07 m
Type - Pset_ReinforcementBarPitchOfWall - Description: Cloison 98/48 BA25
Pset_QuantityTakeOff - Reference: Cloison 70mm; sets with these values: 2
Pset_WallCommon - LoadBearing: no; IsExternal: no; Reference: Cloison 70mm
Name (Mur de base:Cloison 70mm:...) | ExtendToStructure
3267391 | no
3375342 | no
4003476 | yes
4016288 | yes
4072474 | no
4072510 | no
4828111 | yes
5366218 | no

# IfcWallStandardCase: Mur de base:Cloison bois (4)
In: rez de rue -1.10m
Type - PredefinedType: STANDARD; Material: Maçonnerie - Isolant 0.12 m, Mur par défaut 0.02 m, OMD_panneaux bois 0.013 m
Type - Pset_ReinforcementBarPitchOfWall - Description: Carreaux de Platre 7 cm
Pset_QuantityTakeOff - Reference: Cloison bois; sets with these values: 2
Pset_WallCommon - ExtendToStructure: no; LoadBearing: no; IsExternal: no; Reference: Cloison bois
Name (Mur de base:Cloison bois:...)
3572526
3572680
3572800
5394835

# IfcWallStandardCase: Mur de base:ITI 120mm+BA13 2, Mur de base:ITI 120mm+BA13 2:5022493
In: rez de rue -1.10m
Type - PredefinedType: STANDARD; Material: OMD_BA 25 0.013 m, Maçonnerie - Isolant 0.12 m
Type - Pset_ReinforcementBarPitchOfWall - Description: Cloison 98/48 BA25
Pset_QuantityTakeOff - Reference: ITI 120mm+BA13 2; sets with these values: 2
Pset_WallCommon - LoadBearing: no; IsExternal: no; ExtendToStructure: yes; Reference: ITI 120mm+BA13 2

# IfcWallStandardCase: Mur de base:ITI 120mm+BA13 vide 5cm (2)
In: Rez de Rue Simon
Type - PredefinedType: STANDARD; Material: OMD_BA 25 0.013 m, Mur par défaut 0.05 m, Maçonnerie - Isolant 0.12 m
Type - Pset_ReinforcementBarPitchOfWall - Description: Cloison 98/48 BA25
Pset_QuantityTakeOff - Reference: ITI 120mm+BA13 vide 5cm; sets with these values: 2
Pset_WallCommon - ExtendToStructure: no; LoadBearing: no; IsExternal: no; Reference: ITI 120mm+BA13 vide 5cm
Name (Mur de base:ITI 120mm+BA13 vide 5cm:...)
3825656
3825718

# IfcWallStandardCase: Mur de base:ITI85+ba13 (2)
Type - PredefinedType: STANDARD; Material: Maçonnerie - Isolant 0.085 m, TV_Black 0.013 m
Type - Pset_ReinforcementBarPitchOfWall - Description: Carreaux de Platre 7 cm
Pset_QuantityTakeOff - Reference: ITI85+ba13; sets with these values: 2
Pset_WallCommon - ExtendToStructure: no; LoadBearing: no; IsExternal: no; Reference: ITI85+ba13
Name (Mur de base:ITI85+ba13:...) | In
4024377 | rez de rue -1.10m
4165247 | Rez de Rue Simon

# IfcWallStandardCase: Mur de base:MUR 10 (196)
Type - PredefinedType: STANDARD; Material: OMD_Béton blanc 0.1 m
Type - Pset_ReinforcementBarPitchOfWall - Description: Voile béton armé 20cm
Pset_QuantityTakeOff - Reference: MUR 10; sets with these values: 2
Pset_WallCommon - IsExternal: yes; LoadBearing: no; Reference: MUR 10
Name (Mur de base:MUR 10:...) | In | ExtendToStructure
3228363 | 0- Rdc | no
3228367 | 0- Rdc | no
3229440 | 0- Rdc | no
3229444 | 0- Rdc | no
3229448 | 0- Rdc | no
3229454 | 0- Rdc | no
3229458 | 0- Rdc | no
3229462 | 0- Rdc | yes
3229980 | 0- Rdc | no
3229984 | 0- Rdc | no
3229988 | 0- Rdc | yes
3230015 | 0- Rdc | no
3230019 | 0- Rdc | no
3230023 | 0- Rdc | no
3230143 | 0- Rdc | no
3230153 | 0- Rdc | no
3230159 | 0- Rdc | no
3230163 | 0- Rdc | no
3230169 | 0- Rdc | no
3230175 | 0- Rdc | no
3230179 | 0- Rdc | no
3230183 | 0- Rdc | no
3230187 | 0- Rdc | no
3230191 | 0- Rdc | no
3230198 | 0- Rdc | no
3230202 | 0- Rdc | no
3230206 | 0- Rdc | no
3230214 | 0- Rdc | no
3230218 | 0- Rdc | no
3230222 | 0- Rdc | no
3230228 | 0- Rdc | no
3230232 | 0- Rdc | no
3230236 | 0- Rdc | no
3230240 | 0- Rdc | no
3230244 | 0- Rdc | no
3230248 | 0- Rdc | no
3230252 | 0- Rdc | no
3230258 | 0- Rdc | no
3230445 | 0- Rdc | no
3230449 | 0- Rdc | no
3230457 | 0- Rdc | no
3230552 | 0- Rdc | no
3230556 | 0- Rdc | no
3230568 | 0- Rdc | no
3230663 | 0- Rdc | no
3230667 | 0- Rdc | no
3230671 | 0- Rdc | no
3230675 | 0- Rdc | no
3230683 | 0- Rdc | no
3230687 | 0- Rdc | no
3230855 | 0- Rdc | no
3230859 | 0- Rdc | no
3230863 | 0- Rdc | no
3230867 | 0- Rdc | no
3230871 | 0- Rdc | yes
3232746 | 0- Rdc | no
3232837 | 0- Rdc | no
3232841 | 0- Rdc | no
3232845 | 0- Rdc | no
3232851 | 0- Rdc | no
3232906 | 0- Rdc | no
3232910 | 0- Rdc | no
3232914 | 0- Rdc | no
3232920 | 0- Rdc | no
3232924 | 0- Rdc | no
3232928 | 0- Rdc | no
3232932 | 0- Rdc | no
3232938 | 0- Rdc | no
3232942 | 0- Rdc | no
3232946 | 0- Rdc | no
3232950 | 0- Rdc | no
3233183 | 0- Rdc | no
3233187 | 0- Rdc | no
3233191 | 0- Rdc | no
3233195 | 0- Rdc | no
3233199 | 0- Rdc | no
3233441 | 0- Rdc | no
3233447 | 0- Rdc | no
3233451 | 0- Rdc | no
3233455 | 0- Rdc | no
3233459 | 0- Rdc | no
3233538 | 0- Rdc | no
3233542 | 0- Rdc | no
3233546 | 0- Rdc | no
3233550 | 0- Rdc | no
3233928 | 0- Rdc | no
3233932 | 0- Rdc | no
3233936 | 0- Rdc | no
3234887 | 0- Rdc | no
3234891 | 0- Rdc | no
3234895 | 0- Rdc | no
3238244 | 0- Rdc | no
3238248 | 0- Rdc | no
3238252 | 0- Rdc | no
3238273 | 0- Rdc | no
3238381 | 0- Rdc | no
3238491 | 0- Rdc | no
3238495 | 0- Rdc | no
3238699 | 0- Rdc | no
3238703 | 0- Rdc | no
3238707 | 0- Rdc | no
3238711 | 0- Rdc | no
3238814 | 0- Rdc | no
3238855 | 0- Rdc | no
3238859 | 0- Rdc | no
3238865 | 0- Rdc | no
3238869 | 0- Rdc | no
3238873 | 0- Rdc | no
3238877 | 0- Rdc | no
3238883 | 0- Rdc | yes
3238887 | 0- Rdc | yes
3238891 | 0- Rdc | no
3238895 | 0- Rdc | no
3238899 | 0- Rdc | no
3238903 | 0- Rdc | no
3239271 | 0- Rdc | no
3239275 | 0- Rdc | no
3239289 | 0- Rdc | no
3239355 | 0- Rdc | no
3239359 | 0- Rdc | no
3239363 | 0- Rdc | no
3239367 | 0- Rdc | no
3239434 | 0- Rdc | no
3250334 | 0- Rdc | no
3250338 | 0- Rdc | no
3250342 | 0- Rdc | no
3256915 | Rez de Rue Simon | no
3256919 | Rez de Rue Simon | no
3256923 | Rez de Rue Simon | no
3256927 | Rez de Rue Simon | no
3256931 | Rez de Rue Simon | no
3257094 | Rez de Rue Simon | no
3257149 | Rez de Rue Simon | no
3257150 | Rez de Rue Simon | no
3257215 | Rez de Rue Simon | no
3257259 | Rez de Rue Simon | no
3257260 | Rez de Rue Simon | no
3257311 | Rez de Rue Simon | no
3257333 | Rez de Rue Simon | no
3257354 | Rez de Rue Simon | no
3257358 | Rez de Rue Simon | no
3257410 | Rez de Rue Simon | no
3257411 | Rez de Rue Simon | no
3257434 | Rez de Rue Simon | no
3257438 | Rez de Rue Simon | no
3257545 | Rez de Rue Simon | no
3257549 | Rez de Rue Simon | no
3257648 | Rez de Rue Simon | no
3257652 | Rez de Rue Simon | no
3257656 | Rez de Rue Simon | no
3257660 | Rez de Rue Simon | no
3257664 | Rez de Rue Simon | no
3258220 | Rez de Rue Simon | no
3258224 | Rez de Rue Simon | no
3258228 | Rez de Rue Simon | no
3258271 | Rez de Rue Simon | no
3258275 | Rez de Rue Simon | no
3258279 | Rez de Rue Simon | no
3258283 | Rez de Rue Simon | no
3260426 | Rez de Rue Simon | no
3260430 | Rez de Rue Simon | no
3261058 | 0- Rdc | no
3261059 | 0- Rdc | yes
3261060 | 0- Rdc | no
3261061 | 0- Rdc | no
3261062 | 0- Rdc | no
3261063 | 0- Rdc | no
3263578 | Rez de Rue Simon | no
3263579 | Rez de Rue Simon | no
3263580 | Rez de Rue Simon | no
3263677 | 0- Rdc | no
3263678 | 0- Rdc | no
3263914 | 0- Rdc | no
3265516 | Rez de Rue Simon | no
3265520 | Rez de Rue Simon | no
3265524 | Rez de Rue Simon | no
3265545 | Rez de Rue Simon | no
3269439 | Rez de Rue Simon | no
3269443 | Rez de Rue Simon | no
3269447 | Rez de Rue Simon | no
3273200 | R-1 | yes
3277680 | R-1 | no
3277684 | R-1 | no
3277688 | R-1 | no
3277692 | R-1 | no
3277696 | R-1 | no
3277700 | R-1 | no
3296974 | 1-R+1 | no
3296975 | 1-R+1 | no
3296978 | 1-R+1 | no
3296979 | 1-R+1 | no
3296980 | 1-R+1 | no
3296984 | 1-R+1 | no
3296985 | 1-R+1 | no
3296986 | 1-R+1 | no
5335726 | Rez de Rue Simon | no

# IfcWallStandardCase: Mur de base:MUR 13 (63)
Type - PredefinedType: STANDARD; Material: OMD_Béton blanc 0.13 m
Type - Pset_ReinforcementBarPitchOfWall - Description: Voile béton armé 20cm
Pset_QuantityTakeOff - Reference: MUR 13; sets with these values: 2
Pset_WallCommon - IsExternal: yes; LoadBearing: no; Reference: MUR 13
Name (Mur de base:MUR 13:...) | In | ExtendToStructure
3228331 | 0- Rdc | no
3228335 | 0- Rdc | no
3228375 | 0- Rdc | no
3230407 | 0- Rdc | no
3230453 | 0- Rdc | no
3230484 | 0- Rdc | no
3230562 | 0- Rdc | no
3230572 | 0- Rdc | no
3233915 | 0- Rdc | no
3233919 | 0- Rdc | no
3233923 | 0- Rdc | no
3234127 | 0- Rdc | no
3239295 | 0- Rdc | no
3239394 | 0- Rdc | no
3239398 | 0- Rdc | no
3239402 | 0- Rdc | no
3251502 | Rez de Rue Simon | no
3251503 | Rez de Rue Simon | no
3251506 | Rez de Rue Simon | no
3258204 | Rez de Rue Simon | no
3258208 | Rez de Rue Simon | no
3258212 | Rez de Rue Simon | no
3258379 | Rez de Rue Simon | no
3258380 | Rez de Rue Simon | no
3267086 | Rez de Rue Simon | no
3267283 | Rez de Rue Simon | no
3267375 | Rez de Rue Simon | no
3268034 | Rez de Rue Simon | no
3268607 | Rez de Rue Simon | no
3268611 | Rez de Rue Simon | no
3269451 | Rez de Rue Simon | no
3270803 | R-1 | no
3270804 | R-1 | no
3270805 | R-1 | no
3270966 | R-1 | no
3270967 | R-1 | no
3270968 | R-1 | no
3273248 | R-1 | no
3273299 | R-1 | no
3273333 | R-1 | no
3275570 | R-1 | no
3275592 | R-1 | no
3277078 | R-1 | no
3277079 | R-1 | no
3288022 | 0- Rdc | no
3296972 | 1-R+1 | no
3296973 | 1-R+1 | no
3296976 | 1-R+1 | no
3296982 | 1-R+1 | no
3296983 | 1-R+1 | no
3296988 | 1-R+1 | no
3296989 | 1-R+1 | no
3296990 | 1-R+1 | no
3296991 | 1-R+1 | no
3320057 | Rez de Rue Simon | no
3326610 | Rez de Rue Simon | no
3326611 | Rez de Rue Simon | no
3469219 | Rez de Rue Simon | no
3808884 | R-1 | yes
3808944 | R-1 | no
3809050 | R-1 | yes
3809098 | R-1 | yes
3809196 | R-1 | no

# IfcWallStandardCase: Mur de base:MUR 13-2, Mur de base:MUR 13-2:3377958
In: Rez de Rue Simon
Type - PredefinedType: STANDARD; Material: OMD_Cloison 100mm 0.13 m
Type - Pset_ReinforcementBarPitchOfWall - Description: Voile béton armé 20cm
Pset_QuantityTakeOff - Reference: MUR 13-2; sets with these values: 2
Pset_WallCommon - IsExternal: yes; ExtendToStructure: no; LoadBearing: no; Reference: MUR 13-2

# IfcWallStandardCase: Mur de base:MUR 15 (7)
Type - PredefinedType: STANDARD; Material: OMD_Béton blanc 0.15 m
Type - Pset_ReinforcementBarPitchOfWall - Description: Voile béton armé 20cm
Pset_QuantityTakeOff - Reference: MUR 15; sets with these values: 2
Pset_WallCommon - IsExternal: yes; ExtendToStructure: no; LoadBearing: no; Reference: MUR 15
Name (Mur de base:MUR 15:...) | In
3230395 | 0- Rdc
3230399 | 0- Rdc
3230403 | 0- Rdc
3230439 | 0- Rdc
3250960 | Rez de Rue Simon
3250961 | Rez de Rue Simon
3250962 | Rez de Rue Simon

# IfcWallStandardCase: Mur de base:MUR 17 (10)
Type - PredefinedType: STANDARD; Material: OMD_Béton blanc 0.17 m
Type - Pset_ReinforcementBarPitchOfWall - Description: Voile béton armé 20cm
Pset_QuantityTakeOff - Reference: MUR 17; sets with these values: 2
Pset_WallCommon - IsExternal: yes; ExtendToStructure: no; LoadBearing: no; Reference: MUR 17
Name (Mur de base:MUR 17:...) | In
3229149 | 0- Rdc
3231412 | 0- Rdc
3234181 | 0- Rdc
3239406 | 0- Rdc
3258259 | Rez de Rue Simon
3258265 | Rez de Rue Simon
3268597 | Rez de Rue Simon
3268601 | Rez de Rue Simon
3286599 | R-1
3286600 | R-1

# IfcWallStandardCase: Mur de base:MUR 20 (27)
Type - PredefinedType: STANDARD; Material: Béton - Béton coulé sur place 0.2 m
Type - Pset_ReinforcementBarPitchOfWall - Description: Voile béton armé 20cm
Pset_QuantityTakeOff - Reference: MUR 20; sets with these values: 2
Pset_WallCommon - IsExternal: yes; ExtendToStructure: no; LoadBearing: no; Reference: MUR 20
Name (Mur de base:MUR 20:...) | In
3273901 | R-1
3273905 | R-1
3273909 | R-1
3273914 | R-1
3273918 | R-1
3277328 | R-1
3277332 | R-1
3277336 | R-1
3277340 | R-1
3312453 | 0- Rdc
3625451 | R-1
3625452 | R-1
3625453 | R-1
3625454 | R-1
3625524 | R-1
3625592 | R-1
3625649 | R-1
3625693 | R-1
3625747 | R-1
4288112 | R-1
4769983 | R-1
4770050 | R-1
4770109 | R-1
4888442 | 0- Rdc
4889344 | 0- Rdc
5182058 | 0- Rdc
5182247 | 0- Rdc

# IfcWallStandardCase: Mur de base:MUR 24 (3)
In: R-1
Type - PredefinedType: STANDARD; Material: OMD_Béton blanc 0.24 m
Type - Pset_ReinforcementBarPitchOfWall - Description: Voile béton armé 20cm
Pset_QuantityTakeOff - Reference: MUR 24; sets with these values: 2
Pset_WallCommon - IsExternal: yes; ExtendToStructure: no; LoadBearing: no; Reference: MUR 24
Name (Mur de base:MUR 24:...)
3271945
3271946
3272831

# IfcWallStandardCase: Mur de base:MUR 26, Mur de base:MUR 26:3227899
In: 0- Rdc
Type - PredefinedType: STANDARD; Material: OMD_Béton blanc 0.26 m
Type - Pset_ReinforcementBarPitchOfWall - Description: Voile béton armé 20cm
Pset_QuantityTakeOff - Reference: MUR 26; sets with these values: 2
Pset_WallCommon - IsExternal: yes; ExtendToStructure: no; LoadBearing: no; Reference: MUR 26

# IfcWallStandardCase: Mur de base:MUR 27, Mur de base:MUR 27:5293734
In: R-1
Type - PredefinedType: STANDARD; Material: OMD_Béton blanc 0.27 m
Type - Pset_ReinforcementBarPitchOfWall - Description: Voile béton armé 20cm
Pset_QuantityTakeOff - Reference: MUR 27; sets with these values: 2
Pset_WallCommon - IsExternal: yes; ExtendToStructure: no; LoadBearing: no; Reference: MUR 27

# IfcWallStandardCase: Mur de base:MUR 30 (51)
Type - PredefinedType: STANDARD; Material: OMD_Béton blanc 0.3 m
Type - Pset_ReinforcementBarPitchOfWall - Description: Voile béton armé 20cm
Pset_QuantityTakeOff - Reference: MUR 30; sets with these values: 2
Pset_WallCommon - IsExternal: yes; LoadBearing: no; Reference: MUR 30
Name (Mur de base:MUR 30:...) | In | ExtendToStructure
3256956 | Rez de Rue Simon | no
3267107 | Rez de Rue Simon | no
3271942 | R-1 | no
3297107 | 2-R+2 | yes
3297108 | 2-R+2 | yes
3297110 | 2-R+2 | yes
3297113 | 2-R+2 | yes
3297114 | 2-R+2 | yes
3624738 | 2-R+2 | yes
3624841 | 2-R+2 | yes
3624920 | 2-R+2 | yes
3625010 | 2-R+2 | yes
3625096 | 2-R+2 | yes
3625171 | 2-R+2 | yes
3630288 | Rez de Rue Simon | no
3630289 | Rez de Rue Simon | no
3630291 | Rez de Rue Simon | no
3630294 | Rez de Rue Simon | no
3630295 | Rez de Rue Simon | no
3630296 | Rez de Rue Simon | no
3630297 | Rez de Rue Simon | no
3630298 | Rez de Rue Simon | no
3630299 | Rez de Rue Simon | no
3630398 | Rez de Rue Simon | no
3630402 | Rez de Rue Simon | no
3630406 | Rez de Rue Simon | no
3630410 | Rez de Rue Simon | no
3630435 | Rez de Rue Simon | no
3630439 | Rez de Rue Simon | no
3630443 | Rez de Rue Simon | no
3630447 | Rez de Rue Simon | no
3630451 | Rez de Rue Simon | no
3630564 | Rez de Rue Simon | no
3630795 | Rez de Rue Simon | no
3630800 | Rez de Rue Simon | no
3630805 | Rez de Rue Simon | no
3630810 | Rez de Rue Simon | no
3630815 | Rez de Rue Simon | no
3630820 | Rez de Rue Simon | no
3630831 | Rez de Rue Simon | no
3630862 | Rez de Rue Simon | no
3630866 | Rez de Rue Simon | no
3631003 | Rez de Rue Simon | no
3631007 | Rez de Rue Simon | no
3631011 | Rez de Rue Simon | no
3631015 | Rez de Rue Simon | no
3631019 | Rez de Rue Simon | no
3631023 | Rez de Rue Simon | no
3631103 | Rez de Rue Simon | no
4204240 | R-1 | no
4204241 | R-1 | no

# IfcWallStandardCase: Mur de base:MUR 35 (26)
Type - PredefinedType: STANDARD; Material: OMD_Béton blanc 0.35 m
Type - Pset_ReinforcementBarPitchOfWall - Description: Voile béton armé 20cm
Pset_QuantityTakeOff - Reference: MUR 35; sets with these values: 2
Pset_WallCommon - Reference: MUR 35; IsExternal: yes; LoadBearing: no
Name (Mur de base:MUR 35:...) | In | ExtendToStructure
3227843 | 0- Rdc | no
3227847 | 0- Rdc | no
3227989 | 0- Rdc | no
3227997 | 0- Rdc | no
3256962 | Rez de Rue Simon | no
3259646 | Rez de Rue Simon | no
3265382 | Rez de Rue Simon | no
3294419 | 1-R+1 | no
3294420 | 1-R+1 | no
3294421 | 1-R+1 | no
3294422 | 1-R+1 | no
3294423 | 1-R+1 | no
3294424 | 1-R+1 | no
3294425 | 1-R+1 | no
3294426 | 1-R+1 | no
3297599 | 2-R+2 | yes
3626060 | R-1 | no
3626235 | R-1 | no
3626328 | R-1 | no
3626416 | R-1 | no
3626484 | R-1 | no
3626571 | R-1 | no
3626624 | R-1 | no
3626718 | R-1 | no
4895833 | 0- Rdc | no
4896983 | 0- Rdc | no

# IfcWallStandardCase: Mur de base:MUR 49.5 (2)
In: Rez de Rue Simon
Type - PredefinedType: STANDARD; Material: OMD_Béton blanc 0.495 m
Type - Pset_ReinforcementBarPitchOfWall - Description: Voile béton armé 20cm
Pset_QuantityTakeOff - Reference: MUR 49.5; sets with these values: 2
Pset_WallCommon - IsExternal: yes; LoadBearing: no; Reference: MUR 49.5
Name (Mur de base:MUR 49.5:...) | ExtendToStructure
3265371 | no
4817386 | yes

# IfcWallStandardCase: Mur de base:MUR 5 (10)
Type - PredefinedType: STANDARD; Material: OMD_Béton blanc 0.05 m
Type - Pset_ReinforcementBarPitchOfWall - Description: Voile béton armé 20cm
Pset_QuantityTakeOff - Reference: MUR 5; sets with these values: 2
Pset_WallCommon - IsExternal: yes; LoadBearing: no; Reference: MUR 5
Name (Mur de base:MUR 5:...) | In | ExtendToStructure
3233556 | 0- Rdc | no
3235132 | 0- Rdc | no
3255276 | Rez de Rue Simon | no
3265510 | Rez de Rue Simon | no
3268224 | Rez de Rue Simon | no
3268228 | Rez de Rue Simon | no
3268232 | Rez de Rue Simon | no
4821202 | Rez de Rue Simon | yes
4821234 | Rez de Rue Simon | yes
4823393 | Rez de Rue Simon | yes

# IfcWallStandardCase: Mur de base:MUR 5 PIERRE (3)
In: Rez de Rue Simon
Type - PredefinedType: STANDARD; Material: OMD_PIERRE 0.05 m
Type - Pset_ReinforcementBarPitchOfWall - Description: Voile béton armé 20cm
Pset_QuantityTakeOff - Reference: MUR 5 PIERRE; sets with these values: 2
Pset_WallCommon - IsExternal: yes; ExtendToStructure: no; LoadBearing: no; Reference: MUR 5 PIERRE
Name (Mur de base:MUR 5 PIERRE:...)
4312608
4315267
4316562

# IfcWallStandardCase: Mur de base:MUR 55, Mur de base:MUR 55:3264883
In: Rez de Rue Simon
Type - PredefinedType: STANDARD; Material: OMD_Béton blanc 0.55 m
Type - Pset_ReinforcementBarPitchOfWall - Description: Voile béton armé 20cm
Pset_QuantityTakeOff - Reference: MUR 55; sets with these values: 2
Pset_WallCommon - IsExternal: yes; ExtendToStructure: no; LoadBearing: no; Reference: MUR 55

# IfcWallStandardCase: Mur de base:MUR 7 (17)
Type - PredefinedType: STANDARD; Material: OMD_Béton blanc 0.07 m
Type - Pset_ReinforcementBarPitchOfWall - Description: Voile béton armé 20cm
Pset_QuantityTakeOff - Reference: MUR 7; sets with these values: 2
Pset_WallCommon - IsExternal: yes; ExtendToStructure: no; LoadBearing: no; Reference: MUR 7
Name (Mur de base:MUR 7:...) | In
3235074 | 0- Rdc
3235078 | 0- Rdc
3235082 | 0- Rdc
3235107 | 0- Rdc
3235111 | 0- Rdc
3235136 | 0- Rdc
3238715 | 0- Rdc
3239502 | 0- Rdc
3239506 | 0- Rdc
3255219 | Rez de Rue Simon
3255223 | Rez de Rue Simon
3255227 | Rez de Rue Simon
3255250 | Rez de Rue Simon
3268745 | Rez de Rue Simon
3268749 | Rez de Rue Simon
3273375 | R-1
3277081 | R-1

# IfcWallStandardCase: Mur de base:MUR 75 (3)
In: Rez de Rue Simon
Type - PredefinedType: STANDARD; Material: OMD_Béton blanc 0.75 m
Type - Pset_ReinforcementBarPitchOfWall - Description: Voile béton armé 20cm
Pset_QuantityTakeOff - Reference: MUR 75; sets with these values: 2
Pset_WallCommon - IsExternal: yes; ExtendToStructure: no; LoadBearing: no; Reference: MUR 75
Name (Mur de base:MUR 75:...)
3630618
3630662
3630723

# IfcWallStandardCase: Mur de base:ba13 (3)
In: Rez de Rue Simon
Type - PredefinedType: STANDARD; Material: OMD_Cloison 100mm 0.013 m
Type - Pset_ReinforcementBarPitchOfWall - Description: Cloison 98/48 BA25
Pset_QuantityTakeOff - Reference: ba13; sets with these values: 2
Pset_WallCommon - ExtendToStructure: no; LoadBearing: no; IsExternal: no; Reference: ba13
Name (Mur de base:ba13:...)
3558470
3558524
3558754

# IfcWallStandardCase: Mur de base:faïence (8)
Type - PredefinedType: STANDARD; Material: OMD_faïence 6.5*20 0.02 m
Type - Pset_ReinforcementBarPitchOfWall - Description: Cloison en stratifié compact
Pset_QuantityTakeOff - Reference: faïence; sets with these values: 2
Pset_WallCommon - LoadBearing: no; IsExternal: no; Reference: faïence
Name (Mur de base:faïence:...) | In | ExtendToStructure
3503787 | Rez de Rue Simon | yes
4017149 | Rez de Rue Simon | yes
4291455 | rez de rue -1.10m | no
4291533 | rez de rue -1.10m | no
4291662 | rez de rue -1.10m | no
4291795 | rez de rue -1.10m | yes
4291920 | rez de rue -1.10m | no
4292009 | rez de rue -1.10m | yes

# IfcWallStandardCase: Mur de base:faïence SANITAIRES (9)
In: Rez de Rue Simon
Type - PredefinedType: STANDARD; Material: OMD-faience saniataires 0.02 m
Type - Pset_ReinforcementBarPitchOfWall - Description: Cloison en stratifié compact
Pset_QuantityTakeOff - Reference: faïence SANITAIRES; sets with these values: 2
Pset_WallCommon - ExtendToStructure: no; LoadBearing: no; IsExternal: no; Reference: faïence SANITAIRES
Name (Mur de base:faïence SANITAIRES:...)
4210743
4210803
4210911
4210972
4211008
4211135
4211192
4211242
4211389

# IfcWallStandardCase: Mur de base:faïence douches (15)
In: rez de rue -1.10m
Type - PredefinedType: STANDARD; Material: OMD faience douche 60*120 0.02 m
Type - Pset_ReinforcementBarPitchOfWall - Description: Cloison en stratifié compact
Pset_QuantityTakeOff - Reference: faïence douches; sets with these values: 2
Pset_WallCommon - ExtendToStructure: no; LoadBearing: no; IsExternal: no; Reference: faïence douches
Name (Mur de base:faïence douches:...)
4293072
4293152
4293221
4293298
4293405
4293442
4293489
4294030
4294076
4294130
4294174
4294319
4294421
4294492
4294541

# IfcWallStandardCase: Mur de base:joue plâtre (7)
Type - PredefinedType: STANDARD; Material: OMD_Cloison 100mm 0.02 m
Type - Pset_ReinforcementBarPitchOfWall - Description: Cloison 98/48 BA25
Pset_QuantityTakeOff - Reference: joue plâtre; sets with these values: 2
Pset_WallCommon - LoadBearing: no; IsExternal: no; Reference: joue plâtre
Name (Mur de base:joue plâtre:...) | In | ExtendToStructure
3498601 | Rez de Rue Simon | no
3498609 | Rez de Rue Simon | no
4165794 | rez de rue -1.10m | yes
5185160 | Rez de Rue Simon | no
5447561 | Rez de Rue Simon | no
5471053 | Rez de Rue Simon | no
5471813 | Rez de Rue Simon | no

# IfcWallStandardCase: Mur de base:miroir (2)
In: rez de rue -1.10m
Type - PredefinedType: STANDARD; Material: OMD-miroir 0.005 m
Type - Pset_ReinforcementBarPitchOfWall - Description: Cloison en stratifié compact
Pset_QuantityTakeOff - Reference: miroir; sets with these values: 2
Pset_WallCommon - LoadBearing: no; IsExternal: no; Reference: miroir
Name (Mur de base:miroir:...) | ExtendToStructure
4237719 | yes
4237914 | no

# IfcWallStandardCase: Mur de base:mur pierre 42cm (2)
In: Rez de Rue Simon
Type - PredefinedType: STANDARD; Material: OMD tranche 0.42 m
Type - Pset_ReinforcementBarPitchOfWall - Description: Voile béton armé 20cm
Pset_QuantityTakeOff - Reference: mur pierre 42cm; sets with these values: 2
Pset_WallCommon - IsExternal: yes; ExtendToStructure: no; LoadBearing: no; Reference: mur pierre 42cm
Name (Mur de base:mur pierre 42cm:...)
3981886
3982466

# IfcWallStandardCase: Mur de base:panneaux acoustiques (3)
In: Rez de Rue Simon
Type - PredefinedType: STANDARD; Material: OMD_panneaux bois 0.02 m, Maçonnerie - Isolant 0.022 m
Type - Pset_ReinforcementBarPitchOfWall - Description: Carreaux de Platre 7 cm
Pset_QuantityTakeOff - Reference: panneaux acoustiques; sets with these values: 2
Pset_WallCommon - LoadBearing: no; IsExternal: no; Reference: panneaux acoustiques
Name (Mur de base:panneaux acoustiques:...) | ExtendToStructure
4172139 | yes
5447812 | no
5448147 | no

# IfcWallStandardCase: Mur de base:poteaux BA 50 (4)
In: R-1
Type - PredefinedType: STANDARD; Material: OMD tranche 0.5 m
Type - Pset_ReinforcementBarPitchOfWall - Description: Voile béton armé 20cm
Pset_QuantityTakeOff - Reference: poteaux BA 50; sets with these values: 2
Pset_WallCommon - IsExternal: yes; ExtendToStructure: no; LoadBearing: no; Reference: poteaux BA 50
Name (Mur de base:poteaux BA 50:...)
3559797
3560034
3560144
3560174

# IfcWindow: Fenêtre de toit:Fenêtre de toit (2)
In: 2-R+2
Type - ParameterTakesPrecedence: no; Sizeable: no; Material: <Unnamed>, Fenêtre de toit - Cadre, Fenêtre - Vitrage
Type - Pset_WindowCommon - ThermalTransmittance: 3.6886 kg/K/s3
OverallHeight: 1.57124 m; OverallWidth: 1.22 m
Pset_QuantityTakeOff - Reference: Fenêtre de toit
Pset_WindowCommon - IsExternal: yes; Reference: Fenêtre de toit
Name (Fenêtre de toit:Fenêtre de toit:...)
4782988
4783157

# IfcWindow: OMD_Ouvrant:Battant (3)
In: 0- Rdc
Type - ParameterTakesPrecedence: no; Sizeable: no; Material: polycarbonate blanc, Aluminium
OverallHeight: 0.200793 m
Pset_QuantityTakeOff - Reference: Battant
Pset_WindowCommon - IsExternal: yes; Reference: Battant
Name (OMD_Ouvrant:Battant:...) | OverallWidth (m)
5289649 | 0.9624
5289670 | 0.9624
5289695 | 0.96965

# IfcWindow: OMD_Ouvrant:Oscillo Battant (9)
Type - ParameterTakesPrecedence: no; Sizeable: no; Material: polycarbonate blanc, Aluminium
Pset_QuantityTakeOff - Reference: Oscillo Battant
Pset_WindowCommon - IsExternal: yes; Reference: Oscillo Battant
Name (OMD_Ouvrant:Oscillo Battant:...) | In | OverallHeight (m) | OverallWidth (m)
4317774 | Rez de Rue Simon | 0.9 | 0.773148
4318283 | Rez de Rue Simon | 0.9 | 0.766047
4317905 | Rez de Rue Simon | 0.9 | 0.767672
4730105 | Rez de Rue Simon | 0.9 | 0.76505
4318022 | Rez de Rue Simon | 0.9 | 0.767672
4318134 | Rez de Rue Simon | 0.9 | 0.767672
5369713 | 0- Rdc | 0.200793 | 0.96965
5289603 | 0- Rdc | 0.200793 | 0.9624
5370266 | 0- Rdc | 0.200793 | 0.9624
